VERSION 5.8 ;
BUSBITCHARS "[]" ;
DIVIDERCHAR "/" ;
UNITS
    DATABASE MICRONS 1000 ;
END UNITS

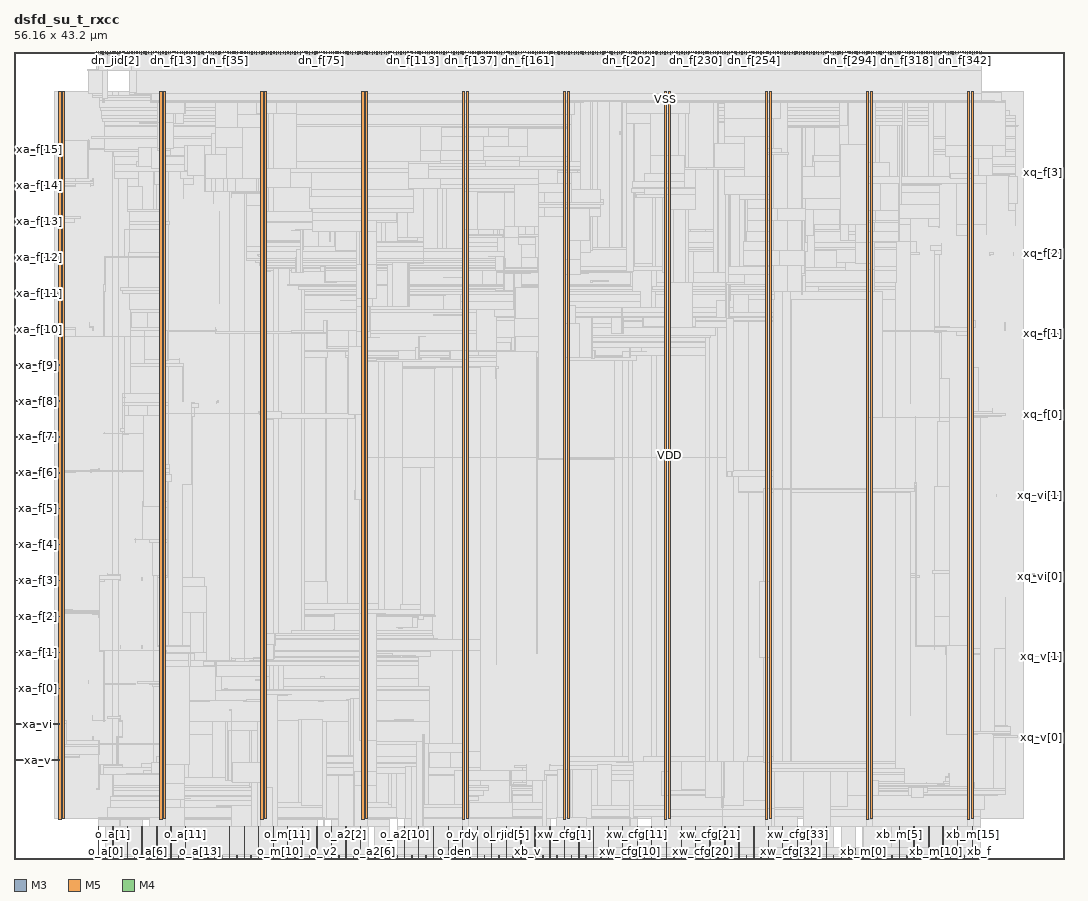
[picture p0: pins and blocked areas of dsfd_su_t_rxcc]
MACRO dsfd_su_t_rxcc
  FOREIGN dsfd_su_t_rxcc 0 0 ;
  CLASS BLOCK ;
  SIZE 56.16 BY 43.2 ;
  PIN ck
    DIRECTION INPUT ;
    USE SIGNAL ;
    PORT
      LAYER M3 ;
        RECT  28.008 43.056 28.026 43.2 ;
    END
  END ck
  PIN dn_f[0]
    DIRECTION INPUT ;
    USE SIGNAL ;
    PORT
      LAYER M5 ;
        RECT  6.816 43.008 6.84 43.2 ;
    END
  END dn_f[0]
  PIN dn_f[100]
    DIRECTION INPUT ;
    USE SIGNAL ;
    PORT
      LAYER M5 ;
        RECT  19.632 43.008 19.656 43.2 ;
    END
  END dn_f[100]
  PIN dn_f[101]
    DIRECTION INPUT ;
    USE SIGNAL ;
    PORT
      LAYER M3 ;
        RECT  19.8 43.056 19.818 43.2 ;
    END
  END dn_f[101]
  PIN dn_f[102]
    DIRECTION INPUT ;
    USE SIGNAL ;
    PORT
      LAYER M5 ;
        RECT  19.92 43.008 19.944 43.2 ;
    END
  END dn_f[102]
  PIN dn_f[103]
    DIRECTION INPUT ;
    USE SIGNAL ;
    PORT
      LAYER M3 ;
        RECT  20.052 43.056 20.07 43.2 ;
    END
  END dn_f[103]
  PIN dn_f[104]
    DIRECTION INPUT ;
    USE SIGNAL ;
    PORT
      LAYER M5 ;
        RECT  20.16 43.008 20.184 43.2 ;
    END
  END dn_f[104]
  PIN dn_f[105]
    DIRECTION INPUT ;
    USE SIGNAL ;
    PORT
      LAYER M3 ;
        RECT  20.304 43.056 20.322 43.2 ;
    END
  END dn_f[105]
  PIN dn_f[106]
    DIRECTION INPUT ;
    USE SIGNAL ;
    PORT
      LAYER M5 ;
        RECT  20.448 43.008 20.472 43.2 ;
    END
  END dn_f[106]
  PIN dn_f[107]
    DIRECTION INPUT ;
    USE SIGNAL ;
    PORT
      LAYER M3 ;
        RECT  20.556 43.056 20.574 43.2 ;
    END
  END dn_f[107]
  PIN dn_f[108]
    DIRECTION INPUT ;
    USE SIGNAL ;
    PORT
      LAYER M5 ;
        RECT  20.688 43.008 20.712 43.2 ;
    END
  END dn_f[108]
  PIN dn_f[109]
    DIRECTION INPUT ;
    USE SIGNAL ;
    PORT
      LAYER M3 ;
        RECT  20.808 43.056 20.826 43.2 ;
    END
  END dn_f[109]
  PIN dn_f[10]
    DIRECTION INPUT ;
    USE SIGNAL ;
    PORT
      LAYER M5 ;
        RECT  8.112 43.008 8.136 43.2 ;
    END
  END dn_f[10]
  PIN dn_f[110]
    DIRECTION INPUT ;
    USE SIGNAL ;
    PORT
      LAYER M5 ;
        RECT  20.928 43.008 20.952 43.2 ;
    END
  END dn_f[110]
  PIN dn_f[111]
    DIRECTION INPUT ;
    USE SIGNAL ;
    PORT
      LAYER M3 ;
        RECT  21.06 43.056 21.078 43.2 ;
    END
  END dn_f[111]
  PIN dn_f[112]
    DIRECTION INPUT ;
    USE SIGNAL ;
    PORT
      LAYER M5 ;
        RECT  21.216 43.008 21.24 43.2 ;
    END
  END dn_f[112]
  PIN dn_f[113]
    DIRECTION INPUT ;
    USE SIGNAL ;
    PORT
      LAYER M3 ;
        RECT  21.312 43.056 21.33 43.2 ;
    END
  END dn_f[113]
  PIN dn_f[114]
    DIRECTION INPUT ;
    USE SIGNAL ;
    PORT
      LAYER M5 ;
        RECT  21.456 43.008 21.48 43.2 ;
    END
  END dn_f[114]
  PIN dn_f[115]
    DIRECTION INPUT ;
    USE SIGNAL ;
    PORT
      LAYER M3 ;
        RECT  21.6 43.056 21.618 43.2 ;
    END
  END dn_f[115]
  PIN dn_f[116]
    DIRECTION INPUT ;
    USE SIGNAL ;
    PORT
      LAYER M5 ;
        RECT  21.696 43.008 21.72 43.2 ;
    END
  END dn_f[116]
  PIN dn_f[117]
    DIRECTION INPUT ;
    USE SIGNAL ;
    PORT
      LAYER M3 ;
        RECT  21.852 43.056 21.87 43.2 ;
    END
  END dn_f[117]
  PIN dn_f[118]
    DIRECTION INPUT ;
    USE SIGNAL ;
    PORT
      LAYER M5 ;
        RECT  21.984 43.008 22.008 43.2 ;
    END
  END dn_f[118]
  PIN dn_f[119]
    DIRECTION INPUT ;
    USE SIGNAL ;
    PORT
      LAYER M3 ;
        RECT  22.104 43.056 22.122 43.2 ;
    END
  END dn_f[119]
  PIN dn_f[11]
    DIRECTION INPUT ;
    USE SIGNAL ;
    PORT
      LAYER M3 ;
        RECT  8.244 43.056 8.262 43.2 ;
    END
  END dn_f[11]
  PIN dn_f[120]
    DIRECTION INPUT ;
    USE SIGNAL ;
    PORT
      LAYER M5 ;
        RECT  22.224 43.008 22.248 43.2 ;
    END
  END dn_f[120]
  PIN dn_f[121]
    DIRECTION INPUT ;
    USE SIGNAL ;
    PORT
      LAYER M3 ;
        RECT  22.356 43.056 22.374 43.2 ;
    END
  END dn_f[121]
  PIN dn_f[122]
    DIRECTION INPUT ;
    USE SIGNAL ;
    PORT
      LAYER M5 ;
        RECT  22.464 43.008 22.488 43.2 ;
    END
  END dn_f[122]
  PIN dn_f[123]
    DIRECTION INPUT ;
    USE SIGNAL ;
    PORT
      LAYER M3 ;
        RECT  22.608 43.056 22.626 43.2 ;
    END
  END dn_f[123]
  PIN dn_f[124]
    DIRECTION INPUT ;
    USE SIGNAL ;
    PORT
      LAYER M5 ;
        RECT  22.752 43.008 22.776 43.2 ;
    END
  END dn_f[124]
  PIN dn_f[125]
    DIRECTION INPUT ;
    USE SIGNAL ;
    PORT
      LAYER M3 ;
        RECT  22.86 43.056 22.878 43.2 ;
    END
  END dn_f[125]
  PIN dn_f[126]
    DIRECTION INPUT ;
    USE SIGNAL ;
    PORT
      LAYER M5 ;
        RECT  22.992 43.008 23.016 43.2 ;
    END
  END dn_f[126]
  PIN dn_f[127]
    DIRECTION INPUT ;
    USE SIGNAL ;
    PORT
      LAYER M3 ;
        RECT  23.112 43.056 23.13 43.2 ;
    END
  END dn_f[127]
  PIN dn_f[128]
    DIRECTION INPUT ;
    USE SIGNAL ;
    PORT
      LAYER M5 ;
        RECT  23.232 43.008 23.256 43.2 ;
    END
  END dn_f[128]
  PIN dn_f[129]
    DIRECTION INPUT ;
    USE SIGNAL ;
    PORT
      LAYER M3 ;
        RECT  23.4 43.056 23.418 43.2 ;
    END
  END dn_f[129]
  PIN dn_f[12]
    DIRECTION INPUT ;
    USE SIGNAL ;
    PORT
      LAYER M5 ;
        RECT  8.352 43.008 8.376 43.2 ;
    END
  END dn_f[12]
  PIN dn_f[130]
    DIRECTION INPUT ;
    USE SIGNAL ;
    PORT
      LAYER M5 ;
        RECT  23.52 43.008 23.544 43.2 ;
    END
  END dn_f[130]
  PIN dn_f[131]
    DIRECTION INPUT ;
    USE SIGNAL ;
    PORT
      LAYER M3 ;
        RECT  23.652 43.056 23.67 43.2 ;
    END
  END dn_f[131]
  PIN dn_f[132]
    DIRECTION INPUT ;
    USE SIGNAL ;
    PORT
      LAYER M5 ;
        RECT  23.76 43.008 23.784 43.2 ;
    END
  END dn_f[132]
  PIN dn_f[133]
    DIRECTION INPUT ;
    USE SIGNAL ;
    PORT
      LAYER M3 ;
        RECT  23.904 43.056 23.922 43.2 ;
    END
  END dn_f[133]
  PIN dn_f[134]
    DIRECTION INPUT ;
    USE SIGNAL ;
    PORT
      LAYER M5 ;
        RECT  24 43.008 24.024 43.2 ;
    END
  END dn_f[134]
  PIN dn_f[135]
    DIRECTION INPUT ;
    USE SIGNAL ;
    PORT
      LAYER M3 ;
        RECT  24.156 43.056 24.174 43.2 ;
    END
  END dn_f[135]
  PIN dn_f[136]
    DIRECTION INPUT ;
    USE SIGNAL ;
    PORT
      LAYER M5 ;
        RECT  24.288 43.008 24.312 43.2 ;
    END
  END dn_f[136]
  PIN dn_f[137]
    DIRECTION INPUT ;
    USE SIGNAL ;
    PORT
      LAYER M3 ;
        RECT  24.408 43.056 24.426 43.2 ;
    END
  END dn_f[137]
  PIN dn_f[138]
    DIRECTION INPUT ;
    USE SIGNAL ;
    PORT
      LAYER M5 ;
        RECT  24.528 43.008 24.552 43.2 ;
    END
  END dn_f[138]
  PIN dn_f[139]
    DIRECTION INPUT ;
    USE SIGNAL ;
    PORT
      LAYER M3 ;
        RECT  24.66 43.056 24.678 43.2 ;
    END
  END dn_f[139]
  PIN dn_f[13]
    DIRECTION INPUT ;
    USE SIGNAL ;
    PORT
      LAYER M3 ;
        RECT  8.496 43.056 8.514 43.2 ;
    END
  END dn_f[13]
  PIN dn_f[140]
    DIRECTION INPUT ;
    USE SIGNAL ;
    PORT
      LAYER M5 ;
        RECT  24.816 43.008 24.84 43.2 ;
    END
  END dn_f[140]
  PIN dn_f[141]
    DIRECTION INPUT ;
    USE SIGNAL ;
    PORT
      LAYER M3 ;
        RECT  24.912 43.056 24.93 43.2 ;
    END
  END dn_f[141]
  PIN dn_f[142]
    DIRECTION INPUT ;
    USE SIGNAL ;
    PORT
      LAYER M5 ;
        RECT  25.056 43.008 25.08 43.2 ;
    END
  END dn_f[142]
  PIN dn_f[143]
    DIRECTION INPUT ;
    USE SIGNAL ;
    PORT
      LAYER M3 ;
        RECT  25.164 43.056 25.182 43.2 ;
    END
  END dn_f[143]
  PIN dn_f[144]
    DIRECTION INPUT ;
    USE SIGNAL ;
    PORT
      LAYER M5 ;
        RECT  25.296 43.008 25.32 43.2 ;
    END
  END dn_f[144]
  PIN dn_f[145]
    DIRECTION INPUT ;
    USE SIGNAL ;
    PORT
      LAYER M3 ;
        RECT  25.452 43.056 25.47 43.2 ;
    END
  END dn_f[145]
  PIN dn_f[146]
    DIRECTION INPUT ;
    USE SIGNAL ;
    PORT
      LAYER M5 ;
        RECT  25.584 43.008 25.608 43.2 ;
    END
  END dn_f[146]
  PIN dn_f[147]
    DIRECTION INPUT ;
    USE SIGNAL ;
    PORT
      LAYER M3 ;
        RECT  25.704 43.056 25.722 43.2 ;
    END
  END dn_f[147]
  PIN dn_f[148]
    DIRECTION INPUT ;
    USE SIGNAL ;
    PORT
      LAYER M5 ;
        RECT  25.824 43.008 25.848 43.2 ;
    END
  END dn_f[148]
  PIN dn_f[149]
    DIRECTION INPUT ;
    USE SIGNAL ;
    PORT
      LAYER M3 ;
        RECT  25.956 43.056 25.974 43.2 ;
    END
  END dn_f[149]
  PIN dn_f[14]
    DIRECTION INPUT ;
    USE SIGNAL ;
    PORT
      LAYER M5 ;
        RECT  8.592 43.008 8.616 43.2 ;
    END
  END dn_f[14]
  PIN dn_f[150]
    DIRECTION INPUT ;
    USE SIGNAL ;
    PORT
      LAYER M5 ;
        RECT  26.064 43.008 26.088 43.2 ;
    END
  END dn_f[150]
  PIN dn_f[151]
    DIRECTION INPUT ;
    USE SIGNAL ;
    PORT
      LAYER M3 ;
        RECT  26.208 43.056 26.226 43.2 ;
    END
  END dn_f[151]
  PIN dn_f[152]
    DIRECTION INPUT ;
    USE SIGNAL ;
    PORT
      LAYER M5 ;
        RECT  26.352 43.008 26.376 43.2 ;
    END
  END dn_f[152]
  PIN dn_f[153]
    DIRECTION INPUT ;
    USE SIGNAL ;
    PORT
      LAYER M3 ;
        RECT  26.46 43.056 26.478 43.2 ;
    END
  END dn_f[153]
  PIN dn_f[154]
    DIRECTION INPUT ;
    USE SIGNAL ;
    PORT
      LAYER M5 ;
        RECT  26.592 43.008 26.616 43.2 ;
    END
  END dn_f[154]
  PIN dn_f[155]
    DIRECTION INPUT ;
    USE SIGNAL ;
    PORT
      LAYER M3 ;
        RECT  26.712 43.056 26.73 43.2 ;
    END
  END dn_f[155]
  PIN dn_f[156]
    DIRECTION INPUT ;
    USE SIGNAL ;
    PORT
      LAYER M5 ;
        RECT  26.832 43.008 26.856 43.2 ;
    END
  END dn_f[156]
  PIN dn_f[157]
    DIRECTION INPUT ;
    USE SIGNAL ;
    PORT
      LAYER M3 ;
        RECT  26.964 43.056 26.982 43.2 ;
    END
  END dn_f[157]
  PIN dn_f[158]
    DIRECTION INPUT ;
    USE SIGNAL ;
    PORT
      LAYER M5 ;
        RECT  27.12 43.008 27.144 43.2 ;
    END
  END dn_f[158]
  PIN dn_f[159]
    DIRECTION INPUT ;
    USE SIGNAL ;
    PORT
      LAYER M3 ;
        RECT  27.252 43.056 27.27 43.2 ;
    END
  END dn_f[159]
  PIN dn_f[15]
    DIRECTION INPUT ;
    USE SIGNAL ;
    PORT
      LAYER M3 ;
        RECT  8.748 43.056 8.766 43.2 ;
    END
  END dn_f[15]
  PIN dn_f[160]
    DIRECTION INPUT ;
    USE SIGNAL ;
    PORT
      LAYER M5 ;
        RECT  27.36 43.008 27.384 43.2 ;
    END
  END dn_f[160]
  PIN dn_f[161]
    DIRECTION INPUT ;
    USE SIGNAL ;
    PORT
      LAYER M3 ;
        RECT  27.504 43.056 27.522 43.2 ;
    END
  END dn_f[161]
  PIN dn_f[162]
    DIRECTION INPUT ;
    USE SIGNAL ;
    PORT
      LAYER M5 ;
        RECT  27.6 43.008 27.624 43.2 ;
    END
  END dn_f[162]
  PIN dn_f[163]
    DIRECTION INPUT ;
    USE SIGNAL ;
    PORT
      LAYER M3 ;
        RECT  27.756 43.056 27.774 43.2 ;
    END
  END dn_f[163]
  PIN dn_f[164]
    DIRECTION INPUT ;
    USE SIGNAL ;
    PORT
      LAYER M5 ;
        RECT  27.888 43.008 27.912 43.2 ;
    END
  END dn_f[164]
  PIN dn_f[165]
    DIRECTION INPUT ;
    USE SIGNAL ;
    PORT
      LAYER M5 ;
        RECT  28.128 43.008 28.152 43.2 ;
    END
  END dn_f[165]
  PIN dn_f[166]
    DIRECTION INPUT ;
    USE SIGNAL ;
    PORT
      LAYER M3 ;
        RECT  28.26 43.056 28.278 43.2 ;
    END
  END dn_f[166]
  PIN dn_f[167]
    DIRECTION INPUT ;
    USE SIGNAL ;
    PORT
      LAYER M5 ;
        RECT  28.368 43.008 28.392 43.2 ;
    END
  END dn_f[167]
  PIN dn_f[168]
    DIRECTION INPUT ;
    USE SIGNAL ;
    PORT
      LAYER M3 ;
        RECT  28.512 43.056 28.53 43.2 ;
    END
  END dn_f[168]
  PIN dn_f[169]
    DIRECTION INPUT ;
    USE SIGNAL ;
    PORT
      LAYER M5 ;
        RECT  28.656 43.008 28.68 43.2 ;
    END
  END dn_f[169]
  PIN dn_f[16]
    DIRECTION INPUT ;
    USE SIGNAL ;
    PORT
      LAYER M5 ;
        RECT  8.88 43.008 8.904 43.2 ;
    END
  END dn_f[16]
  PIN dn_f[170]
    DIRECTION INPUT ;
    USE SIGNAL ;
    PORT
      LAYER M3 ;
        RECT  28.764 43.056 28.782 43.2 ;
    END
  END dn_f[170]
  PIN dn_f[171]
    DIRECTION INPUT ;
    USE SIGNAL ;
    PORT
      LAYER M5 ;
        RECT  28.896 43.008 28.92 43.2 ;
    END
  END dn_f[171]
  PIN dn_f[172]
    DIRECTION INPUT ;
    USE SIGNAL ;
    PORT
      LAYER M3 ;
        RECT  29.052 43.056 29.07 43.2 ;
    END
  END dn_f[172]
  PIN dn_f[173]
    DIRECTION INPUT ;
    USE SIGNAL ;
    PORT
      LAYER M5 ;
        RECT  29.136 43.008 29.16 43.2 ;
    END
  END dn_f[173]
  PIN dn_f[174]
    DIRECTION INPUT ;
    USE SIGNAL ;
    PORT
      LAYER M3 ;
        RECT  29.304 43.056 29.322 43.2 ;
    END
  END dn_f[174]
  PIN dn_f[175]
    DIRECTION INPUT ;
    USE SIGNAL ;
    PORT
      LAYER M5 ;
        RECT  29.424 43.008 29.448 43.2 ;
    END
  END dn_f[175]
  PIN dn_f[176]
    DIRECTION INPUT ;
    USE SIGNAL ;
    PORT
      LAYER M3 ;
        RECT  29.556 43.056 29.574 43.2 ;
    END
  END dn_f[176]
  PIN dn_f[177]
    DIRECTION INPUT ;
    USE SIGNAL ;
    PORT
      LAYER M5 ;
        RECT  29.664 43.008 29.688 43.2 ;
    END
  END dn_f[177]
  PIN dn_f[178]
    DIRECTION INPUT ;
    USE SIGNAL ;
    PORT
      LAYER M3 ;
        RECT  29.808 43.056 29.826 43.2 ;
    END
  END dn_f[178]
  PIN dn_f[179]
    DIRECTION INPUT ;
    USE SIGNAL ;
    PORT
      LAYER M5 ;
        RECT  29.952 43.008 29.976 43.2 ;
    END
  END dn_f[179]
  PIN dn_f[17]
    DIRECTION INPUT ;
    USE SIGNAL ;
    PORT
      LAYER M3 ;
        RECT  9 43.056 9.018 43.2 ;
    END
  END dn_f[17]
  PIN dn_f[180]
    DIRECTION INPUT ;
    USE SIGNAL ;
    PORT
      LAYER M3 ;
        RECT  30.06 43.056 30.078 43.2 ;
    END
  END dn_f[180]
  PIN dn_f[181]
    DIRECTION INPUT ;
    USE SIGNAL ;
    PORT
      LAYER M5 ;
        RECT  30.192 43.008 30.216 43.2 ;
    END
  END dn_f[181]
  PIN dn_f[182]
    DIRECTION INPUT ;
    USE SIGNAL ;
    PORT
      LAYER M3 ;
        RECT  30.312 43.056 30.33 43.2 ;
    END
  END dn_f[182]
  PIN dn_f[183]
    DIRECTION INPUT ;
    USE SIGNAL ;
    PORT
      LAYER M5 ;
        RECT  30.432 43.008 30.456 43.2 ;
    END
  END dn_f[183]
  PIN dn_f[184]
    DIRECTION INPUT ;
    USE SIGNAL ;
    PORT
      LAYER M3 ;
        RECT  30.564 43.056 30.582 43.2 ;
    END
  END dn_f[184]
  PIN dn_f[185]
    DIRECTION INPUT ;
    USE SIGNAL ;
    PORT
      LAYER M5 ;
        RECT  30.72 43.008 30.744 43.2 ;
    END
  END dn_f[185]
  PIN dn_f[186]
    DIRECTION INPUT ;
    USE SIGNAL ;
    PORT
      LAYER M3 ;
        RECT  30.816 43.056 30.834 43.2 ;
    END
  END dn_f[186]
  PIN dn_f[187]
    DIRECTION INPUT ;
    USE SIGNAL ;
    PORT
      LAYER M5 ;
        RECT  30.96 43.008 30.984 43.2 ;
    END
  END dn_f[187]
  PIN dn_f[188]
    DIRECTION INPUT ;
    USE SIGNAL ;
    PORT
      LAYER M3 ;
        RECT  31.104 43.056 31.122 43.2 ;
    END
  END dn_f[188]
  PIN dn_f[189]
    DIRECTION INPUT ;
    USE SIGNAL ;
    PORT
      LAYER M5 ;
        RECT  31.2 43.008 31.224 43.2 ;
    END
  END dn_f[189]
  PIN dn_f[18]
    DIRECTION INPUT ;
    USE SIGNAL ;
    PORT
      LAYER M5 ;
        RECT  9.12 43.008 9.144 43.2 ;
    END
  END dn_f[18]
  PIN dn_f[190]
    DIRECTION INPUT ;
    USE SIGNAL ;
    PORT
      LAYER M3 ;
        RECT  31.356 43.056 31.374 43.2 ;
    END
  END dn_f[190]
  PIN dn_f[191]
    DIRECTION INPUT ;
    USE SIGNAL ;
    PORT
      LAYER M5 ;
        RECT  31.488 43.008 31.512 43.2 ;
    END
  END dn_f[191]
  PIN dn_f[192]
    DIRECTION INPUT ;
    USE SIGNAL ;
    PORT
      LAYER M3 ;
        RECT  31.608 43.056 31.626 43.2 ;
    END
  END dn_f[192]
  PIN dn_f[193]
    DIRECTION INPUT ;
    USE SIGNAL ;
    PORT
      LAYER M5 ;
        RECT  31.728 43.008 31.752 43.2 ;
    END
  END dn_f[193]
  PIN dn_f[194]
    DIRECTION INPUT ;
    USE SIGNAL ;
    PORT
      LAYER M3 ;
        RECT  31.86 43.056 31.878 43.2 ;
    END
  END dn_f[194]
  PIN dn_f[195]
    DIRECTION INPUT ;
    USE SIGNAL ;
    PORT
      LAYER M5 ;
        RECT  31.968 43.008 31.992 43.2 ;
    END
  END dn_f[195]
  PIN dn_f[196]
    DIRECTION INPUT ;
    USE SIGNAL ;
    PORT
      LAYER M3 ;
        RECT  32.112 43.056 32.13 43.2 ;
    END
  END dn_f[196]
  PIN dn_f[197]
    DIRECTION INPUT ;
    USE SIGNAL ;
    PORT
      LAYER M5 ;
        RECT  32.256 43.008 32.28 43.2 ;
    END
  END dn_f[197]
  PIN dn_f[198]
    DIRECTION INPUT ;
    USE SIGNAL ;
    PORT
      LAYER M3 ;
        RECT  32.364 43.056 32.382 43.2 ;
    END
  END dn_f[198]
  PIN dn_f[199]
    DIRECTION INPUT ;
    USE SIGNAL ;
    PORT
      LAYER M5 ;
        RECT  32.496 43.008 32.52 43.2 ;
    END
  END dn_f[199]
  PIN dn_f[19]
    DIRECTION INPUT ;
    USE SIGNAL ;
    PORT
      LAYER M3 ;
        RECT  9.252 43.056 9.27 43.2 ;
    END
  END dn_f[19]
  PIN dn_f[1]
    DIRECTION INPUT ;
    USE SIGNAL ;
    PORT
      LAYER M3 ;
        RECT  6.948 43.056 6.966 43.2 ;
    END
  END dn_f[1]
  PIN dn_f[200]
    DIRECTION INPUT ;
    USE SIGNAL ;
    PORT
      LAYER M3 ;
        RECT  32.616 43.056 32.634 43.2 ;
    END
  END dn_f[200]
  PIN dn_f[201]
    DIRECTION INPUT ;
    USE SIGNAL ;
    PORT
      LAYER M5 ;
        RECT  32.736 43.008 32.76 43.2 ;
    END
  END dn_f[201]
  PIN dn_f[202]
    DIRECTION INPUT ;
    USE SIGNAL ;
    PORT
      LAYER M3 ;
        RECT  32.904 43.056 32.922 43.2 ;
    END
  END dn_f[202]
  PIN dn_f[203]
    DIRECTION INPUT ;
    USE SIGNAL ;
    PORT
      LAYER M5 ;
        RECT  33.024 43.008 33.048 43.2 ;
    END
  END dn_f[203]
  PIN dn_f[204]
    DIRECTION INPUT ;
    USE SIGNAL ;
    PORT
      LAYER M3 ;
        RECT  33.156 43.056 33.174 43.2 ;
    END
  END dn_f[204]
  PIN dn_f[205]
    DIRECTION INPUT ;
    USE SIGNAL ;
    PORT
      LAYER M5 ;
        RECT  33.264 43.008 33.288 43.2 ;
    END
  END dn_f[205]
  PIN dn_f[206]
    DIRECTION INPUT ;
    USE SIGNAL ;
    PORT
      LAYER M3 ;
        RECT  33.408 43.056 33.426 43.2 ;
    END
  END dn_f[206]
  PIN dn_f[207]
    DIRECTION INPUT ;
    USE SIGNAL ;
    PORT
      LAYER M5 ;
        RECT  33.504 43.008 33.528 43.2 ;
    END
  END dn_f[207]
  PIN dn_f[208]
    DIRECTION INPUT ;
    USE SIGNAL ;
    PORT
      LAYER M3 ;
        RECT  33.66 43.056 33.678 43.2 ;
    END
  END dn_f[208]
  PIN dn_f[209]
    DIRECTION INPUT ;
    USE SIGNAL ;
    PORT
      LAYER M5 ;
        RECT  33.792 43.008 33.816 43.2 ;
    END
  END dn_f[209]
  PIN dn_f[20]
    DIRECTION INPUT ;
    USE SIGNAL ;
    PORT
      LAYER M5 ;
        RECT  9.36 43.008 9.384 43.2 ;
    END
  END dn_f[20]
  PIN dn_f[210]
    DIRECTION INPUT ;
    USE SIGNAL ;
    PORT
      LAYER M3 ;
        RECT  33.912 43.056 33.93 43.2 ;
    END
  END dn_f[210]
  PIN dn_f[211]
    DIRECTION INPUT ;
    USE SIGNAL ;
    PORT
      LAYER M5 ;
        RECT  34.032 43.008 34.056 43.2 ;
    END
  END dn_f[211]
  PIN dn_f[212]
    DIRECTION INPUT ;
    USE SIGNAL ;
    PORT
      LAYER M3 ;
        RECT  34.164 43.056 34.182 43.2 ;
    END
  END dn_f[212]
  PIN dn_f[213]
    DIRECTION INPUT ;
    USE SIGNAL ;
    PORT
      LAYER M5 ;
        RECT  34.32 43.008 34.344 43.2 ;
    END
  END dn_f[213]
  PIN dn_f[214]
    DIRECTION INPUT ;
    USE SIGNAL ;
    PORT
      LAYER M3 ;
        RECT  34.416 43.056 34.434 43.2 ;
    END
  END dn_f[214]
  PIN dn_f[215]
    DIRECTION INPUT ;
    USE SIGNAL ;
    PORT
      LAYER M5 ;
        RECT  34.56 43.008 34.584 43.2 ;
    END
  END dn_f[215]
  PIN dn_f[216]
    DIRECTION INPUT ;
    USE SIGNAL ;
    PORT
      LAYER M3 ;
        RECT  34.668 43.056 34.686 43.2 ;
    END
  END dn_f[216]
  PIN dn_f[217]
    DIRECTION INPUT ;
    USE SIGNAL ;
    PORT
      LAYER M5 ;
        RECT  34.8 43.008 34.824 43.2 ;
    END
  END dn_f[217]
  PIN dn_f[218]
    DIRECTION INPUT ;
    USE SIGNAL ;
    PORT
      LAYER M3 ;
        RECT  34.956 43.056 34.974 43.2 ;
    END
  END dn_f[218]
  PIN dn_f[219]
    DIRECTION INPUT ;
    USE SIGNAL ;
    PORT
      LAYER M5 ;
        RECT  35.088 43.008 35.112 43.2 ;
    END
  END dn_f[219]
  PIN dn_f[21]
    DIRECTION INPUT ;
    USE SIGNAL ;
    PORT
      LAYER M3 ;
        RECT  9.504 43.056 9.522 43.2 ;
    END
  END dn_f[21]
  PIN dn_f[220]
    DIRECTION INPUT ;
    USE SIGNAL ;
    PORT
      LAYER M3 ;
        RECT  35.208 43.056 35.226 43.2 ;
    END
  END dn_f[220]
  PIN dn_f[221]
    DIRECTION INPUT ;
    USE SIGNAL ;
    PORT
      LAYER M5 ;
        RECT  35.328 43.008 35.352 43.2 ;
    END
  END dn_f[221]
  PIN dn_f[222]
    DIRECTION INPUT ;
    USE SIGNAL ;
    PORT
      LAYER M3 ;
        RECT  35.46 43.056 35.478 43.2 ;
    END
  END dn_f[222]
  PIN dn_f[223]
    DIRECTION INPUT ;
    USE SIGNAL ;
    PORT
      LAYER M5 ;
        RECT  35.568 43.008 35.592 43.2 ;
    END
  END dn_f[223]
  PIN dn_f[224]
    DIRECTION INPUT ;
    USE SIGNAL ;
    PORT
      LAYER M3 ;
        RECT  35.712 43.056 35.73 43.2 ;
    END
  END dn_f[224]
  PIN dn_f[225]
    DIRECTION INPUT ;
    USE SIGNAL ;
    PORT
      LAYER M5 ;
        RECT  35.856 43.008 35.88 43.2 ;
    END
  END dn_f[225]
  PIN dn_f[226]
    DIRECTION INPUT ;
    USE SIGNAL ;
    PORT
      LAYER M3 ;
        RECT  35.964 43.056 35.982 43.2 ;
    END
  END dn_f[226]
  PIN dn_f[227]
    DIRECTION INPUT ;
    USE SIGNAL ;
    PORT
      LAYER M5 ;
        RECT  36.096 43.008 36.12 43.2 ;
    END
  END dn_f[227]
  PIN dn_f[228]
    DIRECTION INPUT ;
    USE SIGNAL ;
    PORT
      LAYER M3 ;
        RECT  36.216 43.056 36.234 43.2 ;
    END
  END dn_f[228]
  PIN dn_f[229]
    DIRECTION INPUT ;
    USE SIGNAL ;
    PORT
      LAYER M5 ;
        RECT  36.336 43.008 36.36 43.2 ;
    END
  END dn_f[229]
  PIN dn_f[22]
    DIRECTION INPUT ;
    USE SIGNAL ;
    PORT
      LAYER M5 ;
        RECT  9.648 43.008 9.672 43.2 ;
    END
  END dn_f[22]
  PIN dn_f[230]
    DIRECTION INPUT ;
    USE SIGNAL ;
    PORT
      LAYER M3 ;
        RECT  36.468 43.056 36.486 43.2 ;
    END
  END dn_f[230]
  PIN dn_f[231]
    DIRECTION INPUT ;
    USE SIGNAL ;
    PORT
      LAYER M5 ;
        RECT  36.624 43.008 36.648 43.2 ;
    END
  END dn_f[231]
  PIN dn_f[232]
    DIRECTION INPUT ;
    USE SIGNAL ;
    PORT
      LAYER M3 ;
        RECT  36.756 43.056 36.774 43.2 ;
    END
  END dn_f[232]
  PIN dn_f[233]
    DIRECTION INPUT ;
    USE SIGNAL ;
    PORT
      LAYER M5 ;
        RECT  36.864 43.008 36.888 43.2 ;
    END
  END dn_f[233]
  PIN dn_f[234]
    DIRECTION INPUT ;
    USE SIGNAL ;
    PORT
      LAYER M3 ;
        RECT  37.008 43.056 37.026 43.2 ;
    END
  END dn_f[234]
  PIN dn_f[235]
    DIRECTION INPUT ;
    USE SIGNAL ;
    PORT
      LAYER M5 ;
        RECT  37.104 43.008 37.128 43.2 ;
    END
  END dn_f[235]
  PIN dn_f[236]
    DIRECTION INPUT ;
    USE SIGNAL ;
    PORT
      LAYER M3 ;
        RECT  37.26 43.056 37.278 43.2 ;
    END
  END dn_f[236]
  PIN dn_f[237]
    DIRECTION INPUT ;
    USE SIGNAL ;
    PORT
      LAYER M5 ;
        RECT  37.392 43.008 37.416 43.2 ;
    END
  END dn_f[237]
  PIN dn_f[238]
    DIRECTION INPUT ;
    USE SIGNAL ;
    PORT
      LAYER M3 ;
        RECT  37.512 43.056 37.53 43.2 ;
    END
  END dn_f[238]
  PIN dn_f[239]
    DIRECTION INPUT ;
    USE SIGNAL ;
    PORT
      LAYER M5 ;
        RECT  37.632 43.008 37.656 43.2 ;
    END
  END dn_f[239]
  PIN dn_f[23]
    DIRECTION INPUT ;
    USE SIGNAL ;
    PORT
      LAYER M3 ;
        RECT  9.756 43.056 9.774 43.2 ;
    END
  END dn_f[23]
  PIN dn_f[240]
    DIRECTION INPUT ;
    USE SIGNAL ;
    PORT
      LAYER M3 ;
        RECT  37.764 43.056 37.782 43.2 ;
    END
  END dn_f[240]
  PIN dn_f[241]
    DIRECTION INPUT ;
    USE SIGNAL ;
    PORT
      LAYER M5 ;
        RECT  37.872 43.008 37.896 43.2 ;
    END
  END dn_f[241]
  PIN dn_f[242]
    DIRECTION INPUT ;
    USE SIGNAL ;
    PORT
      LAYER M3 ;
        RECT  38.016 43.056 38.034 43.2 ;
    END
  END dn_f[242]
  PIN dn_f[243]
    DIRECTION INPUT ;
    USE SIGNAL ;
    PORT
      LAYER M5 ;
        RECT  38.16 43.008 38.184 43.2 ;
    END
  END dn_f[243]
  PIN dn_f[244]
    DIRECTION INPUT ;
    USE SIGNAL ;
    PORT
      LAYER M3 ;
        RECT  38.268 43.056 38.286 43.2 ;
    END
  END dn_f[244]
  PIN dn_f[245]
    DIRECTION INPUT ;
    USE SIGNAL ;
    PORT
      LAYER M5 ;
        RECT  38.4 43.008 38.424 43.2 ;
    END
  END dn_f[245]
  PIN dn_f[246]
    DIRECTION INPUT ;
    USE SIGNAL ;
    PORT
      LAYER M3 ;
        RECT  38.556 43.056 38.574 43.2 ;
    END
  END dn_f[246]
  PIN dn_f[247]
    DIRECTION INPUT ;
    USE SIGNAL ;
    PORT
      LAYER M5 ;
        RECT  38.64 43.008 38.664 43.2 ;
    END
  END dn_f[247]
  PIN dn_f[248]
    DIRECTION INPUT ;
    USE SIGNAL ;
    PORT
      LAYER M3 ;
        RECT  38.808 43.056 38.826 43.2 ;
    END
  END dn_f[248]
  PIN dn_f[249]
    DIRECTION INPUT ;
    USE SIGNAL ;
    PORT
      LAYER M5 ;
        RECT  38.928 43.008 38.952 43.2 ;
    END
  END dn_f[249]
  PIN dn_f[24]
    DIRECTION INPUT ;
    USE SIGNAL ;
    PORT
      LAYER M5 ;
        RECT  9.888 43.008 9.912 43.2 ;
    END
  END dn_f[24]
  PIN dn_f[250]
    DIRECTION INPUT ;
    USE SIGNAL ;
    PORT
      LAYER M3 ;
        RECT  39.06 43.056 39.078 43.2 ;
    END
  END dn_f[250]
  PIN dn_f[251]
    DIRECTION INPUT ;
    USE SIGNAL ;
    PORT
      LAYER M5 ;
        RECT  39.168 43.008 39.192 43.2 ;
    END
  END dn_f[251]
  PIN dn_f[252]
    DIRECTION INPUT ;
    USE SIGNAL ;
    PORT
      LAYER M3 ;
        RECT  39.312 43.056 39.33 43.2 ;
    END
  END dn_f[252]
  PIN dn_f[253]
    DIRECTION INPUT ;
    USE SIGNAL ;
    PORT
      LAYER M5 ;
        RECT  39.456 43.008 39.48 43.2 ;
    END
  END dn_f[253]
  PIN dn_f[254]
    DIRECTION INPUT ;
    USE SIGNAL ;
    PORT
      LAYER M3 ;
        RECT  39.564 43.056 39.582 43.2 ;
    END
  END dn_f[254]
  PIN dn_f[255]
    DIRECTION INPUT ;
    USE SIGNAL ;
    PORT
      LAYER M5 ;
        RECT  39.696 43.008 39.72 43.2 ;
    END
  END dn_f[255]
  PIN dn_f[256]
    DIRECTION INPUT ;
    USE SIGNAL ;
    PORT
      LAYER M3 ;
        RECT  39.816 43.056 39.834 43.2 ;
    END
  END dn_f[256]
  PIN dn_f[257]
    DIRECTION INPUT ;
    USE SIGNAL ;
    PORT
      LAYER M5 ;
        RECT  39.936 43.008 39.96 43.2 ;
    END
  END dn_f[257]
  PIN dn_f[258]
    DIRECTION INPUT ;
    USE SIGNAL ;
    PORT
      LAYER M3 ;
        RECT  40.068 43.056 40.086 43.2 ;
    END
  END dn_f[258]
  PIN dn_f[259]
    DIRECTION INPUT ;
    USE SIGNAL ;
    PORT
      LAYER M5 ;
        RECT  40.224 43.008 40.248 43.2 ;
    END
  END dn_f[259]
  PIN dn_f[25]
    DIRECTION INPUT ;
    USE SIGNAL ;
    PORT
      LAYER M3 ;
        RECT  10.044 43.056 10.062 43.2 ;
    END
  END dn_f[25]
  PIN dn_f[260]
    DIRECTION INPUT ;
    USE SIGNAL ;
    PORT
      LAYER M3 ;
        RECT  40.32 43.056 40.338 43.2 ;
    END
  END dn_f[260]
  PIN dn_f[261]
    DIRECTION INPUT ;
    USE SIGNAL ;
    PORT
      LAYER M5 ;
        RECT  40.464 43.008 40.488 43.2 ;
    END
  END dn_f[261]
  PIN dn_f[262]
    DIRECTION INPUT ;
    USE SIGNAL ;
    PORT
      LAYER M3 ;
        RECT  40.608 43.056 40.626 43.2 ;
    END
  END dn_f[262]
  PIN dn_f[263]
    DIRECTION INPUT ;
    USE SIGNAL ;
    PORT
      LAYER M5 ;
        RECT  40.704 43.008 40.728 43.2 ;
    END
  END dn_f[263]
  PIN dn_f[264]
    DIRECTION INPUT ;
    USE SIGNAL ;
    PORT
      LAYER M3 ;
        RECT  40.86 43.056 40.878 43.2 ;
    END
  END dn_f[264]
  PIN dn_f[265]
    DIRECTION INPUT ;
    USE SIGNAL ;
    PORT
      LAYER M5 ;
        RECT  40.992 43.008 41.016 43.2 ;
    END
  END dn_f[265]
  PIN dn_f[266]
    DIRECTION INPUT ;
    USE SIGNAL ;
    PORT
      LAYER M3 ;
        RECT  41.112 43.056 41.13 43.2 ;
    END
  END dn_f[266]
  PIN dn_f[267]
    DIRECTION INPUT ;
    USE SIGNAL ;
    PORT
      LAYER M5 ;
        RECT  41.232 43.008 41.256 43.2 ;
    END
  END dn_f[267]
  PIN dn_f[268]
    DIRECTION INPUT ;
    USE SIGNAL ;
    PORT
      LAYER M3 ;
        RECT  41.364 43.056 41.382 43.2 ;
    END
  END dn_f[268]
  PIN dn_f[269]
    DIRECTION INPUT ;
    USE SIGNAL ;
    PORT
      LAYER M5 ;
        RECT  41.472 43.008 41.496 43.2 ;
    END
  END dn_f[269]
  PIN dn_f[26]
    DIRECTION INPUT ;
    USE SIGNAL ;
    PORT
      LAYER M5 ;
        RECT  10.128 43.008 10.152 43.2 ;
    END
  END dn_f[26]
  PIN dn_f[270]
    DIRECTION INPUT ;
    USE SIGNAL ;
    PORT
      LAYER M3 ;
        RECT  41.616 43.056 41.634 43.2 ;
    END
  END dn_f[270]
  PIN dn_f[271]
    DIRECTION INPUT ;
    USE SIGNAL ;
    PORT
      LAYER M5 ;
        RECT  41.76 43.008 41.784 43.2 ;
    END
  END dn_f[271]
  PIN dn_f[272]
    DIRECTION INPUT ;
    USE SIGNAL ;
    PORT
      LAYER M3 ;
        RECT  41.868 43.056 41.886 43.2 ;
    END
  END dn_f[272]
  PIN dn_f[273]
    DIRECTION INPUT ;
    USE SIGNAL ;
    PORT
      LAYER M5 ;
        RECT  42 43.008 42.024 43.2 ;
    END
  END dn_f[273]
  PIN dn_f[274]
    DIRECTION INPUT ;
    USE SIGNAL ;
    PORT
      LAYER M3 ;
        RECT  42.12 43.056 42.138 43.2 ;
    END
  END dn_f[274]
  PIN dn_f[275]
    DIRECTION INPUT ;
    USE SIGNAL ;
    PORT
      LAYER M5 ;
        RECT  42.24 43.008 42.264 43.2 ;
    END
  END dn_f[275]
  PIN dn_f[276]
    DIRECTION INPUT ;
    USE SIGNAL ;
    PORT
      LAYER M3 ;
        RECT  42.408 43.056 42.426 43.2 ;
    END
  END dn_f[276]
  PIN dn_f[277]
    DIRECTION INPUT ;
    USE SIGNAL ;
    PORT
      LAYER M5 ;
        RECT  42.528 43.008 42.552 43.2 ;
    END
  END dn_f[277]
  PIN dn_f[278]
    DIRECTION INPUT ;
    USE SIGNAL ;
    PORT
      LAYER M3 ;
        RECT  42.66 43.056 42.678 43.2 ;
    END
  END dn_f[278]
  PIN dn_f[279]
    DIRECTION INPUT ;
    USE SIGNAL ;
    PORT
      LAYER M5 ;
        RECT  42.768 43.008 42.792 43.2 ;
    END
  END dn_f[279]
  PIN dn_f[27]
    DIRECTION INPUT ;
    USE SIGNAL ;
    PORT
      LAYER M3 ;
        RECT  10.296 43.056 10.314 43.2 ;
    END
  END dn_f[27]
  PIN dn_f[280]
    DIRECTION INPUT ;
    USE SIGNAL ;
    PORT
      LAYER M3 ;
        RECT  42.912 43.056 42.93 43.2 ;
    END
  END dn_f[280]
  PIN dn_f[281]
    DIRECTION INPUT ;
    USE SIGNAL ;
    PORT
      LAYER M5 ;
        RECT  43.008 43.008 43.032 43.2 ;
    END
  END dn_f[281]
  PIN dn_f[282]
    DIRECTION INPUT ;
    USE SIGNAL ;
    PORT
      LAYER M3 ;
        RECT  43.164 43.056 43.182 43.2 ;
    END
  END dn_f[282]
  PIN dn_f[283]
    DIRECTION INPUT ;
    USE SIGNAL ;
    PORT
      LAYER M5 ;
        RECT  43.296 43.008 43.32 43.2 ;
    END
  END dn_f[283]
  PIN dn_f[284]
    DIRECTION INPUT ;
    USE SIGNAL ;
    PORT
      LAYER M3 ;
        RECT  43.416 43.056 43.434 43.2 ;
    END
  END dn_f[284]
  PIN dn_f[285]
    DIRECTION INPUT ;
    USE SIGNAL ;
    PORT
      LAYER M5 ;
        RECT  43.536 43.008 43.56 43.2 ;
    END
  END dn_f[285]
  PIN dn_f[286]
    DIRECTION INPUT ;
    USE SIGNAL ;
    PORT
      LAYER M3 ;
        RECT  43.668 43.056 43.686 43.2 ;
    END
  END dn_f[286]
  PIN dn_f[287]
    DIRECTION INPUT ;
    USE SIGNAL ;
    PORT
      LAYER M5 ;
        RECT  43.824 43.008 43.848 43.2 ;
    END
  END dn_f[287]
  PIN dn_f[288]
    DIRECTION INPUT ;
    USE SIGNAL ;
    PORT
      LAYER M3 ;
        RECT  43.92 43.056 43.938 43.2 ;
    END
  END dn_f[288]
  PIN dn_f[289]
    DIRECTION INPUT ;
    USE SIGNAL ;
    PORT
      LAYER M5 ;
        RECT  44.064 43.008 44.088 43.2 ;
    END
  END dn_f[289]
  PIN dn_f[28]
    DIRECTION INPUT ;
    USE SIGNAL ;
    PORT
      LAYER M5 ;
        RECT  10.416 43.008 10.44 43.2 ;
    END
  END dn_f[28]
  PIN dn_f[290]
    DIRECTION INPUT ;
    USE SIGNAL ;
    PORT
      LAYER M3 ;
        RECT  44.172 43.056 44.19 43.2 ;
    END
  END dn_f[290]
  PIN dn_f[291]
    DIRECTION INPUT ;
    USE SIGNAL ;
    PORT
      LAYER M5 ;
        RECT  44.304 43.008 44.328 43.2 ;
    END
  END dn_f[291]
  PIN dn_f[292]
    DIRECTION INPUT ;
    USE SIGNAL ;
    PORT
      LAYER M3 ;
        RECT  44.46 43.056 44.478 43.2 ;
    END
  END dn_f[292]
  PIN dn_f[293]
    DIRECTION INPUT ;
    USE SIGNAL ;
    PORT
      LAYER M5 ;
        RECT  44.592 43.008 44.616 43.2 ;
    END
  END dn_f[293]
  PIN dn_f[294]
    DIRECTION INPUT ;
    USE SIGNAL ;
    PORT
      LAYER M3 ;
        RECT  44.712 43.056 44.73 43.2 ;
    END
  END dn_f[294]
  PIN dn_f[295]
    DIRECTION INPUT ;
    USE SIGNAL ;
    PORT
      LAYER M5 ;
        RECT  44.832 43.008 44.856 43.2 ;
    END
  END dn_f[295]
  PIN dn_f[296]
    DIRECTION INPUT ;
    USE SIGNAL ;
    PORT
      LAYER M3 ;
        RECT  44.964 43.056 44.982 43.2 ;
    END
  END dn_f[296]
  PIN dn_f[297]
    DIRECTION INPUT ;
    USE SIGNAL ;
    PORT
      LAYER M5 ;
        RECT  45.072 43.008 45.096 43.2 ;
    END
  END dn_f[297]
  PIN dn_f[298]
    DIRECTION INPUT ;
    USE SIGNAL ;
    PORT
      LAYER M3 ;
        RECT  45.216 43.056 45.234 43.2 ;
    END
  END dn_f[298]
  PIN dn_f[299]
    DIRECTION INPUT ;
    USE SIGNAL ;
    PORT
      LAYER M5 ;
        RECT  45.36 43.008 45.384 43.2 ;
    END
  END dn_f[299]
  PIN dn_f[29]
    DIRECTION INPUT ;
    USE SIGNAL ;
    PORT
      LAYER M3 ;
        RECT  10.548 43.056 10.566 43.2 ;
    END
  END dn_f[29]
  PIN dn_f[2]
    DIRECTION INPUT ;
    USE SIGNAL ;
    PORT
      LAYER M5 ;
        RECT  7.056 43.008 7.08 43.2 ;
    END
  END dn_f[2]
  PIN dn_f[300]
    DIRECTION INPUT ;
    USE SIGNAL ;
    PORT
      LAYER M3 ;
        RECT  45.468 43.056 45.486 43.2 ;
    END
  END dn_f[300]
  PIN dn_f[301]
    DIRECTION INPUT ;
    USE SIGNAL ;
    PORT
      LAYER M5 ;
        RECT  45.6 43.008 45.624 43.2 ;
    END
  END dn_f[301]
  PIN dn_f[302]
    DIRECTION INPUT ;
    USE SIGNAL ;
    PORT
      LAYER M3 ;
        RECT  45.72 43.056 45.738 43.2 ;
    END
  END dn_f[302]
  PIN dn_f[303]
    DIRECTION INPUT ;
    USE SIGNAL ;
    PORT
      LAYER M5 ;
        RECT  45.84 43.008 45.864 43.2 ;
    END
  END dn_f[303]
  PIN dn_f[304]
    DIRECTION INPUT ;
    USE SIGNAL ;
    PORT
      LAYER M3 ;
        RECT  45.972 43.056 45.99 43.2 ;
    END
  END dn_f[304]
  PIN dn_f[305]
    DIRECTION INPUT ;
    USE SIGNAL ;
    PORT
      LAYER M5 ;
        RECT  46.128 43.008 46.152 43.2 ;
    END
  END dn_f[305]
  PIN dn_f[306]
    DIRECTION INPUT ;
    USE SIGNAL ;
    PORT
      LAYER M3 ;
        RECT  46.26 43.056 46.278 43.2 ;
    END
  END dn_f[306]
  PIN dn_f[307]
    DIRECTION INPUT ;
    USE SIGNAL ;
    PORT
      LAYER M5 ;
        RECT  46.368 43.008 46.392 43.2 ;
    END
  END dn_f[307]
  PIN dn_f[308]
    DIRECTION INPUT ;
    USE SIGNAL ;
    PORT
      LAYER M3 ;
        RECT  46.512 43.056 46.53 43.2 ;
    END
  END dn_f[308]
  PIN dn_f[309]
    DIRECTION INPUT ;
    USE SIGNAL ;
    PORT
      LAYER M5 ;
        RECT  46.608 43.008 46.632 43.2 ;
    END
  END dn_f[309]
  PIN dn_f[30]
    DIRECTION INPUT ;
    USE SIGNAL ;
    PORT
      LAYER M5 ;
        RECT  10.656 43.008 10.68 43.2 ;
    END
  END dn_f[30]
  PIN dn_f[310]
    DIRECTION INPUT ;
    USE SIGNAL ;
    PORT
      LAYER M3 ;
        RECT  46.764 43.056 46.782 43.2 ;
    END
  END dn_f[310]
  PIN dn_f[311]
    DIRECTION INPUT ;
    USE SIGNAL ;
    PORT
      LAYER M5 ;
        RECT  46.896 43.008 46.92 43.2 ;
    END
  END dn_f[311]
  PIN dn_f[312]
    DIRECTION INPUT ;
    USE SIGNAL ;
    PORT
      LAYER M3 ;
        RECT  47.016 43.056 47.034 43.2 ;
    END
  END dn_f[312]
  PIN dn_f[313]
    DIRECTION INPUT ;
    USE SIGNAL ;
    PORT
      LAYER M5 ;
        RECT  47.136 43.008 47.16 43.2 ;
    END
  END dn_f[313]
  PIN dn_f[314]
    DIRECTION INPUT ;
    USE SIGNAL ;
    PORT
      LAYER M3 ;
        RECT  47.268 43.056 47.286 43.2 ;
    END
  END dn_f[314]
  PIN dn_f[315]
    DIRECTION INPUT ;
    USE SIGNAL ;
    PORT
      LAYER M5 ;
        RECT  47.376 43.008 47.4 43.2 ;
    END
  END dn_f[315]
  PIN dn_f[316]
    DIRECTION INPUT ;
    USE SIGNAL ;
    PORT
      LAYER M3 ;
        RECT  47.52 43.056 47.538 43.2 ;
    END
  END dn_f[316]
  PIN dn_f[317]
    DIRECTION INPUT ;
    USE SIGNAL ;
    PORT
      LAYER M5 ;
        RECT  47.664 43.008 47.688 43.2 ;
    END
  END dn_f[317]
  PIN dn_f[318]
    DIRECTION INPUT ;
    USE SIGNAL ;
    PORT
      LAYER M3 ;
        RECT  47.772 43.056 47.79 43.2 ;
    END
  END dn_f[318]
  PIN dn_f[319]
    DIRECTION INPUT ;
    USE SIGNAL ;
    PORT
      LAYER M5 ;
        RECT  47.904 43.008 47.928 43.2 ;
    END
  END dn_f[319]
  PIN dn_f[31]
    DIRECTION INPUT ;
    USE SIGNAL ;
    PORT
      LAYER M3 ;
        RECT  10.8 43.056 10.818 43.2 ;
    END
  END dn_f[31]
  PIN dn_f[320]
    DIRECTION INPUT ;
    USE SIGNAL ;
    PORT
      LAYER M3 ;
        RECT  48.06 43.056 48.078 43.2 ;
    END
  END dn_f[320]
  PIN dn_f[321]
    DIRECTION INPUT ;
    USE SIGNAL ;
    PORT
      LAYER M5 ;
        RECT  48.144 43.008 48.168 43.2 ;
    END
  END dn_f[321]
  PIN dn_f[322]
    DIRECTION INPUT ;
    USE SIGNAL ;
    PORT
      LAYER M3 ;
        RECT  48.312 43.056 48.33 43.2 ;
    END
  END dn_f[322]
  PIN dn_f[323]
    DIRECTION INPUT ;
    USE SIGNAL ;
    PORT
      LAYER M5 ;
        RECT  48.432 43.008 48.456 43.2 ;
    END
  END dn_f[323]
  PIN dn_f[324]
    DIRECTION INPUT ;
    USE SIGNAL ;
    PORT
      LAYER M3 ;
        RECT  48.564 43.056 48.582 43.2 ;
    END
  END dn_f[324]
  PIN dn_f[325]
    DIRECTION INPUT ;
    USE SIGNAL ;
    PORT
      LAYER M5 ;
        RECT  48.672 43.008 48.696 43.2 ;
    END
  END dn_f[325]
  PIN dn_f[326]
    DIRECTION INPUT ;
    USE SIGNAL ;
    PORT
      LAYER M3 ;
        RECT  48.816 43.056 48.834 43.2 ;
    END
  END dn_f[326]
  PIN dn_f[327]
    DIRECTION INPUT ;
    USE SIGNAL ;
    PORT
      LAYER M5 ;
        RECT  48.96 43.008 48.984 43.2 ;
    END
  END dn_f[327]
  PIN dn_f[328]
    DIRECTION INPUT ;
    USE SIGNAL ;
    PORT
      LAYER M3 ;
        RECT  49.068 43.056 49.086 43.2 ;
    END
  END dn_f[328]
  PIN dn_f[329]
    DIRECTION INPUT ;
    USE SIGNAL ;
    PORT
      LAYER M5 ;
        RECT  49.2 43.008 49.224 43.2 ;
    END
  END dn_f[329]
  PIN dn_f[32]
    DIRECTION INPUT ;
    USE SIGNAL ;
    PORT
      LAYER M5 ;
        RECT  10.944 43.008 10.968 43.2 ;
    END
  END dn_f[32]
  PIN dn_f[330]
    DIRECTION INPUT ;
    USE SIGNAL ;
    PORT
      LAYER M3 ;
        RECT  49.32 43.056 49.338 43.2 ;
    END
  END dn_f[330]
  PIN dn_f[331]
    DIRECTION INPUT ;
    USE SIGNAL ;
    PORT
      LAYER M5 ;
        RECT  49.44 43.008 49.464 43.2 ;
    END
  END dn_f[331]
  PIN dn_f[332]
    DIRECTION INPUT ;
    USE SIGNAL ;
    PORT
      LAYER M3 ;
        RECT  49.572 43.056 49.59 43.2 ;
    END
  END dn_f[332]
  PIN dn_f[333]
    DIRECTION INPUT ;
    USE SIGNAL ;
    PORT
      LAYER M5 ;
        RECT  49.728 43.008 49.752 43.2 ;
    END
  END dn_f[333]
  PIN dn_f[334]
    DIRECTION INPUT ;
    USE SIGNAL ;
    PORT
      LAYER M3 ;
        RECT  49.824 43.056 49.842 43.2 ;
    END
  END dn_f[334]
  PIN dn_f[335]
    DIRECTION INPUT ;
    USE SIGNAL ;
    PORT
      LAYER M5 ;
        RECT  49.968 43.008 49.992 43.2 ;
    END
  END dn_f[335]
  PIN dn_f[336]
    DIRECTION INPUT ;
    USE SIGNAL ;
    PORT
      LAYER M3 ;
        RECT  50.112 43.056 50.13 43.2 ;
    END
  END dn_f[336]
  PIN dn_f[337]
    DIRECTION INPUT ;
    USE SIGNAL ;
    PORT
      LAYER M5 ;
        RECT  50.208 43.008 50.232 43.2 ;
    END
  END dn_f[337]
  PIN dn_f[338]
    DIRECTION INPUT ;
    USE SIGNAL ;
    PORT
      LAYER M3 ;
        RECT  50.364 43.056 50.382 43.2 ;
    END
  END dn_f[338]
  PIN dn_f[339]
    DIRECTION INPUT ;
    USE SIGNAL ;
    PORT
      LAYER M5 ;
        RECT  50.496 43.008 50.52 43.2 ;
    END
  END dn_f[339]
  PIN dn_f[33]
    DIRECTION INPUT ;
    USE SIGNAL ;
    PORT
      LAYER M3 ;
        RECT  11.052 43.056 11.07 43.2 ;
    END
  END dn_f[33]
  PIN dn_f[340]
    DIRECTION INPUT ;
    USE SIGNAL ;
    PORT
      LAYER M3 ;
        RECT  50.616 43.056 50.634 43.2 ;
    END
  END dn_f[340]
  PIN dn_f[341]
    DIRECTION INPUT ;
    USE SIGNAL ;
    PORT
      LAYER M5 ;
        RECT  50.736 43.008 50.76 43.2 ;
    END
  END dn_f[341]
  PIN dn_f[342]
    DIRECTION INPUT ;
    USE SIGNAL ;
    PORT
      LAYER M3 ;
        RECT  50.868 43.056 50.886 43.2 ;
    END
  END dn_f[342]
  PIN dn_f[343]
    DIRECTION INPUT ;
    USE SIGNAL ;
    PORT
      LAYER M5 ;
        RECT  50.976 43.008 51 43.2 ;
    END
  END dn_f[343]
  PIN dn_f[344]
    DIRECTION INPUT ;
    USE SIGNAL ;
    PORT
      LAYER M3 ;
        RECT  51.12 43.056 51.138 43.2 ;
    END
  END dn_f[344]
  PIN dn_f[345]
    DIRECTION INPUT ;
    USE SIGNAL ;
    PORT
      LAYER M5 ;
        RECT  51.264 43.008 51.288 43.2 ;
    END
  END dn_f[345]
  PIN dn_f[346]
    DIRECTION INPUT ;
    USE SIGNAL ;
    PORT
      LAYER M3 ;
        RECT  51.372 43.056 51.39 43.2 ;
    END
  END dn_f[346]
  PIN dn_f[347]
    DIRECTION INPUT ;
    USE SIGNAL ;
    PORT
      LAYER M5 ;
        RECT  51.504 43.008 51.528 43.2 ;
    END
  END dn_f[347]
  PIN dn_f[348]
    DIRECTION INPUT ;
    USE SIGNAL ;
    PORT
      LAYER M3 ;
        RECT  51.624 43.056 51.642 43.2 ;
    END
  END dn_f[348]
  PIN dn_f[349]
    DIRECTION INPUT ;
    USE SIGNAL ;
    PORT
      LAYER M5 ;
        RECT  51.744 43.008 51.768 43.2 ;
    END
  END dn_f[349]
  PIN dn_f[34]
    DIRECTION INPUT ;
    USE SIGNAL ;
    PORT
      LAYER M5 ;
        RECT  11.184 43.008 11.208 43.2 ;
    END
  END dn_f[34]
  PIN dn_f[35]
    DIRECTION INPUT ;
    USE SIGNAL ;
    PORT
      LAYER M3 ;
        RECT  11.304 43.056 11.322 43.2 ;
    END
  END dn_f[35]
  PIN dn_f[36]
    DIRECTION INPUT ;
    USE SIGNAL ;
    PORT
      LAYER M5 ;
        RECT  11.424 43.008 11.448 43.2 ;
    END
  END dn_f[36]
  PIN dn_f[37]
    DIRECTION INPUT ;
    USE SIGNAL ;
    PORT
      LAYER M3 ;
        RECT  11.556 43.056 11.574 43.2 ;
    END
  END dn_f[37]
  PIN dn_f[38]
    DIRECTION INPUT ;
    USE SIGNAL ;
    PORT
      LAYER M5 ;
        RECT  11.712 43.008 11.736 43.2 ;
    END
  END dn_f[38]
  PIN dn_f[39]
    DIRECTION INPUT ;
    USE SIGNAL ;
    PORT
      LAYER M3 ;
        RECT  11.808 43.056 11.826 43.2 ;
    END
  END dn_f[39]
  PIN dn_f[3]
    DIRECTION INPUT ;
    USE SIGNAL ;
    PORT
      LAYER M3 ;
        RECT  7.2 43.056 7.218 43.2 ;
    END
  END dn_f[3]
  PIN dn_f[40]
    DIRECTION INPUT ;
    USE SIGNAL ;
    PORT
      LAYER M5 ;
        RECT  11.952 43.008 11.976 43.2 ;
    END
  END dn_f[40]
  PIN dn_f[41]
    DIRECTION INPUT ;
    USE SIGNAL ;
    PORT
      LAYER M3 ;
        RECT  12.096 43.056 12.114 43.2 ;
    END
  END dn_f[41]
  PIN dn_f[42]
    DIRECTION INPUT ;
    USE SIGNAL ;
    PORT
      LAYER M5 ;
        RECT  12.192 43.008 12.216 43.2 ;
    END
  END dn_f[42]
  PIN dn_f[43]
    DIRECTION INPUT ;
    USE SIGNAL ;
    PORT
      LAYER M3 ;
        RECT  12.348 43.056 12.366 43.2 ;
    END
  END dn_f[43]
  PIN dn_f[44]
    DIRECTION INPUT ;
    USE SIGNAL ;
    PORT
      LAYER M5 ;
        RECT  12.48 43.008 12.504 43.2 ;
    END
  END dn_f[44]
  PIN dn_f[45]
    DIRECTION INPUT ;
    USE SIGNAL ;
    PORT
      LAYER M3 ;
        RECT  12.6 43.056 12.618 43.2 ;
    END
  END dn_f[45]
  PIN dn_f[46]
    DIRECTION INPUT ;
    USE SIGNAL ;
    PORT
      LAYER M5 ;
        RECT  12.72 43.008 12.744 43.2 ;
    END
  END dn_f[46]
  PIN dn_f[47]
    DIRECTION INPUT ;
    USE SIGNAL ;
    PORT
      LAYER M3 ;
        RECT  12.852 43.056 12.87 43.2 ;
    END
  END dn_f[47]
  PIN dn_f[48]
    DIRECTION INPUT ;
    USE SIGNAL ;
    PORT
      LAYER M5 ;
        RECT  12.96 43.008 12.984 43.2 ;
    END
  END dn_f[48]
  PIN dn_f[49]
    DIRECTION INPUT ;
    USE SIGNAL ;
    PORT
      LAYER M3 ;
        RECT  13.104 43.056 13.122 43.2 ;
    END
  END dn_f[49]
  PIN dn_f[4]
    DIRECTION INPUT ;
    USE SIGNAL ;
    PORT
      LAYER M5 ;
        RECT  7.344 43.008 7.368 43.2 ;
    END
  END dn_f[4]
  PIN dn_f[50]
    DIRECTION INPUT ;
    USE SIGNAL ;
    PORT
      LAYER M5 ;
        RECT  13.248 43.008 13.272 43.2 ;
    END
  END dn_f[50]
  PIN dn_f[51]
    DIRECTION INPUT ;
    USE SIGNAL ;
    PORT
      LAYER M3 ;
        RECT  13.356 43.056 13.374 43.2 ;
    END
  END dn_f[51]
  PIN dn_f[52]
    DIRECTION INPUT ;
    USE SIGNAL ;
    PORT
      LAYER M5 ;
        RECT  13.488 43.008 13.512 43.2 ;
    END
  END dn_f[52]
  PIN dn_f[53]
    DIRECTION INPUT ;
    USE SIGNAL ;
    PORT
      LAYER M3 ;
        RECT  13.608 43.056 13.626 43.2 ;
    END
  END dn_f[53]
  PIN dn_f[54]
    DIRECTION INPUT ;
    USE SIGNAL ;
    PORT
      LAYER M5 ;
        RECT  13.728 43.008 13.752 43.2 ;
    END
  END dn_f[54]
  PIN dn_f[55]
    DIRECTION INPUT ;
    USE SIGNAL ;
    PORT
      LAYER M3 ;
        RECT  13.896 43.056 13.914 43.2 ;
    END
  END dn_f[55]
  PIN dn_f[56]
    DIRECTION INPUT ;
    USE SIGNAL ;
    PORT
      LAYER M5 ;
        RECT  14.016 43.008 14.04 43.2 ;
    END
  END dn_f[56]
  PIN dn_f[57]
    DIRECTION INPUT ;
    USE SIGNAL ;
    PORT
      LAYER M3 ;
        RECT  14.148 43.056 14.166 43.2 ;
    END
  END dn_f[57]
  PIN dn_f[58]
    DIRECTION INPUT ;
    USE SIGNAL ;
    PORT
      LAYER M5 ;
        RECT  14.256 43.008 14.28 43.2 ;
    END
  END dn_f[58]
  PIN dn_f[59]
    DIRECTION INPUT ;
    USE SIGNAL ;
    PORT
      LAYER M3 ;
        RECT  14.4 43.056 14.418 43.2 ;
    END
  END dn_f[59]
  PIN dn_f[5]
    DIRECTION INPUT ;
    USE SIGNAL ;
    PORT
      LAYER M3 ;
        RECT  7.452 43.056 7.47 43.2 ;
    END
  END dn_f[5]
  PIN dn_f[60]
    DIRECTION INPUT ;
    USE SIGNAL ;
    PORT
      LAYER M5 ;
        RECT  14.496 43.008 14.52 43.2 ;
    END
  END dn_f[60]
  PIN dn_f[61]
    DIRECTION INPUT ;
    USE SIGNAL ;
    PORT
      LAYER M3 ;
        RECT  14.652 43.056 14.67 43.2 ;
    END
  END dn_f[61]
  PIN dn_f[62]
    DIRECTION INPUT ;
    USE SIGNAL ;
    PORT
      LAYER M5 ;
        RECT  14.784 43.008 14.808 43.2 ;
    END
  END dn_f[62]
  PIN dn_f[63]
    DIRECTION INPUT ;
    USE SIGNAL ;
    PORT
      LAYER M3 ;
        RECT  14.904 43.056 14.922 43.2 ;
    END
  END dn_f[63]
  PIN dn_f[64]
    DIRECTION INPUT ;
    USE SIGNAL ;
    PORT
      LAYER M5 ;
        RECT  15.024 43.008 15.048 43.2 ;
    END
  END dn_f[64]
  PIN dn_f[65]
    DIRECTION INPUT ;
    USE SIGNAL ;
    PORT
      LAYER M3 ;
        RECT  15.156 43.056 15.174 43.2 ;
    END
  END dn_f[65]
  PIN dn_f[66]
    DIRECTION INPUT ;
    USE SIGNAL ;
    PORT
      LAYER M5 ;
        RECT  15.312 43.008 15.336 43.2 ;
    END
  END dn_f[66]
  PIN dn_f[67]
    DIRECTION INPUT ;
    USE SIGNAL ;
    PORT
      LAYER M3 ;
        RECT  15.408 43.056 15.426 43.2 ;
    END
  END dn_f[67]
  PIN dn_f[68]
    DIRECTION INPUT ;
    USE SIGNAL ;
    PORT
      LAYER M5 ;
        RECT  15.552 43.008 15.576 43.2 ;
    END
  END dn_f[68]
  PIN dn_f[69]
    DIRECTION INPUT ;
    USE SIGNAL ;
    PORT
      LAYER M3 ;
        RECT  15.66 43.056 15.678 43.2 ;
    END
  END dn_f[69]
  PIN dn_f[6]
    DIRECTION INPUT ;
    USE SIGNAL ;
    PORT
      LAYER M5 ;
        RECT  7.584 43.008 7.608 43.2 ;
    END
  END dn_f[6]
  PIN dn_f[70]
    DIRECTION INPUT ;
    USE SIGNAL ;
    PORT
      LAYER M5 ;
        RECT  15.792 43.008 15.816 43.2 ;
    END
  END dn_f[70]
  PIN dn_f[71]
    DIRECTION INPUT ;
    USE SIGNAL ;
    PORT
      LAYER M3 ;
        RECT  15.948 43.056 15.966 43.2 ;
    END
  END dn_f[71]
  PIN dn_f[72]
    DIRECTION INPUT ;
    USE SIGNAL ;
    PORT
      LAYER M5 ;
        RECT  16.08 43.008 16.104 43.2 ;
    END
  END dn_f[72]
  PIN dn_f[73]
    DIRECTION INPUT ;
    USE SIGNAL ;
    PORT
      LAYER M3 ;
        RECT  16.2 43.056 16.218 43.2 ;
    END
  END dn_f[73]
  PIN dn_f[74]
    DIRECTION INPUT ;
    USE SIGNAL ;
    PORT
      LAYER M5 ;
        RECT  16.32 43.008 16.344 43.2 ;
    END
  END dn_f[74]
  PIN dn_f[75]
    DIRECTION INPUT ;
    USE SIGNAL ;
    PORT
      LAYER M3 ;
        RECT  16.452 43.056 16.47 43.2 ;
    END
  END dn_f[75]
  PIN dn_f[76]
    DIRECTION INPUT ;
    USE SIGNAL ;
    PORT
      LAYER M5 ;
        RECT  16.56 43.008 16.584 43.2 ;
    END
  END dn_f[76]
  PIN dn_f[77]
    DIRECTION INPUT ;
    USE SIGNAL ;
    PORT
      LAYER M3 ;
        RECT  16.704 43.056 16.722 43.2 ;
    END
  END dn_f[77]
  PIN dn_f[78]
    DIRECTION INPUT ;
    USE SIGNAL ;
    PORT
      LAYER M5 ;
        RECT  16.848 43.008 16.872 43.2 ;
    END
  END dn_f[78]
  PIN dn_f[79]
    DIRECTION INPUT ;
    USE SIGNAL ;
    PORT
      LAYER M3 ;
        RECT  16.956 43.056 16.974 43.2 ;
    END
  END dn_f[79]
  PIN dn_f[7]
    DIRECTION INPUT ;
    USE SIGNAL ;
    PORT
      LAYER M3 ;
        RECT  7.704 43.056 7.722 43.2 ;
    END
  END dn_f[7]
  PIN dn_f[80]
    DIRECTION INPUT ;
    USE SIGNAL ;
    PORT
      LAYER M5 ;
        RECT  17.088 43.008 17.112 43.2 ;
    END
  END dn_f[80]
  PIN dn_f[81]
    DIRECTION INPUT ;
    USE SIGNAL ;
    PORT
      LAYER M3 ;
        RECT  17.208 43.056 17.226 43.2 ;
    END
  END dn_f[81]
  PIN dn_f[82]
    DIRECTION INPUT ;
    USE SIGNAL ;
    PORT
      LAYER M5 ;
        RECT  17.328 43.008 17.352 43.2 ;
    END
  END dn_f[82]
  PIN dn_f[83]
    DIRECTION INPUT ;
    USE SIGNAL ;
    PORT
      LAYER M3 ;
        RECT  17.46 43.056 17.478 43.2 ;
    END
  END dn_f[83]
  PIN dn_f[84]
    DIRECTION INPUT ;
    USE SIGNAL ;
    PORT
      LAYER M5 ;
        RECT  17.616 43.008 17.64 43.2 ;
    END
  END dn_f[84]
  PIN dn_f[85]
    DIRECTION INPUT ;
    USE SIGNAL ;
    PORT
      LAYER M3 ;
        RECT  17.748 43.056 17.766 43.2 ;
    END
  END dn_f[85]
  PIN dn_f[86]
    DIRECTION INPUT ;
    USE SIGNAL ;
    PORT
      LAYER M5 ;
        RECT  17.856 43.008 17.88 43.2 ;
    END
  END dn_f[86]
  PIN dn_f[87]
    DIRECTION INPUT ;
    USE SIGNAL ;
    PORT
      LAYER M3 ;
        RECT  18 43.056 18.018 43.2 ;
    END
  END dn_f[87]
  PIN dn_f[88]
    DIRECTION INPUT ;
    USE SIGNAL ;
    PORT
      LAYER M5 ;
        RECT  18.096 43.008 18.12 43.2 ;
    END
  END dn_f[88]
  PIN dn_f[89]
    DIRECTION INPUT ;
    USE SIGNAL ;
    PORT
      LAYER M3 ;
        RECT  18.252 43.056 18.27 43.2 ;
    END
  END dn_f[89]
  PIN dn_f[8]
    DIRECTION INPUT ;
    USE SIGNAL ;
    PORT
      LAYER M5 ;
        RECT  7.824 43.008 7.848 43.2 ;
    END
  END dn_f[8]
  PIN dn_f[90]
    DIRECTION INPUT ;
    USE SIGNAL ;
    PORT
      LAYER M5 ;
        RECT  18.384 43.008 18.408 43.2 ;
    END
  END dn_f[90]
  PIN dn_f[91]
    DIRECTION INPUT ;
    USE SIGNAL ;
    PORT
      LAYER M3 ;
        RECT  18.504 43.056 18.522 43.2 ;
    END
  END dn_f[91]
  PIN dn_f[92]
    DIRECTION INPUT ;
    USE SIGNAL ;
    PORT
      LAYER M5 ;
        RECT  18.624 43.008 18.648 43.2 ;
    END
  END dn_f[92]
  PIN dn_f[93]
    DIRECTION INPUT ;
    USE SIGNAL ;
    PORT
      LAYER M3 ;
        RECT  18.756 43.056 18.774 43.2 ;
    END
  END dn_f[93]
  PIN dn_f[94]
    DIRECTION INPUT ;
    USE SIGNAL ;
    PORT
      LAYER M5 ;
        RECT  18.864 43.008 18.888 43.2 ;
    END
  END dn_f[94]
  PIN dn_f[95]
    DIRECTION INPUT ;
    USE SIGNAL ;
    PORT
      LAYER M3 ;
        RECT  19.008 43.056 19.026 43.2 ;
    END
  END dn_f[95]
  PIN dn_f[96]
    DIRECTION INPUT ;
    USE SIGNAL ;
    PORT
      LAYER M5 ;
        RECT  19.152 43.008 19.176 43.2 ;
    END
  END dn_f[96]
  PIN dn_f[97]
    DIRECTION INPUT ;
    USE SIGNAL ;
    PORT
      LAYER M3 ;
        RECT  19.26 43.056 19.278 43.2 ;
    END
  END dn_f[97]
  PIN dn_f[98]
    DIRECTION INPUT ;
    USE SIGNAL ;
    PORT
      LAYER M5 ;
        RECT  19.392 43.008 19.416 43.2 ;
    END
  END dn_f[98]
  PIN dn_f[99]
    DIRECTION INPUT ;
    USE SIGNAL ;
    PORT
      LAYER M3 ;
        RECT  19.548 43.056 19.566 43.2 ;
    END
  END dn_f[99]
  PIN dn_f[9]
    DIRECTION INPUT ;
    USE SIGNAL ;
    PORT
      LAYER M3 ;
        RECT  7.956 43.056 7.974 43.2 ;
    END
  END dn_f[9]
  PIN dn_jid[0]
    DIRECTION INPUT ;
    USE SIGNAL ;
    PORT
      LAYER M3 ;
        RECT  5.148 43.056 5.166 43.2 ;
    END
  END dn_jid[0]
  PIN dn_jid[1]
    DIRECTION INPUT ;
    USE SIGNAL ;
    PORT
      LAYER M5 ;
        RECT  5.28 43.008 5.304 43.2 ;
    END
  END dn_jid[1]
  PIN dn_jid[2]
    DIRECTION INPUT ;
    USE SIGNAL ;
    PORT
      LAYER M3 ;
        RECT  5.4 43.056 5.418 43.2 ;
    END
  END dn_jid[2]
  PIN dn_jid[3]
    DIRECTION INPUT ;
    USE SIGNAL ;
    PORT
      LAYER M5 ;
        RECT  5.52 43.008 5.544 43.2 ;
    END
  END dn_jid[3]
  PIN dn_jid[4]
    DIRECTION INPUT ;
    USE SIGNAL ;
    PORT
      LAYER M3 ;
        RECT  5.652 43.056 5.67 43.2 ;
    END
  END dn_jid[4]
  PIN dn_jid[5]
    DIRECTION INPUT ;
    USE SIGNAL ;
    PORT
      LAYER M5 ;
        RECT  5.808 43.008 5.832 43.2 ;
    END
  END dn_jid[5]
  PIN dn_jid[6]
    DIRECTION INPUT ;
    USE SIGNAL ;
    PORT
      LAYER M3 ;
        RECT  5.904 43.056 5.922 43.2 ;
    END
  END dn_jid[6]
  PIN dn_jid[7]
    DIRECTION INPUT ;
    USE SIGNAL ;
    PORT
      LAYER M5 ;
        RECT  6.048 43.008 6.072 43.2 ;
    END
  END dn_jid[7]
  PIN dn_kind[0]
    DIRECTION INPUT ;
    USE SIGNAL ;
    PORT
      LAYER M3 ;
        RECT  4.644 43.056 4.662 43.2 ;
    END
  END dn_kind[0]
  PIN dn_kind[1]
    DIRECTION INPUT ;
    USE SIGNAL ;
    PORT
      LAYER M5 ;
        RECT  4.752 43.008 4.776 43.2 ;
    END
  END dn_kind[1]
  PIN dn_kind[2]
    DIRECTION INPUT ;
    USE SIGNAL ;
    PORT
      LAYER M3 ;
        RECT  4.896 43.056 4.914 43.2 ;
    END
  END dn_kind[2]
  PIN dn_kind[3]
    DIRECTION INPUT ;
    USE SIGNAL ;
    PORT
      LAYER M5 ;
        RECT  4.992 43.008 5.016 43.2 ;
    END
  END dn_kind[3]
  PIN dn_st
    DIRECTION INPUT ;
    USE SIGNAL ;
    PORT
      LAYER M5 ;
        RECT  4.512 43.008 4.536 43.2 ;
    END
  END dn_st
  PIN dn_v[0]
    DIRECTION INPUT ;
    USE SIGNAL ;
    PORT
      LAYER M3 ;
        RECT  6.156 43.056 6.174 43.2 ;
    END
  END dn_v[0]
  PIN dn_v[1]
    DIRECTION INPUT ;
    USE SIGNAL ;
    PORT
      LAYER M5 ;
        RECT  6.288 43.008 6.312 43.2 ;
    END
  END dn_v[1]
  PIN dn_v[2]
    DIRECTION INPUT ;
    USE SIGNAL ;
    PORT
      LAYER M3 ;
        RECT  6.444 43.056 6.462 43.2 ;
    END
  END dn_v[2]
  PIN dn_v[3]
    DIRECTION INPUT ;
    USE SIGNAL ;
    PORT
      LAYER M5 ;
        RECT  6.576 43.008 6.6 43.2 ;
    END
  END dn_v[3]
  PIN dn_v[4]
    DIRECTION INPUT ;
    USE SIGNAL ;
    PORT
      LAYER M3 ;
        RECT  6.696 43.056 6.714 43.2 ;
    END
  END dn_v[4]
  PIN o_a2[0]
    DIRECTION OUTPUT ;
    USE SIGNAL ;
    PORT
      LAYER M3 ;
        RECT  16.956 0 16.974 0.144 ;
    END
    PORT
      LAYER M3 ;
        RECT  16.956 0.108 16.974 1.723 ;
    END
  END o_a2[0]
  PIN o_a2[10]
    DIRECTION OUTPUT ;
    USE SIGNAL ;
    PORT
      LAYER M3 ;
        RECT  20.88 0 20.898 0.144 ;
    END
    PORT
      LAYER M3 ;
        RECT  20.88 0.108 20.898 1.723 ;
    END
  END o_a2[10]
  PIN o_a2[11]
    DIRECTION OUTPUT ;
    USE SIGNAL ;
    PORT
      LAYER M5 ;
        RECT  21.264 0 21.288 0.192 ;
    END
  END o_a2[11]
  PIN o_a2[12]
    DIRECTION OUTPUT ;
    USE SIGNAL ;
    PORT
      LAYER M3 ;
        RECT  21.636 0 21.654 0.144 ;
    END
    PORT
      LAYER M3 ;
        RECT  21.636 0.108 21.654 1.723 ;
    END
  END o_a2[12]
  PIN o_a2[13]
    DIRECTION OUTPUT ;
    USE SIGNAL ;
    PORT
      LAYER M5 ;
        RECT  22.032 0 22.056 0.192 ;
    END
  END o_a2[13]
  PIN o_a2[1]
    DIRECTION OUTPUT ;
    USE SIGNAL ;
    PORT
      LAYER M5 ;
        RECT  17.376 0 17.4 0.192 ;
    END
  END o_a2[1]
  PIN o_a2[2]
    DIRECTION OUTPUT ;
    USE SIGNAL ;
    PORT
      LAYER M3 ;
        RECT  17.748 0 17.766 0.144 ;
    END
    PORT
      LAYER M3 ;
        RECT  17.748 0.108 17.766 1.723 ;
    END
  END o_a2[2]
  PIN o_a2[3]
    DIRECTION OUTPUT ;
    USE SIGNAL ;
    PORT
      LAYER M5 ;
        RECT  18.144 0 18.168 0.192 ;
    END
  END o_a2[3]
  PIN o_a2[4]
    DIRECTION OUTPUT ;
    USE SIGNAL ;
    PORT
      LAYER M3 ;
        RECT  18.54 0 18.558 0.144 ;
    END
    PORT
      LAYER M3 ;
        RECT  18.54 0.108 18.558 1.723 ;
    END
  END o_a2[4]
  PIN o_a2[5]
    DIRECTION OUTPUT ;
    USE SIGNAL ;
    PORT
      LAYER M5 ;
        RECT  18.912 0 18.936 0.192 ;
    END
  END o_a2[5]
  PIN o_a2[6]
    DIRECTION OUTPUT ;
    USE SIGNAL ;
    PORT
      LAYER M3 ;
        RECT  19.296 0 19.314 0.144 ;
    END
    PORT
      LAYER M3 ;
        RECT  19.296 0.108 19.314 0.187 ;
    END
  END o_a2[6]
  PIN o_a2[7]
    DIRECTION OUTPUT ;
    USE SIGNAL ;
    PORT
      LAYER M5 ;
        RECT  19.68 0 19.704 0.192 ;
    END
  END o_a2[7]
  PIN o_a2[8]
    DIRECTION OUTPUT ;
    USE SIGNAL ;
    PORT
      LAYER M3 ;
        RECT  20.088 0 20.106 0.144 ;
    END
    PORT
      LAYER M3 ;
        RECT  20.088 0.108 20.106 0.187 ;
    END
  END o_a2[8]
  PIN o_a2[9]
    DIRECTION OUTPUT ;
    USE SIGNAL ;
    PORT
      LAYER M5 ;
        RECT  20.496 0 20.52 0.192 ;
    END
  END o_a2[9]
  PIN o_a[0]
    DIRECTION OUTPUT ;
    USE SIGNAL ;
    PORT
      LAYER M5 ;
        RECT  4.896 0 4.92 0.192 ;
    END
  END o_a[0]
  PIN o_a[10]
    DIRECTION OUTPUT ;
    USE SIGNAL ;
    PORT
      LAYER M5 ;
        RECT  8.784 0 8.808 0.192 ;
    END
  END o_a[10]
  PIN o_a[11]
    DIRECTION OUTPUT ;
    USE SIGNAL ;
    PORT
      LAYER M3 ;
        RECT  9.18 0 9.198 0.144 ;
    END
    PORT
      LAYER M3 ;
        RECT  9.18 0.108 9.198 1.723 ;
    END
  END o_a[11]
  PIN o_a[12]
    DIRECTION OUTPUT ;
    USE SIGNAL ;
    PORT
      LAYER M5 ;
        RECT  9.552 0 9.576 0.192 ;
    END
  END o_a[12]
  PIN o_a[13]
    DIRECTION OUTPUT ;
    USE SIGNAL ;
    PORT
      LAYER M3 ;
        RECT  9.972 0 9.99 0.144 ;
    END
    PORT
      LAYER M3 ;
        RECT  9.972 0.108 9.99 0.139 ;
    END
  END o_a[13]
  PIN o_a[1]
    DIRECTION OUTPUT ;
    USE SIGNAL ;
    PORT
      LAYER M3 ;
        RECT  5.292 0 5.31 0.144 ;
    END
    PORT
      LAYER M3 ;
        RECT  5.292 0.108 5.31 1.723 ;
    END
  END o_a[1]
  PIN o_a[2]
    DIRECTION OUTPUT ;
    USE SIGNAL ;
    PORT
      LAYER M5 ;
        RECT  5.664 0 5.688 0.192 ;
    END
  END o_a[2]
  PIN o_a[3]
    DIRECTION OUTPUT ;
    USE SIGNAL ;
    PORT
      LAYER M3 ;
        RECT  6.048 0 6.066 0.144 ;
    END
    PORT
      LAYER M3 ;
        RECT  6.048 0.108 6.066 1.723 ;
    END
  END o_a[3]
  PIN o_a[4]
    DIRECTION OUTPUT ;
    USE SIGNAL ;
    PORT
      LAYER M5 ;
        RECT  6.432 0 6.456 0.192 ;
    END
  END o_a[4]
  PIN o_a[5]
    DIRECTION OUTPUT ;
    USE SIGNAL ;
    PORT
      LAYER M3 ;
        RECT  6.84 0 6.858 0.144 ;
    END
    PORT
      LAYER M3 ;
        RECT  6.84 0.108 6.858 1.723 ;
    END
  END o_a[5]
  PIN o_a[6]
    DIRECTION OUTPUT ;
    USE SIGNAL ;
    PORT
      LAYER M5 ;
        RECT  7.248 0 7.272 0.192 ;
    END
  END o_a[6]
  PIN o_a[7]
    DIRECTION OUTPUT ;
    USE SIGNAL ;
    PORT
      LAYER M3 ;
        RECT  7.632 0 7.65 0.144 ;
    END
    PORT
      LAYER M3 ;
        RECT  7.632 0.108 7.65 1.723 ;
    END
  END o_a[7]
  PIN o_a[8]
    DIRECTION OUTPUT ;
    USE SIGNAL ;
    PORT
      LAYER M5 ;
        RECT  8.016 0 8.04 0.192 ;
    END
  END o_a[8]
  PIN o_a[9]
    DIRECTION OUTPUT ;
    USE SIGNAL ;
    PORT
      LAYER M3 ;
        RECT  8.388 0 8.406 0.144 ;
    END
    PORT
      LAYER M3 ;
        RECT  8.388 0.108 8.406 1.723 ;
    END
  END o_a[9]
  PIN o_alive
    DIRECTION OUTPUT ;
    USE SIGNAL ;
    PORT
      LAYER M3 ;
        RECT  23.22 0 23.238 0.144 ;
    END
    PORT
      LAYER M3 ;
        RECT  23.22 0.108 23.238 1.723 ;
    END
  END o_alive
  PIN o_den
    DIRECTION OUTPUT ;
    USE SIGNAL ;
    PORT
      LAYER M5 ;
        RECT  23.568 0 23.592 0.192 ;
    END
  END o_den
  PIN o_fo
    DIRECTION OUTPUT ;
    USE SIGNAL ;
    PORT
      LAYER M5 ;
        RECT  22.8 0 22.824 0.192 ;
    END
  END o_fo
  PIN o_fu
    DIRECTION OUTPUT ;
    USE SIGNAL ;
    PORT
      LAYER M3 ;
        RECT  22.428 0 22.446 0.144 ;
    END
    PORT
      LAYER M3 ;
        RECT  22.428 0.108 22.446 1.723 ;
    END
  END o_fu
  PIN o_m[0]
    DIRECTION OUTPUT ;
    USE SIGNAL ;
    PORT
      LAYER M5 ;
        RECT  10.368 0 10.392 0.192 ;
    END
  END o_m[0]
  PIN o_m[10]
    DIRECTION OUTPUT ;
    USE SIGNAL ;
    PORT
      LAYER M5 ;
        RECT  14.256 0 14.28 0.192 ;
    END
  END o_m[10]
  PIN o_m[11]
    DIRECTION OUTPUT ;
    USE SIGNAL ;
    PORT
      LAYER M3 ;
        RECT  14.616 0 14.634 0.144 ;
    END
    PORT
      LAYER M3 ;
        RECT  14.616 0.108 14.634 1.723 ;
    END
  END o_m[11]
  PIN o_m[12]
    DIRECTION OUTPUT ;
    USE SIGNAL ;
    PORT
      LAYER M5 ;
        RECT  15.024 0 15.048 0.192 ;
    END
  END o_m[12]
  PIN o_m[13]
    DIRECTION OUTPUT ;
    USE SIGNAL ;
    PORT
      LAYER M3 ;
        RECT  15.408 0 15.426 0.144 ;
    END
    PORT
      LAYER M3 ;
        RECT  15.408 0.108 15.426 1.723 ;
    END
  END o_m[13]
  PIN o_m[14]
    DIRECTION OUTPUT ;
    USE SIGNAL ;
    PORT
      LAYER M5 ;
        RECT  15.792 0 15.816 0.192 ;
    END
  END o_m[14]
  PIN o_m[15]
    DIRECTION OUTPUT ;
    USE SIGNAL ;
    PORT
      LAYER M3 ;
        RECT  16.2 0 16.218 0.144 ;
    END
    PORT
      LAYER M3 ;
        RECT  16.2 0.108 16.218 1.723 ;
    END
  END o_m[15]
  PIN o_m[1]
    DIRECTION OUTPUT ;
    USE SIGNAL ;
    PORT
      LAYER M3 ;
        RECT  10.728 0 10.746 0.144 ;
    END
    PORT
      LAYER M3 ;
        RECT  10.728 0.108 10.746 0.139 ;
    END
  END o_m[1]
  PIN o_m[2]
    DIRECTION OUTPUT ;
    USE SIGNAL ;
    PORT
      LAYER M5 ;
        RECT  11.136 0 11.16 0.192 ;
    END
  END o_m[2]
  PIN o_m[3]
    DIRECTION OUTPUT ;
    USE SIGNAL ;
    PORT
      LAYER M3 ;
        RECT  11.52 0 11.538 0.144 ;
    END
    PORT
      LAYER M3 ;
        RECT  11.52 0.108 11.538 1.723 ;
    END
  END o_m[3]
  PIN o_m[4]
    DIRECTION OUTPUT ;
    USE SIGNAL ;
    PORT
      LAYER M5 ;
        RECT  11.904 0 11.928 0.192 ;
    END
  END o_m[4]
  PIN o_m[5]
    DIRECTION OUTPUT ;
    USE SIGNAL ;
    PORT
      LAYER M3 ;
        RECT  12.312 0 12.33 0.144 ;
    END
    PORT
      LAYER M3 ;
        RECT  12.312 0.108 12.33 1.723 ;
    END
  END o_m[5]
  PIN o_m[6]
    DIRECTION OUTPUT ;
    USE SIGNAL ;
    PORT
      LAYER M5 ;
        RECT  12.672 0 12.696 0.192 ;
    END
  END o_m[6]
  PIN o_m[7]
    DIRECTION OUTPUT ;
    USE SIGNAL ;
    PORT
      LAYER M3 ;
        RECT  13.068 0 13.086 0.144 ;
    END
    PORT
      LAYER M3 ;
        RECT  13.068 0.108 13.086 1.723 ;
    END
  END o_m[7]
  PIN o_m[8]
    DIRECTION OUTPUT ;
    USE SIGNAL ;
    PORT
      LAYER M5 ;
        RECT  13.44 0 13.464 0.192 ;
    END
  END o_m[8]
  PIN o_m[9]
    DIRECTION OUTPUT ;
    USE SIGNAL ;
    PORT
      LAYER M3 ;
        RECT  13.86 0 13.878 0.144 ;
    END
    PORT
      LAYER M3 ;
        RECT  13.86 0.108 13.878 1.723 ;
    END
  END o_m[9]
  PIN o_rdy
    DIRECTION OUTPUT ;
    USE SIGNAL ;
    PORT
      LAYER M3 ;
        RECT  23.976 0 23.994 0.144 ;
    END
    PORT
      LAYER M3 ;
        RECT  23.976 0.108 23.994 1.723 ;
    END
  END o_rdy
  PIN o_rjid[0]
    DIRECTION OUTPUT ;
    USE SIGNAL ;
    PORT
      LAYER M5 ;
        RECT  24.384 0 24.408 0.192 ;
    END
  END o_rjid[0]
  PIN o_rjid[1]
    DIRECTION OUTPUT ;
    USE SIGNAL ;
    PORT
      LAYER M3 ;
        RECT  24.768 0 24.786 0.144 ;
    END
    PORT
      LAYER M3 ;
        RECT  24.768 0.108 24.786 1.723 ;
    END
  END o_rjid[1]
  PIN o_rjid[2]
    DIRECTION OUTPUT ;
    USE SIGNAL ;
    PORT
      LAYER M5 ;
        RECT  25.152 0 25.176 0.192 ;
    END
  END o_rjid[2]
  PIN o_rjid[3]
    DIRECTION OUTPUT ;
    USE SIGNAL ;
    PORT
      LAYER M3 ;
        RECT  25.524 0 25.542 0.144 ;
    END
    PORT
      LAYER M3 ;
        RECT  25.524 0.108 25.542 1.723 ;
    END
  END o_rjid[3]
  PIN o_rjid[4]
    DIRECTION OUTPUT ;
    USE SIGNAL ;
    PORT
      LAYER M5 ;
        RECT  25.92 0 25.944 0.192 ;
    END
  END o_rjid[4]
  PIN o_rjid[5]
    DIRECTION OUTPUT ;
    USE SIGNAL ;
    PORT
      LAYER M3 ;
        RECT  26.316 0 26.334 0.144 ;
    END
    PORT
      LAYER M3 ;
        RECT  26.316 0.108 26.334 1.723 ;
    END
  END o_rjid[5]
  PIN o_rjid[6]
    DIRECTION OUTPUT ;
    USE SIGNAL ;
    PORT
      LAYER M5 ;
        RECT  26.688 0 26.712 0.192 ;
    END
  END o_rjid[6]
  PIN o_rjid[7]
    DIRECTION OUTPUT ;
    USE SIGNAL ;
    PORT
      LAYER M3 ;
        RECT  27.108 0 27.126 0.144 ;
    END
    PORT
      LAYER M3 ;
        RECT  27.108 0.108 27.126 1.723 ;
    END
  END o_rjid[7]
  PIN o_v
    DIRECTION OUTPUT ;
    USE SIGNAL ;
    PORT
      LAYER M3 ;
        RECT  4.5 0 4.518 0.144 ;
    END
    PORT
      LAYER M3 ;
        RECT  4.5 0.108 4.518 1.723 ;
    END
  END o_v
  PIN o_v2
    DIRECTION OUTPUT ;
    USE SIGNAL ;
    PORT
      LAYER M5 ;
        RECT  16.56 0 16.584 0.192 ;
    END
  END o_v2
  PIN rst
    DIRECTION INPUT ;
    USE SIGNAL ;
    PORT
      LAYER M3 ;
        RECT  4.392 43.056 4.41 43.2 ;
    END
  END rst
  PIN xa_f[0]
    DIRECTION INPUT ;
    USE SIGNAL ;
    PORT
      LAYER M4 ;
        RECT  0 9.12 0.192 9.144 ;
    END
    PORT
      LAYER M4 ;
        RECT  0.156 9.12 2.408 9.144 ;
    END
  END xa_f[0]
  PIN xa_f[10]
    DIRECTION INPUT ;
    USE SIGNAL ;
    PORT
      LAYER M4 ;
        RECT  0 28.32 0.192 28.344 ;
    END
    PORT
      LAYER M4 ;
        RECT  0.156 28.32 2.408 28.344 ;
    END
  END xa_f[10]
  PIN xa_f[11]
    DIRECTION INPUT ;
    USE SIGNAL ;
    PORT
      LAYER M4 ;
        RECT  0 30.24 0.192 30.264 ;
    END
    PORT
      LAYER M4 ;
        RECT  0.156 30.24 2.408 30.264 ;
    END
  END xa_f[11]
  PIN xa_f[12]
    DIRECTION INPUT ;
    USE SIGNAL ;
    PORT
      LAYER M4 ;
        RECT  0 32.16 0.192 32.184 ;
    END
    PORT
      LAYER M4 ;
        RECT  0.156 32.16 2.408 32.184 ;
    END
  END xa_f[12]
  PIN xa_f[13]
    DIRECTION INPUT ;
    USE SIGNAL ;
    PORT
      LAYER M4 ;
        RECT  0 34.08 0.192 34.104 ;
    END
    PORT
      LAYER M4 ;
        RECT  0.156 34.08 2.408 34.104 ;
    END
  END xa_f[13]
  PIN xa_f[14]
    DIRECTION INPUT ;
    USE SIGNAL ;
    PORT
      LAYER M4 ;
        RECT  0 36 0.192 36.024 ;
    END
    PORT
      LAYER M4 ;
        RECT  0.156 36 2.408 36.024 ;
    END
  END xa_f[14]
  PIN xa_f[15]
    DIRECTION INPUT ;
    USE SIGNAL ;
    PORT
      LAYER M4 ;
        RECT  0 37.92 0.192 37.944 ;
    END
    PORT
      LAYER M4 ;
        RECT  0.156 37.92 2.408 37.944 ;
    END
  END xa_f[15]
  PIN xa_f[1]
    DIRECTION INPUT ;
    USE SIGNAL ;
    PORT
      LAYER M4 ;
        RECT  0 11.04 0.192 11.064 ;
    END
    PORT
      LAYER M4 ;
        RECT  0.156 11.04 2.408 11.064 ;
    END
  END xa_f[1]
  PIN xa_f[2]
    DIRECTION INPUT ;
    USE SIGNAL ;
    PORT
      LAYER M4 ;
        RECT  0 12.96 0.192 12.984 ;
    END
    PORT
      LAYER M4 ;
        RECT  0.156 12.96 2.408 12.984 ;
    END
  END xa_f[2]
  PIN xa_f[3]
    DIRECTION INPUT ;
    USE SIGNAL ;
    PORT
      LAYER M4 ;
        RECT  0 14.88 0.192 14.904 ;
    END
    PORT
      LAYER M4 ;
        RECT  0.156 14.88 2.408 14.904 ;
    END
  END xa_f[3]
  PIN xa_f[4]
    DIRECTION INPUT ;
    USE SIGNAL ;
    PORT
      LAYER M4 ;
        RECT  0 16.8 0.192 16.824 ;
    END
    PORT
      LAYER M4 ;
        RECT  0.156 16.8 2.408 16.824 ;
    END
  END xa_f[4]
  PIN xa_f[5]
    DIRECTION INPUT ;
    USE SIGNAL ;
    PORT
      LAYER M4 ;
        RECT  0 18.72 0.192 18.744 ;
    END
    PORT
      LAYER M4 ;
        RECT  0.156 18.72 2.408 18.744 ;
    END
  END xa_f[5]
  PIN xa_f[6]
    DIRECTION INPUT ;
    USE SIGNAL ;
    PORT
      LAYER M4 ;
        RECT  0 20.64 0.192 20.664 ;
    END
    PORT
      LAYER M4 ;
        RECT  0.156 20.64 2.408 20.664 ;
    END
  END xa_f[6]
  PIN xa_f[7]
    DIRECTION INPUT ;
    USE SIGNAL ;
    PORT
      LAYER M4 ;
        RECT  0 22.56 0.192 22.584 ;
    END
    PORT
      LAYER M4 ;
        RECT  0.156 22.56 2.408 22.584 ;
    END
  END xa_f[7]
  PIN xa_f[8]
    DIRECTION INPUT ;
    USE SIGNAL ;
    PORT
      LAYER M4 ;
        RECT  0 24.48 0.192 24.504 ;
    END
    PORT
      LAYER M4 ;
        RECT  0.156 24.48 2.408 24.504 ;
    END
  END xa_f[8]
  PIN xa_f[9]
    DIRECTION INPUT ;
    USE SIGNAL ;
    PORT
      LAYER M4 ;
        RECT  0 26.4 0.192 26.424 ;
    END
    PORT
      LAYER M4 ;
        RECT  0.156 26.4 2.408 26.424 ;
    END
  END xa_f[9]
  PIN xa_v
    DIRECTION OUTPUT ;
    USE SIGNAL ;
    PORT
      LAYER M4 ;
        RECT  0 5.28 0.192 5.304 ;
    END
    PORT
      LAYER M4 ;
        RECT  0.156 5.28 2.408 5.304 ;
    END
  END xa_v
  PIN xa_vi
    DIRECTION INPUT ;
    USE SIGNAL ;
    PORT
      LAYER M4 ;
        RECT  0 7.2 0.192 7.224 ;
    END
    PORT
      LAYER M4 ;
        RECT  0.156 7.2 2.408 7.224 ;
    END
  END xa_vi
  PIN xb_f
    DIRECTION INPUT ;
    USE SIGNAL ;
    PORT
      LAYER M5 ;
        RECT  51.648 0 51.672 0.192 ;
    END
  END xb_f
  PIN xb_m[0]
    DIRECTION INPUT ;
    USE SIGNAL ;
    PORT
      LAYER M5 ;
        RECT  45.408 0 45.432 0.192 ;
    END
  END xb_m[0]
  PIN xb_m[10]
    DIRECTION INPUT ;
    USE SIGNAL ;
    PORT
      LAYER M5 ;
        RECT  49.296 0 49.32 0.192 ;
    END
  END xb_m[10]
  PIN xb_m[11]
    DIRECTION INPUT ;
    USE SIGNAL ;
    PORT
      LAYER M3 ;
        RECT  49.68 0 49.698 0.144 ;
    END
    PORT
      LAYER M3 ;
        RECT  49.68 0.108 49.698 1.723 ;
    END
  END xb_m[11]
  PIN xb_m[12]
    DIRECTION INPUT ;
    USE SIGNAL ;
    PORT
      LAYER M5 ;
        RECT  50.064 0 50.088 0.192 ;
    END
  END xb_m[12]
  PIN xb_m[13]
    DIRECTION INPUT ;
    USE SIGNAL ;
    PORT
      LAYER M3 ;
        RECT  50.472 0 50.49 0.144 ;
    END
    PORT
      LAYER M3 ;
        RECT  50.472 0.108 50.49 1.723 ;
    END
  END xb_m[13]
  PIN xb_m[14]
    DIRECTION INPUT ;
    USE SIGNAL ;
    PORT
      LAYER M5 ;
        RECT  50.832 0 50.856 0.192 ;
    END
  END xb_m[14]
  PIN xb_m[15]
    DIRECTION INPUT ;
    USE SIGNAL ;
    PORT
      LAYER M3 ;
        RECT  51.264 0 51.282 0.144 ;
    END
    PORT
      LAYER M3 ;
        RECT  51.264 0.108 51.282 1.723 ;
    END
  END xb_m[15]
  PIN xb_m[1]
    DIRECTION INPUT ;
    USE SIGNAL ;
    PORT
      LAYER M3 ;
        RECT  45.792 0 45.81 0.144 ;
    END
    PORT
      LAYER M3 ;
        RECT  45.792 0.108 45.81 0.571 ;
    END
  END xb_m[1]
  PIN xb_m[2]
    DIRECTION INPUT ;
    USE SIGNAL ;
    PORT
      LAYER M5 ;
        RECT  46.176 0 46.2 0.192 ;
    END
  END xb_m[2]
  PIN xb_m[3]
    DIRECTION INPUT ;
    USE SIGNAL ;
    PORT
      LAYER M3 ;
        RECT  46.584 0 46.602 0.144 ;
    END
    PORT
      LAYER M3 ;
        RECT  46.584 0.108 46.602 0.571 ;
    END
  END xb_m[3]
  PIN xb_m[4]
    DIRECTION INPUT ;
    USE SIGNAL ;
    PORT
      LAYER M5 ;
        RECT  46.944 0 46.968 0.192 ;
    END
  END xb_m[4]
  PIN xb_m[5]
    DIRECTION INPUT ;
    USE SIGNAL ;
    PORT
      LAYER M3 ;
        RECT  47.34 0 47.358 0.144 ;
    END
    PORT
      LAYER M3 ;
        RECT  47.34 0.108 47.358 1.723 ;
    END
  END xb_m[5]
  PIN xb_m[6]
    DIRECTION INPUT ;
    USE SIGNAL ;
    PORT
      LAYER M5 ;
        RECT  47.76 0 47.784 0.192 ;
    END
  END xb_m[6]
  PIN xb_m[7]
    DIRECTION INPUT ;
    USE SIGNAL ;
    PORT
      LAYER M3 ;
        RECT  48.132 0 48.15 0.144 ;
    END
    PORT
      LAYER M3 ;
        RECT  48.132 0.108 48.15 1.723 ;
    END
  END xb_m[7]
  PIN xb_m[8]
    DIRECTION INPUT ;
    USE SIGNAL ;
    PORT
      LAYER M5 ;
        RECT  48.528 0 48.552 0.192 ;
    END
  END xb_m[8]
  PIN xb_m[9]
    DIRECTION INPUT ;
    USE SIGNAL ;
    PORT
      LAYER M3 ;
        RECT  48.924 0 48.942 0.144 ;
    END
    PORT
      LAYER M3 ;
        RECT  48.924 0.108 48.942 1.723 ;
    END
  END xb_m[9]
  PIN xb_v
    DIRECTION OUTPUT ;
    USE SIGNAL ;
    PORT
      LAYER M5 ;
        RECT  27.504 0 27.528 0.192 ;
    END
  END xb_v
  PIN xb_vi
    DIRECTION INPUT ;
    USE SIGNAL ;
    PORT
      LAYER M5 ;
        RECT  44.64 0 44.664 0.192 ;
    END
  END xb_vi
  PIN xb_wi
    DIRECTION INPUT ;
    USE SIGNAL ;
    PORT
      LAYER M3 ;
        RECT  45 0 45.018 0.144 ;
    END
    PORT
      LAYER M3 ;
        RECT  45 0.108 45.018 0.571 ;
    END
  END xb_wi
  PIN xq_f[0]
    DIRECTION INPUT ;
    USE SIGNAL ;
    PORT
      LAYER M4 ;
        RECT  55.968 23.76 56.16 23.784 ;
    END
    PORT
      LAYER M4 ;
        RECT  54.709 23.76 55.98 23.784 ;
    END
  END xq_f[0]
  PIN xq_f[1]
    DIRECTION INPUT ;
    USE SIGNAL ;
    PORT
      LAYER M4 ;
        RECT  55.968 28.08 56.16 28.104 ;
    END
    PORT
      LAYER M4 ;
        RECT  54.529 28.08 55.98 28.104 ;
    END
  END xq_f[1]
  PIN xq_f[2]
    DIRECTION INPUT ;
    USE SIGNAL ;
    PORT
      LAYER M4 ;
        RECT  55.968 32.4 56.16 32.424 ;
    END
    PORT
      LAYER M4 ;
        RECT  54.673 32.4 55.98 32.424 ;
    END
  END xq_f[2]
  PIN xq_f[3]
    DIRECTION INPUT ;
    USE SIGNAL ;
    PORT
      LAYER M4 ;
        RECT  55.968 36.72 56.16 36.744 ;
    END
    PORT
      LAYER M4 ;
        RECT  54.673 36.72 55.98 36.744 ;
    END
  END xq_f[3]
  PIN xq_v[0]
    DIRECTION OUTPUT ;
    USE SIGNAL ;
    PORT
      LAYER M4 ;
        RECT  55.968 6.48 56.16 6.504 ;
    END
    PORT
      LAYER M4 ;
        RECT  54.709 6.48 55.98 6.504 ;
    END
  END xq_v[0]
  PIN xq_v[1]
    DIRECTION OUTPUT ;
    USE SIGNAL ;
    PORT
      LAYER M4 ;
        RECT  55.968 10.8 56.16 10.824 ;
    END
    PORT
      LAYER M4 ;
        RECT  55.249 10.8 55.98 10.824 ;
    END
  END xq_v[1]
  PIN xq_vi[0]
    DIRECTION INPUT ;
    USE SIGNAL ;
    PORT
      LAYER M4 ;
        RECT  55.968 15.12 56.16 15.144 ;
    END
    PORT
      LAYER M4 ;
        RECT  54.529 15.12 55.98 15.144 ;
    END
  END xq_vi[0]
  PIN xq_vi[1]
    DIRECTION INPUT ;
    USE SIGNAL ;
    PORT
      LAYER M4 ;
        RECT  55.968 19.44 56.16 19.464 ;
    END
    PORT
      LAYER M4 ;
        RECT  54.097 19.44 55.98 19.464 ;
    END
  END xq_vi[1]
  PIN xw_cfg[0]
    DIRECTION OUTPUT ;
    USE SIGNAL ;
    PORT
      LAYER M5 ;
        RECT  29.04 0 29.064 0.192 ;
    END
  END xw_cfg[0]
  PIN xw_cfg[10]
    DIRECTION OUTPUT ;
    USE SIGNAL ;
    PORT
      LAYER M5 ;
        RECT  32.928 0 32.952 0.192 ;
    END
  END xw_cfg[10]
  PIN xw_cfg[11]
    DIRECTION OUTPUT ;
    USE SIGNAL ;
    PORT
      LAYER M3 ;
        RECT  33.336 0 33.354 0.144 ;
    END
    PORT
      LAYER M3 ;
        RECT  33.336 0.108 33.354 1.723 ;
    END
  END xw_cfg[11]
  PIN xw_cfg[12]
    DIRECTION OUTPUT ;
    USE SIGNAL ;
    PORT
      LAYER M5 ;
        RECT  33.696 0 33.72 0.192 ;
    END
  END xw_cfg[12]
  PIN xw_cfg[13]
    DIRECTION OUTPUT ;
    USE SIGNAL ;
    PORT
      LAYER M3 ;
        RECT  34.092 0 34.11 0.144 ;
    END
    PORT
      LAYER M3 ;
        RECT  34.092 0.108 34.11 1.723 ;
    END
  END xw_cfg[13]
  PIN xw_cfg[14]
    DIRECTION OUTPUT ;
    USE SIGNAL ;
    PORT
      LAYER M5 ;
        RECT  34.512 0 34.536 0.192 ;
    END
  END xw_cfg[14]
  PIN xw_cfg[15]
    DIRECTION OUTPUT ;
    USE SIGNAL ;
    PORT
      LAYER M3 ;
        RECT  34.884 0 34.902 0.144 ;
    END
    PORT
      LAYER M3 ;
        RECT  34.884 0.108 34.902 1.723 ;
    END
  END xw_cfg[15]
  PIN xw_cfg[16]
    DIRECTION OUTPUT ;
    USE SIGNAL ;
    PORT
      LAYER M5 ;
        RECT  35.28 0 35.304 0.192 ;
    END
  END xw_cfg[16]
  PIN xw_cfg[17]
    DIRECTION OUTPUT ;
    USE SIGNAL ;
    PORT
      LAYER M3 ;
        RECT  35.676 0 35.694 0.144 ;
    END
    PORT
      LAYER M3 ;
        RECT  35.676 0.108 35.694 1.723 ;
    END
  END xw_cfg[17]
  PIN xw_cfg[18]
    DIRECTION OUTPUT ;
    USE SIGNAL ;
    PORT
      LAYER M5 ;
        RECT  36.048 0 36.072 0.192 ;
    END
  END xw_cfg[18]
  PIN xw_cfg[19]
    DIRECTION OUTPUT ;
    USE SIGNAL ;
    PORT
      LAYER M3 ;
        RECT  36.432 0 36.45 0.144 ;
    END
    PORT
      LAYER M3 ;
        RECT  36.432 0.108 36.45 1.723 ;
    END
  END xw_cfg[19]
  PIN xw_cfg[1]
    DIRECTION OUTPUT ;
    USE SIGNAL ;
    PORT
      LAYER M3 ;
        RECT  29.448 0 29.466 0.144 ;
    END
    PORT
      LAYER M3 ;
        RECT  29.448 0.108 29.466 1.723 ;
    END
  END xw_cfg[1]
  PIN xw_cfg[20]
    DIRECTION OUTPUT ;
    USE SIGNAL ;
    PORT
      LAYER M5 ;
        RECT  36.816 0 36.84 0.192 ;
    END
  END xw_cfg[20]
  PIN xw_cfg[21]
    DIRECTION OUTPUT ;
    USE SIGNAL ;
    PORT
      LAYER M3 ;
        RECT  37.224 0 37.242 0.144 ;
    END
    PORT
      LAYER M3 ;
        RECT  37.224 0.108 37.242 1.723 ;
    END
  END xw_cfg[21]
  PIN xw_cfg[22]
    DIRECTION OUTPUT ;
    USE SIGNAL ;
    PORT
      LAYER M5 ;
        RECT  37.632 0 37.656 0.192 ;
    END
  END xw_cfg[22]
  PIN xw_cfg[23]
    DIRECTION OUTPUT ;
    USE SIGNAL ;
    PORT
      LAYER M3 ;
        RECT  38.016 0 38.034 0.144 ;
    END
    PORT
      LAYER M3 ;
        RECT  38.016 0.108 38.034 1.723 ;
    END
  END xw_cfg[23]
  PIN xw_cfg[24]
    DIRECTION OUTPUT ;
    USE SIGNAL ;
    PORT
      LAYER M5 ;
        RECT  38.4 0 38.424 0.192 ;
    END
  END xw_cfg[24]
  PIN xw_cfg[25]
    DIRECTION OUTPUT ;
    USE SIGNAL ;
    PORT
      LAYER M3 ;
        RECT  38.772 0 38.79 0.144 ;
    END
    PORT
      LAYER M3 ;
        RECT  38.772 0.108 38.79 1.723 ;
    END
  END xw_cfg[25]
  PIN xw_cfg[26]
    DIRECTION OUTPUT ;
    USE SIGNAL ;
    PORT
      LAYER M5 ;
        RECT  39.168 0 39.192 0.192 ;
    END
  END xw_cfg[26]
  PIN xw_cfg[27]
    DIRECTION OUTPUT ;
    USE SIGNAL ;
    PORT
      LAYER M3 ;
        RECT  39.564 0 39.582 0.144 ;
    END
    PORT
      LAYER M3 ;
        RECT  39.564 0.108 39.582 1.723 ;
    END
  END xw_cfg[27]
  PIN xw_cfg[28]
    DIRECTION OUTPUT ;
    USE SIGNAL ;
    PORT
      LAYER M5 ;
        RECT  39.936 0 39.96 0.192 ;
    END
  END xw_cfg[28]
  PIN xw_cfg[29]
    DIRECTION OUTPUT ;
    USE SIGNAL ;
    PORT
      LAYER M3 ;
        RECT  40.356 0 40.374 0.144 ;
    END
    PORT
      LAYER M3 ;
        RECT  40.356 0.108 40.374 1.723 ;
    END
  END xw_cfg[29]
  PIN xw_cfg[2]
    DIRECTION OUTPUT ;
    USE SIGNAL ;
    PORT
      LAYER M5 ;
        RECT  29.808 0 29.832 0.192 ;
    END
  END xw_cfg[2]
  PIN xw_cfg[30]
    DIRECTION OUTPUT ;
    USE SIGNAL ;
    PORT
      LAYER M5 ;
        RECT  40.704 0 40.728 0.192 ;
    END
  END xw_cfg[30]
  PIN xw_cfg[31]
    DIRECTION OUTPUT ;
    USE SIGNAL ;
    PORT
      LAYER M3 ;
        RECT  41.112 0 41.13 0.144 ;
    END
    PORT
      LAYER M3 ;
        RECT  41.112 0.108 41.13 1.723 ;
    END
  END xw_cfg[31]
  PIN xw_cfg[32]
    DIRECTION OUTPUT ;
    USE SIGNAL ;
    PORT
      LAYER M5 ;
        RECT  41.52 0 41.544 0.192 ;
    END
  END xw_cfg[32]
  PIN xw_cfg[33]
    DIRECTION OUTPUT ;
    USE SIGNAL ;
    PORT
      LAYER M3 ;
        RECT  41.904 0 41.922 0.144 ;
    END
    PORT
      LAYER M3 ;
        RECT  41.904 0.108 41.922 1.723 ;
    END
  END xw_cfg[33]
  PIN xw_cfg[34]
    DIRECTION OUTPUT ;
    USE SIGNAL ;
    PORT
      LAYER M5 ;
        RECT  42.288 0 42.312 0.192 ;
    END
  END xw_cfg[34]
  PIN xw_cfg[35]
    DIRECTION OUTPUT ;
    USE SIGNAL ;
    PORT
      LAYER M3 ;
        RECT  42.66 0 42.678 0.144 ;
    END
    PORT
      LAYER M3 ;
        RECT  42.66 0.108 42.678 1.723 ;
    END
  END xw_cfg[35]
  PIN xw_cfg[36]
    DIRECTION OUTPUT ;
    USE SIGNAL ;
    PORT
      LAYER M5 ;
        RECT  43.056 0 43.08 0.192 ;
    END
  END xw_cfg[36]
  PIN xw_cfg[37]
    DIRECTION OUTPUT ;
    USE SIGNAL ;
    PORT
      LAYER M3 ;
        RECT  43.452 0 43.47 0.144 ;
    END
    PORT
      LAYER M3 ;
        RECT  43.452 0.108 43.47 1.723 ;
    END
  END xw_cfg[37]
  PIN xw_cfg[38]
    DIRECTION OUTPUT ;
    USE SIGNAL ;
    PORT
      LAYER M5 ;
        RECT  43.824 0 43.848 0.192 ;
    END
  END xw_cfg[38]
  PIN xw_cfg[39]
    DIRECTION OUTPUT ;
    USE SIGNAL ;
    PORT
      LAYER M3 ;
        RECT  44.244 0 44.262 0.144 ;
    END
    PORT
      LAYER M3 ;
        RECT  44.244 0.108 44.262 0.571 ;
    END
  END xw_cfg[39]
  PIN xw_cfg[3]
    DIRECTION OUTPUT ;
    USE SIGNAL ;
    PORT
      LAYER M3 ;
        RECT  30.204 0 30.222 0.144 ;
    END
    PORT
      LAYER M3 ;
        RECT  30.204 0.108 30.222 1.723 ;
    END
  END xw_cfg[3]
  PIN xw_cfg[4]
    DIRECTION OUTPUT ;
    USE SIGNAL ;
    PORT
      LAYER M5 ;
        RECT  30.576 0 30.6 0.192 ;
    END
  END xw_cfg[4]
  PIN xw_cfg[5]
    DIRECTION OUTPUT ;
    USE SIGNAL ;
    PORT
      LAYER M3 ;
        RECT  30.996 0 31.014 0.144 ;
    END
    PORT
      LAYER M3 ;
        RECT  30.996 0.108 31.014 1.723 ;
    END
  END xw_cfg[5]
  PIN xw_cfg[6]
    DIRECTION OUTPUT ;
    USE SIGNAL ;
    PORT
      LAYER M5 ;
        RECT  31.392 0 31.416 0.192 ;
    END
  END xw_cfg[6]
  PIN xw_cfg[7]
    DIRECTION OUTPUT ;
    USE SIGNAL ;
    PORT
      LAYER M3 ;
        RECT  31.788 0 31.806 0.144 ;
    END
    PORT
      LAYER M3 ;
        RECT  31.788 0.108 31.806 1.723 ;
    END
  END xw_cfg[7]
  PIN xw_cfg[8]
    DIRECTION OUTPUT ;
    USE SIGNAL ;
    PORT
      LAYER M5 ;
        RECT  32.16 0 32.184 0.192 ;
    END
  END xw_cfg[8]
  PIN xw_cfg[9]
    DIRECTION OUTPUT ;
    USE SIGNAL ;
    PORT
      LAYER M3 ;
        RECT  32.544 0 32.562 0.144 ;
    END
    PORT
      LAYER M3 ;
        RECT  32.544 0.108 32.562 1.723 ;
    END
  END xw_cfg[9]
  PIN xw_last
    DIRECTION OUTPUT ;
    USE SIGNAL ;
    PORT
      LAYER M3 ;
        RECT  28.656 0 28.674 0.144 ;
    END
    PORT
      LAYER M3 ;
        RECT  28.656 0.108 28.674 1.723 ;
    END
  END xw_last
  PIN xw_st
    DIRECTION OUTPUT ;
    USE SIGNAL ;
    PORT
      LAYER M3 ;
        RECT  27.864 0 27.882 0.144 ;
    END
    PORT
      LAYER M3 ;
        RECT  27.864 0.108 27.882 1.723 ;
    END
  END xw_st
  PIN xw_v
    DIRECTION OUTPUT ;
    USE SIGNAL ;
    PORT
      LAYER M5 ;
        RECT  28.272 0 28.296 0.192 ;
    END
  END xw_v
  PIN VDD
    DIRECTION INOUT ;
    USE POWER ;
    PORT
      LAYER M5 ;
        RECT  51.192 2.151 51.312 41.049 ;
        RECT  45.792 2.151 45.912 41.049 ;
        RECT  40.392 2.151 40.512 41.049 ;
        RECT  34.992 2.151 35.112 41.049 ;
        RECT  29.592 2.151 29.712 41.049 ;
        RECT  24.192 2.151 24.312 41.049 ;
        RECT  18.792 2.151 18.912 41.049 ;
        RECT  13.392 2.151 13.512 41.049 ;
        RECT  7.992 2.151 8.112 41.049 ;
        RECT  2.592 2.151 2.712 41.049 ;
    END
  END VDD
  PIN VSS
    DIRECTION INOUT ;
    USE GROUND ;
    PORT
      LAYER M5 ;
        RECT  51 2.137 51.12 41.063 ;
        RECT  45.6 2.137 45.72 41.063 ;
        RECT  40.2 2.137 40.32 41.063 ;
        RECT  34.8 2.137 34.92 41.063 ;
        RECT  29.4 2.137 29.52 41.063 ;
        RECT  24 2.137 24.12 41.063 ;
        RECT  18.6 2.137 18.72 41.063 ;
        RECT  13.2 2.137 13.32 41.063 ;
        RECT  7.8 2.137 7.92 41.063 ;
        RECT  2.4 2.137 2.52 41.063 ;
    END
  END VSS
  # OT_OBS_CLOSED layer=M5 d_um=1.536 added=92
  OBS
    LAYER RVTN ;
     RECT  2.16 2.16 54 2.295 ;
     RECT  2.16 2.565 54 2.835 ;
     RECT  2.16 3.105 54 3.375 ;
     RECT  2.16 3.645 54 3.915 ;
     RECT  2.16 4.185 54 4.455 ;
     RECT  2.16 4.725 54 4.995 ;
     RECT  2.16 5.265 54 5.535 ;
     RECT  2.16 5.805 54 6.075 ;
     RECT  2.16 6.345 54 6.615 ;
     RECT  2.16 6.885 54 7.155 ;
     RECT  2.16 7.425 54 7.695 ;
     RECT  2.16 7.965 54 8.235 ;
     RECT  2.16 8.505 54 8.775 ;
     RECT  2.16 9.045 54 9.315 ;
     RECT  2.16 9.585 54 9.855 ;
     RECT  2.16 10.125 54 10.395 ;
     RECT  2.16 10.665 54 10.935 ;
     RECT  2.16 11.205 54 11.475 ;
     RECT  2.16 11.745 54 12.015 ;
     RECT  2.16 12.285 54 12.555 ;
     RECT  2.16 12.825 54 13.095 ;
     RECT  2.16 13.365 54 13.635 ;
     RECT  2.16 13.905 54 14.175 ;
     RECT  2.16 14.445 54 14.715 ;
     RECT  2.16 14.985 54 15.255 ;
     RECT  2.16 15.525 54 15.795 ;
     RECT  2.16 16.065 54 16.335 ;
     RECT  2.16 16.605 54 16.875 ;
     RECT  2.16 17.145 54 17.415 ;
     RECT  2.16 17.685 54 17.955 ;
     RECT  2.16 18.225 54 18.495 ;
     RECT  2.16 18.765 54 19.035 ;
     RECT  2.16 19.305 54 19.575 ;
     RECT  2.16 19.845 54 20.115 ;
     RECT  2.16 20.385 54 20.655 ;
     RECT  2.16 20.925 54 21.195 ;
     RECT  2.16 21.465 54 21.735 ;
     RECT  2.16 22.005 54 22.275 ;
     RECT  2.16 22.545 54 22.815 ;
     RECT  2.16 23.085 54 23.355 ;
     RECT  2.16 23.625 54 23.895 ;
     RECT  2.16 24.165 54 24.435 ;
     RECT  2.16 24.705 54 24.975 ;
     RECT  2.16 25.245 54 25.515 ;
     RECT  2.16 25.785 54 26.055 ;
     RECT  2.16 26.325 54 26.595 ;
     RECT  2.16 26.865 54 27.135 ;
     RECT  2.16 27.405 54 27.675 ;
     RECT  2.16 27.945 54 28.215 ;
     RECT  2.16 28.485 54 28.755 ;
     RECT  2.16 29.025 54 29.295 ;
     RECT  2.16 29.565 54 29.835 ;
     RECT  2.16 30.105 54 30.375 ;
     RECT  2.16 30.645 54 30.915 ;
     RECT  2.16 31.185 54 31.455 ;
     RECT  2.16 31.725 54 31.995 ;
     RECT  2.16 32.265 54 32.535 ;
     RECT  2.16 32.805 54 33.075 ;
     RECT  2.16 33.345 54 33.615 ;
     RECT  2.16 33.885 54 34.155 ;
     RECT  2.16 34.425 54 34.695 ;
     RECT  2.16 34.965 54 35.235 ;
     RECT  2.16 35.505 54 35.775 ;
     RECT  2.16 36.045 54 36.315 ;
     RECT  2.16 36.585 54 36.855 ;
     RECT  2.16 37.125 54 37.395 ;
     RECT  2.16 37.665 54 37.935 ;
     RECT  2.16 38.205 54 38.475 ;
     RECT  2.16 38.745 54 39.015 ;
     RECT  2.16 39.285 54 39.555 ;
     RECT  2.16 39.825 54 40.095 ;
     RECT  2.16 40.365 54 40.635 ;
     RECT  2.16 40.905 54 41.04 ;
    LAYER RVTP ;
     RECT  2.16 2.295 54 2.565 ;
     RECT  2.16 2.835 54 3.105 ;
     RECT  2.16 3.375 54 3.645 ;
     RECT  2.16 3.915 54 4.185 ;
     RECT  2.16 4.455 54 4.725 ;
     RECT  2.16 4.995 54 5.265 ;
     RECT  2.16 5.535 54 5.805 ;
     RECT  2.16 6.075 54 6.345 ;
     RECT  2.16 6.615 54 6.885 ;
     RECT  2.16 7.155 54 7.425 ;
     RECT  2.16 7.695 54 7.965 ;
     RECT  2.16 8.235 54 8.505 ;
     RECT  2.16 8.775 54 9.045 ;
     RECT  2.16 9.315 54 9.585 ;
     RECT  2.16 9.855 54 10.125 ;
     RECT  2.16 10.395 54 10.665 ;
     RECT  2.16 10.935 54 11.205 ;
     RECT  2.16 11.475 54 11.745 ;
     RECT  2.16 12.015 54 12.285 ;
     RECT  2.16 12.555 54 12.825 ;
     RECT  2.16 13.095 54 13.365 ;
     RECT  2.16 13.635 54 13.905 ;
     RECT  2.16 14.175 54 14.445 ;
     RECT  2.16 14.715 54 14.985 ;
     RECT  2.16 15.255 54 15.525 ;
     RECT  2.16 15.795 54 16.065 ;
     RECT  2.16 16.335 54 16.605 ;
     RECT  2.16 16.875 54 17.145 ;
     RECT  2.16 17.415 54 17.685 ;
     RECT  2.16 17.955 54 18.225 ;
     RECT  2.16 18.495 54 18.765 ;
     RECT  2.16 19.035 54 19.305 ;
     RECT  2.16 19.575 54 19.845 ;
     RECT  2.16 20.115 54 20.385 ;
     RECT  2.16 20.655 54 20.925 ;
     RECT  2.16 21.195 54 21.465 ;
     RECT  2.16 21.735 54 22.005 ;
     RECT  2.16 22.275 54 22.545 ;
     RECT  2.16 22.815 54 23.085 ;
     RECT  2.16 23.355 54 23.625 ;
     RECT  2.16 23.895 54 24.165 ;
     RECT  2.16 24.435 54 24.705 ;
     RECT  2.16 24.975 54 25.245 ;
     RECT  2.16 25.515 54 25.785 ;
     RECT  2.16 26.055 54 26.325 ;
     RECT  2.16 26.595 54 26.865 ;
     RECT  2.16 27.135 54 27.405 ;
     RECT  2.16 27.675 54 27.945 ;
     RECT  2.16 28.215 54 28.485 ;
     RECT  2.16 28.755 54 29.025 ;
     RECT  2.16 29.295 54 29.565 ;
     RECT  2.16 29.835 54 30.105 ;
     RECT  2.16 30.375 54 30.645 ;
     RECT  2.16 30.915 54 31.185 ;
     RECT  2.16 31.455 54 31.725 ;
     RECT  2.16 31.995 54 32.265 ;
     RECT  2.16 32.535 54 32.805 ;
     RECT  2.16 33.075 54 33.345 ;
     RECT  2.16 33.615 54 33.885 ;
     RECT  2.16 34.155 54 34.425 ;
     RECT  2.16 34.695 54 34.965 ;
     RECT  2.16 35.235 54 35.505 ;
     RECT  2.16 35.775 54 36.045 ;
     RECT  2.16 36.315 54 36.585 ;
     RECT  2.16 36.855 54 37.125 ;
     RECT  2.16 37.395 54 37.665 ;
     RECT  2.16 37.935 54 38.205 ;
     RECT  2.16 38.475 54 38.745 ;
     RECT  2.16 39.015 54 39.285 ;
     RECT  2.16 39.555 54 39.825 ;
     RECT  2.16 40.095 54 40.365 ;
     RECT  2.16 40.635 54 40.905 ;
    LAYER M1 ;
     RECT  2.16 2.151 54 41.049 ;
    LAYER M2 ;
     RECT  2.16 2.151 5.287 41.049 ;
     RECT  5.287 1.728 5.567 41.049 ;
     RECT  5.567 2.151 7.483 41.049 ;
     RECT  7.483 2.106 8.267 41.049 ;
     RECT  9.967 0.144 10.067 0.162 ;
     RECT  8.267 2.151 11.515 41.049 ;
     RECT  11.515 2.106 12.307 41.049 ;
     RECT  12.307 2.034 13.855 41.049 ;
     RECT  13.855 1.728 14.171 41.049 ;
     RECT  14.171 2.151 15.403 41.049 ;
     RECT  15.403 1.728 15.827 41.049 ;
     RECT  15.827 2.106 16.691 41.049 ;
     RECT  16.691 2.151 18.535 41.049 ;
     RECT  18.535 1.728 18.779 41.049 ;
     RECT  18.779 2.106 19.003 41.049 ;
     RECT  19.003 2.106 19.103 41.238 ;
     RECT  19.103 2.106 19.823 41.049 ;
     RECT  19.823 2.151 20.875 41.049 ;
     RECT  20.875 1.728 21.083 41.049 ;
     RECT  21.083 2.151 29.443 41.049 ;
     RECT  29.443 1.728 31.091 41.049 ;
     RECT  31.091 2.106 32.539 41.049 ;
     RECT  32.539 1.728 33.071 41.049 ;
     RECT  33.071 2.151 34.087 41.049 ;
     RECT  34.087 2.106 34.879 41.049 ;
     RECT  34.879 2.07 35.447 41.049 ;
     RECT  35.447 2.106 37.219 41.049 ;
     RECT  37.219 1.728 37.607 41.049 ;
     RECT  37.607 2.106 38.471 41.049 ;
     RECT  38.471 2.151 40.171 41.049 ;
     RECT  40.171 2.151 40.343 41.13 ;
     RECT  40.343 2.151 41.107 41.049 ;
     RECT  41.107 1.728 41.531 41.049 ;
     RECT  41.531 2.151 42.655 41.049 ;
     RECT  42.655 2.106 43.007 41.049 ;
     RECT  43.007 2.151 45.715 41.049 ;
     RECT  45.715 2.151 45.959 41.13 ;
     RECT  45.959 2.151 51.115 41.049 ;
     RECT  51.115 2.151 51.215 41.13 ;
     RECT  51.215 2.151 54 41.049 ;
     RECT  54 19.512 54.131 19.53 ;
     RECT  54 15.228 54.563 15.246 ;
     RECT  54 28.188 54.563 28.206 ;
     RECT  54 32.472 54.707 32.49 ;
     RECT  54 36.792 54.707 36.81 ;
     RECT  54 6.516 54.743 6.534 ;
     RECT  54 23.832 54.743 23.85 ;
     RECT  54 10.836 55.283 10.854 ;
    LAYER M3 ;
     RECT  9.972 0.139 10.746 0.167 ;
     RECT  10.044 0.167 10.746 1.723 ;
     RECT  19.296 0.187 20.106 1.723 ;
     RECT  44.244 0.571 45.018 1.723 ;
     RECT  45.792 0.571 46.602 1.723 ;
     RECT  4.5 1.723 6.858 2.101 ;
     RECT  7.632 1.723 16.218 2.101 ;
     RECT  16.956 1.723 20.106 2.101 ;
     RECT  29.448 1.723 33.354 2.143 ;
     RECT  4.5 2.101 20.106 2.155 ;
     RECT  20.88 1.723 28.674 2.155 ;
     RECT  29.415 2.143 33.354 2.155 ;
     RECT  4.5 2.155 33.354 2.219 ;
     RECT  26.64 2.219 33.354 2.263 ;
     RECT  34.092 1.723 41.922 2.263 ;
     RECT  42.66 1.723 51.678 2.263 ;
     RECT  2.415 2.143 2.505 2.413 ;
     RECT  26.64 2.263 51.678 2.641 ;
     RECT  5.004 2.219 24.354 2.759 ;
     RECT  5.148 2.759 24.354 3.145 ;
     RECT  5.148 3.145 24.858 3.335 ;
     RECT  5.328 3.335 24.858 3.379 ;
     RECT  26.64 2.641 51.93 3.379 ;
     RECT  26.64 3.379 52.398 3.415 ;
     RECT  26.64 3.415 52.578 3.451 ;
     RECT  26.64 3.451 53.046 3.649 ;
     RECT  5.328 3.379 25.11 3.685 ;
     RECT  26.532 3.649 53.046 3.749 ;
     RECT  4.428 3.721 4.59 3.773 ;
     RECT  5.328 3.685 25.362 3.838 ;
     RECT  26.532 3.749 51.354 3.875 ;
     RECT  5.328 3.838 25.398 3.947 ;
     RECT  26.532 3.875 50.058 3.947 ;
     RECT  26.532 3.947 27.414 3.965 ;
     RECT  4.572 3.773 4.59 3.983 ;
     RECT  28.224 3.947 50.058 4.013 ;
     RECT  28.224 4.013 48.798 4.019 ;
     RECT  26.712 3.965 27.414 4.109 ;
     RECT  48.78 4.019 48.798 4.109 ;
     RECT  51.015 3.875 51.354 4.109 ;
     RECT  28.224 4.019 47.646 4.145 ;
     RECT  49.716 4.013 50.058 4.145 ;
     RECT  49.824 4.145 50.058 4.379 ;
     RECT  49.824 4.379 50.022 4.415 ;
     RECT  5.328 3.947 24.966 4.495 ;
     RECT  4.608 4.495 24.966 4.541 ;
     RECT  28.368 4.145 47.646 4.541 ;
     RECT  50.004 4.415 50.022 4.559 ;
     RECT  37.836 4.541 47.646 4.649 ;
     RECT  28.368 4.541 36.99 4.721 ;
     RECT  37.98 4.649 47.646 4.829 ;
     RECT  27.18 4.109 27.414 4.891 ;
     RECT  4.788 4.541 24.966 4.919 ;
     RECT  4.788 4.919 5.778 4.991 ;
     RECT  26.784 4.891 27.414 5.027 ;
     RECT  28.656 4.721 36.99 5.027 ;
     RECT  27.396 5.027 27.414 5.063 ;
     RECT  28.656 5.027 28.674 5.063 ;
     RECT  5.508 4.991 5.778 5.069 ;
     RECT  6.84 4.919 22.23 5.099 ;
     RECT  37.98 4.829 47.142 5.099 ;
     RECT  7.38 5.099 22.23 5.165 ;
     RECT  29.415 5.027 36.99 5.189 ;
     RECT  38.952 5.099 47.142 5.189 ;
     RECT  37.98 5.099 37.998 5.225 ;
     RECT  2.415 2.413 2.697 5.275 ;
     RECT  2.304 5.275 2.697 5.431 ;
     RECT  2.304 5.431 3.51 5.459 ;
     RECT  29.415 5.189 32.886 5.459 ;
     RECT  33.66 5.189 36.99 5.459 ;
     RECT  39.24 5.189 40.626 5.459 ;
     RECT  7.596 5.165 22.23 5.495 ;
     RECT  2.415 5.459 3.51 5.575 ;
     RECT  2.415 5.575 3.618 5.611 ;
     RECT  4.572 5.575 4.59 5.611 ;
     RECT  23.328 4.919 24.966 5.741 ;
     RECT  2.415 5.611 4.59 5.999 ;
     RECT  2.415 5.999 4.554 6.269 ;
     RECT  4.068 6.269 4.23 6.305 ;
     RECT  2.415 6.269 3.294 6.317 ;
     RECT  5.508 5.069 5.526 6.511 ;
     RECT  52.38 3.749 53.046 6.511 ;
     RECT  4.212 6.305 4.23 6.539 ;
     RECT  5.508 6.511 5.814 6.539 ;
     RECT  54.72 6.475 54.738 6.539 ;
     RECT  52.38 6.511 53.658 6.611 ;
     RECT  51.015 4.109 51.297 6.655 ;
     RECT  52.38 6.611 53.298 6.655 ;
     RECT  51.015 6.655 51.498 6.691 ;
     RECT  52.344 6.655 53.298 6.691 ;
     RECT  51.015 6.691 53.298 6.845 ;
     RECT  52.416 6.845 53.298 7.079 ;
     RECT  52.416 7.079 53.118 7.115 ;
     RECT  2.415 6.317 2.697 7.195 ;
     RECT  7.815 5.495 22.23 7.349 ;
     RECT  5.796 6.539 5.814 7.357 ;
     RECT  2.415 7.195 2.79 7.385 ;
     RECT  4.824 7.387 4.842 7.393 ;
     RECT  5.652 7.357 5.814 7.421 ;
     RECT  4.176 7.393 4.842 7.427 ;
     RECT  5.652 7.421 5.67 7.501 ;
     RECT  5.004 7.501 5.67 7.619 ;
     RECT  4.176 7.427 4.194 7.655 ;
     RECT  5.652 7.619 5.67 7.655 ;
     RECT  9 7.349 22.23 8.501 ;
     RECT  10.152 8.501 22.23 9.005 ;
     RECT  11.088 9.005 22.23 9.041 ;
     RECT  2.415 7.385 2.697 9.115 ;
     RECT  7.815 7.349 8.097 9.211 ;
     RECT  9 8.501 9.054 9.211 ;
     RECT  14.4 9.041 22.23 9.239 ;
     RECT  2.304 9.115 2.697 9.275 ;
     RECT  7.416 9.211 9.054 9.355 ;
     RECT  6.444 9.349 6.462 9.389 ;
     RECT  7.236 9.355 9.054 9.391 ;
     RECT  6.624 9.391 9.342 9.509 ;
     RECT  3.96 9.391 3.978 9.545 ;
     RECT  14.4 9.239 21.654 9.653 ;
     RECT  10.152 9.005 10.314 9.787 ;
     RECT  11.088 9.041 13.662 9.787 ;
     RECT  7.815 9.509 9.342 10.267 ;
     RECT  10.152 9.787 13.662 10.327 ;
     RECT  14.4 9.653 21.618 10.327 ;
     RECT  10.152 10.327 21.618 10.589 ;
     RECT  7.815 10.267 9.378 10.603 ;
     RECT  10.152 10.589 11.862 10.603 ;
     RECT  7.815 10.603 11.862 10.625 ;
     RECT  12.6 10.589 21.618 10.625 ;
     RECT  7.815 10.625 10.782 10.637 ;
     RECT  11.628 10.625 11.862 10.733 ;
     RECT  11.628 10.733 11.646 10.769 ;
     RECT  12.816 10.625 21.618 10.769 ;
     RECT  13.215 10.769 21.618 10.831 ;
     RECT  55.26 10.795 55.278 10.859 ;
     RECT  49.86 10.933 49.878 10.939 ;
     RECT  51.015 6.845 51.678 10.939 ;
     RECT  49.86 10.939 51.678 10.973 ;
     RECT  7.815 10.637 10.314 11.021 ;
     RECT  2.415 9.275 2.697 11.035 ;
     RECT  13.215 10.831 22.266 11.101 ;
     RECT  2.304 11.035 2.697 11.165 ;
     RECT  13.215 11.101 22.302 11.173 ;
     RECT  23.472 5.741 24.966 11.173 ;
     RECT  50.04 10.973 51.678 11.237 ;
     RECT  52.416 7.115 53.046 11.237 ;
     RECT  7.815 11.021 9.414 11.371 ;
     RECT  6.84 11.281 6.858 11.399 ;
     RECT  7.668 11.371 9.414 11.399 ;
     RECT  5.688 11.281 5.706 11.435 ;
     RECT  8.82 11.399 9.414 11.435 ;
     RECT  13.215 11.173 24.966 11.741 ;
     RECT  13.215 11.741 22.662 11.777 ;
     RECT  13.215 11.777 22.446 11.939 ;
     RECT  13.215 11.939 22.374 12.077 ;
     RECT  13.215 12.077 13.698 12.083 ;
     RECT  14.508 12.077 22.374 12.083 ;
     RECT  14.868 12.083 22.374 12.209 ;
     RECT  2.415 11.165 2.697 12.955 ;
     RECT  15.552 12.209 22.374 12.991 ;
     RECT  49.212 11.209 49.23 12.991 ;
     RECT  50.04 11.237 50.058 12.991 ;
     RECT  15.552 12.991 22.554 13.037 ;
     RECT  2.304 12.955 2.697 13.055 ;
     RECT  15.552 13.037 22.482 13.091 ;
     RECT  4.536 12.901 4.554 13.099 ;
     RECT  2.415 13.055 2.697 13.135 ;
     RECT  4.212 13.099 4.554 13.135 ;
     RECT  2.415 13.135 3.294 13.171 ;
     RECT  4.104 13.135 4.554 13.171 ;
     RECT  9.036 11.435 9.414 13.171 ;
     RECT  10.152 11.021 10.314 13.171 ;
     RECT  2.415 13.171 4.554 13.261 ;
     RECT  2.415 13.261 4.59 13.289 ;
     RECT  2.415 13.289 3.15 13.325 ;
     RECT  15.552 13.091 21.726 13.325 ;
     RECT  20.412 13.325 21.726 13.361 ;
     RECT  20.664 13.361 21.726 13.595 ;
     RECT  15.552 13.325 19.494 13.667 ;
     RECT  53.028 11.237 53.046 13.973 ;
     RECT  9.036 13.171 10.314 14.549 ;
     RECT  15.552 13.667 16.758 14.819 ;
     RECT  4.572 13.289 4.59 14.827 ;
     RECT  2.415 13.325 2.697 14.875 ;
     RECT  4.572 14.827 4.842 14.953 ;
     RECT  5.652 14.917 5.67 14.953 ;
     RECT  6.84 14.917 6.858 15.053 ;
     RECT  9.036 14.549 10.17 15.053 ;
     RECT  7.668 11.399 8.097 15.061 ;
     RECT  47.952 7.699 47.97 15.061 ;
     RECT  7.668 15.061 8.226 15.151 ;
     RECT  4.572 14.953 5.67 15.179 ;
     RECT  47.952 15.061 48.438 15.179 ;
     RECT  53.676 15.061 53.694 15.179 ;
     RECT  2.304 14.875 2.697 15.215 ;
     RECT  5.004 15.179 5.67 15.215 ;
     RECT  5.004 15.215 5.022 15.251 ;
     RECT  54.54 15.115 54.558 15.251 ;
     RECT  47.952 15.179 48.258 15.293 ;
     RECT  49.212 12.991 50.058 15.295 ;
     RECT  49.104 15.295 50.058 15.449 ;
     RECT  2.415 15.215 2.697 16.795 ;
     RECT  2.412 16.795 2.697 16.835 ;
     RECT  7.416 15.151 8.226 16.915 ;
     RECT  7.236 16.915 8.226 17.069 ;
     RECT  6.48 16.951 6.498 17.117 ;
     RECT  2.415 16.835 2.697 18.715 ;
     RECT  7.416 17.069 8.226 18.811 ;
     RECT  2.304 18.715 2.697 18.995 ;
     RECT  6.876 18.811 8.226 19.133 ;
     RECT  52.524 19.381 52.542 19.499 ;
     RECT  54.108 19.435 54.126 19.535 ;
     RECT  41.58 5.189 47.142 19.615 ;
     RECT  47.952 15.293 47.97 19.615 ;
     RECT  39.276 5.459 40.626 19.627 ;
     RECT  41.58 19.615 47.97 19.805 ;
     RECT  49.212 15.449 50.058 19.949 ;
     RECT  9.036 15.053 9.522 20.039 ;
     RECT  48.204 19.898 48.222 20.141 ;
     RECT  7.452 19.133 8.226 20.191 ;
     RECT  38.736 19.627 40.626 20.443 ;
     RECT  7.452 20.191 8.406 20.579 ;
     RECT  2.415 18.995 2.697 20.695 ;
     RECT  7.452 20.579 8.298 20.695 ;
     RECT  4.104 20.695 4.122 20.731 ;
     RECT  38.412 20.443 40.626 20.759 ;
     RECT  2.415 20.695 3.294 20.765 ;
     RECT  38.412 20.759 38.43 20.765 ;
     RECT  4.104 20.731 4.554 20.849 ;
     RECT  4.536 20.849 4.554 20.885 ;
     RECT  6.912 20.695 8.298 20.885 ;
     RECT  20.772 13.595 21.726 20.965 ;
     RECT  22.464 13.091 22.482 20.965 ;
     RECT  7.128 20.885 8.298 21.119 ;
     RECT  29.415 5.459 32.13 21.355 ;
     RECT  29.124 21.355 32.13 21.433 ;
     RECT  28.8 21.433 32.13 21.485 ;
     RECT  2.415 20.765 2.697 22.555 ;
     RECT  5.796 20.659 5.814 22.711 ;
     RECT  2.304 22.555 2.697 22.775 ;
     RECT  4.824 22.747 4.842 22.811 ;
     RECT  5.796 22.711 6.138 22.855 ;
     RECT  5.688 22.855 6.138 23.009 ;
     RECT  49.392 19.949 50.058 23.387 ;
     RECT  13.215 12.083 13.497 23.521 ;
     RECT  13.215 23.521 13.878 23.597 ;
     RECT  51.015 11.237 51.678 23.629 ;
     RECT  9.504 20.039 9.522 23.665 ;
     RECT  51.015 23.629 52.074 23.665 ;
     RECT  51.015 23.665 52.794 23.701 ;
     RECT  51.015 23.701 53.046 23.819 ;
     RECT  54.72 23.755 54.738 23.855 ;
     RECT  51.015 23.819 52.362 23.927 ;
     RECT  14.292 23.701 14.31 23.933 ;
     RECT  52.344 23.927 52.362 24.089 ;
     RECT  9.504 23.665 9.666 24.169 ;
     RECT  5.796 23.009 6.138 24.241 ;
     RECT  7.128 21.119 8.262 24.241 ;
     RECT  9.504 24.169 9.882 24.359 ;
     RECT  10.836 24.367 10.854 24.403 ;
     RECT  5.796 24.241 8.262 24.431 ;
     RECT  9.504 24.359 9.666 24.431 ;
     RECT  10.836 24.403 10.926 24.467 ;
     RECT  2.415 22.775 2.697 24.475 ;
     RECT  10.908 24.467 10.926 24.503 ;
     RECT  2.304 24.475 2.697 24.665 ;
     RECT  5.796 24.431 8.097 24.899 ;
     RECT  25.812 10.399 25.83 25.681 ;
     RECT  49.5 23.387 50.058 25.709 ;
     RECT  20.772 20.965 22.482 26.257 ;
     RECT  25.776 25.681 25.83 26.257 ;
     RECT  51.015 23.927 51.606 26.285 ;
     RECT  20.772 26.257 22.554 26.293 ;
     RECT  23.472 11.741 24.966 26.293 ;
     RECT  25.776 26.257 25.902 26.321 ;
     RECT  6.228 24.899 8.097 26.365 ;
     RECT  9.036 24.475 9.054 26.365 ;
     RECT  20.772 26.293 24.966 26.365 ;
     RECT  25.776 26.321 25.83 26.365 ;
     RECT  2.415 24.665 2.697 26.395 ;
     RECT  6.228 26.365 9.054 26.519 ;
     RECT  2.304 26.395 2.697 26.555 ;
     RECT  20.772 26.365 25.83 26.599 ;
     RECT  17.82 13.667 19.494 26.635 ;
     RECT  20.304 26.599 25.83 26.635 ;
     RECT  29.415 21.485 32.13 26.671 ;
     RECT  32.868 5.459 32.886 26.671 ;
     RECT  6.984 26.519 8.874 26.717 ;
     RECT  8.856 26.717 8.874 26.789 ;
     RECT  15.552 14.819 16.686 26.797 ;
     RECT  17.82 26.635 25.83 26.797 ;
     RECT  27.972 11.011 27.99 26.797 ;
     RECT  29.415 26.671 33.282 26.905 ;
     RECT  34.38 5.459 36.99 26.905 ;
     RECT  17.748 26.797 25.83 26.933 ;
     RECT  29.415 26.905 36.99 26.941 ;
     RECT  27.972 26.797 28.098 27.067 ;
     RECT  15.552 26.797 16.758 27.139 ;
     RECT  17.748 26.933 24.822 27.139 ;
     RECT  15.552 27.139 24.822 27.203 ;
     RECT  27.972 27.067 28.17 27.337 ;
     RECT  29.196 26.941 36.99 27.337 ;
     RECT  27.36 27.337 28.17 27.373 ;
     RECT  29.088 27.337 36.99 27.373 ;
     RECT  27.36 27.373 36.99 27.635 ;
     RECT  25.812 26.933 25.83 27.643 ;
     RECT  26.568 27.163 26.586 27.643 ;
     RECT  27.612 27.635 36.99 27.677 ;
     RECT  25.812 27.643 26.586 27.913 ;
     RECT  27.828 27.677 36.99 27.913 ;
     RECT  2.415 26.555 2.697 27.931 ;
     RECT  27.828 27.913 37.242 28.021 ;
     RECT  51.015 26.285 51.297 28.021 ;
     RECT  13.215 23.597 13.497 28.111 ;
     RECT  15.552 27.203 24.714 28.123 ;
     RECT  49.5 25.709 49.59 28.147 ;
     RECT  13.104 28.111 13.497 28.157 ;
     RECT  10.764 28.111 10.782 28.171 ;
     RECT  12.312 28.111 12.33 28.205 ;
     RECT  54.54 28.075 54.558 28.211 ;
     RECT  49.212 28.147 49.59 28.219 ;
     RECT  50.436 28.021 51.297 28.219 ;
     RECT  14.832 28.123 24.714 28.253 ;
     RECT  6.228 26.519 6.246 28.291 ;
     RECT  6.984 26.717 8.097 28.291 ;
     RECT  38.304 28.255 38.322 28.291 ;
     RECT  2.415 27.931 3.294 28.315 ;
     RECT  10.764 28.171 10.854 28.319 ;
     RECT  6.228 28.291 8.097 28.409 ;
     RECT  10.764 28.319 10.782 28.409 ;
     RECT  49.212 28.219 51.297 28.409 ;
     RECT  4.212 28.291 4.23 28.417 ;
     RECT  27.828 28.021 37.494 28.417 ;
     RECT  38.304 28.291 38.502 28.417 ;
     RECT  2.304 28.315 3.294 28.445 ;
     RECT  51.015 28.409 51.297 28.453 ;
     RECT  4.032 28.417 4.23 28.481 ;
     RECT  49.212 28.409 50.058 28.481 ;
     RECT  4.032 28.481 4.05 28.715 ;
     RECT  52.992 28.291 53.01 28.715 ;
     RECT  27.792 28.417 38.502 28.759 ;
     RECT  39.276 20.759 40.626 28.759 ;
     RECT  51.015 28.453 51.426 28.787 ;
     RECT  25.812 27.913 26.802 28.795 ;
     RECT  27.792 28.759 40.626 28.795 ;
     RECT  25.812 28.795 40.626 28.985 ;
     RECT  27.72 28.985 40.626 29.021 ;
     RECT  25.812 28.985 26.946 29.029 ;
     RECT  27.756 29.021 40.626 29.219 ;
     RECT  6.228 28.409 6.282 29.227 ;
     RECT  7.128 28.409 8.097 29.227 ;
     RECT  15.552 28.253 24.714 29.227 ;
     RECT  15.552 29.227 24.75 29.365 ;
     RECT  25.704 29.029 26.946 29.365 ;
     RECT  6.228 29.227 8.097 29.371 ;
     RECT  15.552 29.365 26.946 29.399 ;
     RECT  27.756 29.219 38.502 29.489 ;
     RECT  23.904 29.399 26.946 29.839 ;
     RECT  27.756 29.489 33.534 29.839 ;
     RECT  39.276 29.219 40.626 29.911 ;
     RECT  41.58 19.805 47.142 29.911 ;
     RECT  15.552 29.399 22.986 30.145 ;
     RECT  15.552 30.145 23.094 30.181 ;
     RECT  23.904 29.839 33.534 30.181 ;
     RECT  34.308 29.489 38.502 30.181 ;
     RECT  39.276 29.911 40.698 30.181 ;
     RECT  2.415 28.445 2.697 30.235 ;
     RECT  6.156 29.371 8.097 30.271 ;
     RECT  2.304 30.235 2.697 30.335 ;
     RECT  15.552 30.181 33.534 30.335 ;
     RECT  34.308 30.181 40.698 30.343 ;
     RECT  5.796 30.271 8.097 30.415 ;
     RECT  15.552 30.335 33.066 30.451 ;
     RECT  34.092 30.343 40.698 30.451 ;
     RECT  41.508 29.911 47.142 30.451 ;
     RECT  34.092 30.451 47.142 30.479 ;
     RECT  5.688 30.415 8.097 30.569 ;
     RECT  15.228 30.451 33.066 30.641 ;
     RECT  34.164 30.479 47.142 30.641 ;
     RECT  15.228 30.641 32.994 30.649 ;
     RECT  4.824 30.331 4.842 30.749 ;
     RECT  14.652 30.649 32.994 30.749 ;
     RECT  34.38 30.641 47.142 30.811 ;
     RECT  25.812 30.749 32.994 31.387 ;
     RECT  25.812 31.387 33.102 31.415 ;
     RECT  13.215 28.157 13.497 31.423 ;
     RECT  28.872 31.415 33.102 31.435 ;
     RECT  13.215 31.423 13.734 31.459 ;
     RECT  28.872 31.435 33.138 31.459 ;
     RECT  34.38 30.811 47.214 31.459 ;
     RECT  14.724 30.749 25.074 31.483 ;
     RECT  25.812 31.415 27.99 31.483 ;
     RECT  13.215 31.459 13.878 31.579 ;
     RECT  14.724 31.483 27.99 31.579 ;
     RECT  13.215 31.579 27.99 31.649 ;
     RECT  28.872 31.459 47.214 31.685 ;
     RECT  13.215 31.649 26.298 31.765 ;
     RECT  13.14 31.765 26.298 31.927 ;
     RECT  12.924 31.927 26.298 32.035 ;
     RECT  12.42 32.035 26.298 32.099 ;
     RECT  2.415 30.335 2.697 32.155 ;
     RECT  27.144 31.649 27.99 32.189 ;
     RECT  6.12 30.569 8.097 32.197 ;
     RECT  2.304 32.155 2.697 32.225 ;
     RECT  5.868 32.197 8.097 32.237 ;
     RECT  47.952 24.367 47.97 32.341 ;
     RECT  49.212 28.481 49.518 32.341 ;
     RECT  52.2 32.269 52.218 32.341 ;
     RECT  6.12 32.237 8.097 32.459 ;
     RECT  47.952 32.341 48.438 32.459 ;
     RECT  52.2 32.341 52.398 32.459 ;
     RECT  53.46 32.269 53.478 32.459 ;
     RECT  12.42 32.099 26.226 32.495 ;
     RECT  54.684 32.395 54.702 32.495 ;
     RECT  49.212 32.341 49.626 32.539 ;
     RECT  28.908 31.685 47.214 32.575 ;
     RECT  28.728 32.575 47.214 32.729 ;
     RECT  12.42 32.495 25.866 32.765 ;
     RECT  49.032 32.539 49.626 32.801 ;
     RECT  28.728 32.729 29.898 32.837 ;
     RECT  27.144 32.189 27.882 32.845 ;
     RECT  49.608 32.801 49.626 32.909 ;
     RECT  13.176 32.765 25.866 32.999 ;
     RECT  30.672 32.729 47.214 32.999 ;
     RECT  13.176 32.999 21.906 33.035 ;
     RECT  47.952 32.459 48.258 33.053 ;
     RECT  13.176 33.035 21.582 33.071 ;
     RECT  22.788 32.999 25.866 33.241 ;
     RECT  27 32.845 27.882 33.259 ;
     RECT  26.928 33.259 27.882 33.305 ;
     RECT  27 33.305 27.882 33.313 ;
     RECT  28.728 32.837 29.697 33.313 ;
     RECT  22.788 33.241 26.154 33.341 ;
     RECT  24.015 33.341 26.154 33.349 ;
     RECT  51.015 28.787 51.297 33.349 ;
     RECT  30.672 32.999 31.95 33.575 ;
     RECT  32.832 32.999 47.214 33.575 ;
     RECT  30.672 33.575 31.662 33.611 ;
     RECT  30.672 33.611 31.482 33.619 ;
     RECT  30.636 33.619 31.482 33.691 ;
     RECT  18.108 33.071 21.582 33.853 ;
     RECT  22.788 33.341 23.274 33.853 ;
     RECT  49.464 33.781 49.482 33.853 ;
     RECT  50.436 33.349 51.297 33.925 ;
     RECT  52.02 33.385 52.038 33.925 ;
     RECT  6.156 32.459 8.097 33.961 ;
     RECT  27 33.313 29.697 33.961 ;
     RECT  30.6 33.691 31.482 33.961 ;
     RECT  37.008 33.575 47.214 33.961 ;
     RECT  47.952 33.053 47.97 33.961 ;
     RECT  2.415 32.225 2.697 34.051 ;
     RECT  13.176 33.071 17.298 34.051 ;
     RECT  18.108 33.853 23.274 34.051 ;
     RECT  13.176 34.051 23.274 34.075 ;
     RECT  24.015 33.349 26.262 34.075 ;
     RECT  6.156 33.961 8.298 34.079 ;
     RECT  2.415 34.051 3.222 34.231 ;
     RECT  37.008 33.961 47.97 34.231 ;
     RECT  48.888 33.853 49.482 34.231 ;
     RECT  2.415 34.231 3.582 34.349 ;
     RECT  10.98 29.731 10.998 34.619 ;
     RECT  6.156 34.079 8.097 34.627 ;
     RECT  53.568 33.889 53.586 34.663 ;
     RECT  32.832 33.575 36.198 34.699 ;
     RECT  6.048 34.627 8.097 34.763 ;
     RECT  27 33.961 31.482 34.763 ;
     RECT  13.176 34.075 26.262 34.829 ;
     RECT  32.544 34.699 36.198 34.843 ;
     RECT  27.792 34.763 31.482 34.897 ;
     RECT  12.42 32.765 12.438 34.969 ;
     RECT  13.176 34.829 14.922 34.969 ;
     RECT  27.792 34.897 31.626 35.005 ;
     RECT  32.436 34.843 36.198 35.005 ;
     RECT  37.008 34.231 49.482 35.005 ;
     RECT  53.172 34.663 53.586 35.041 ;
     RECT  15.66 34.829 26.262 35.167 ;
     RECT  27 34.763 27.018 35.167 ;
     RECT  11.628 35.401 11.646 35.581 ;
     RECT  12.42 34.969 14.922 35.581 ;
     RECT  15.66 35.167 27.018 35.581 ;
     RECT  11.628 35.581 27.018 35.671 ;
     RECT  27.792 35.005 49.482 35.671 ;
     RECT  6.048 34.763 6.894 35.969 ;
     RECT  2.415 34.349 2.697 35.977 ;
     RECT  10.656 35.041 10.674 35.977 ;
     RECT  4.068 35.977 4.086 36.013 ;
     RECT  2.304 35.977 3.294 36.029 ;
     RECT  10.656 35.977 10.854 36.049 ;
     RECT  11.628 35.671 49.482 36.049 ;
     RECT  7.632 34.763 8.097 36.085 ;
     RECT  9.072 35.311 9.09 36.085 ;
     RECT  10.656 36.049 49.482 36.085 ;
     RECT  2.415 36.029 3.294 36.121 ;
     RECT  4.068 36.013 4.23 36.121 ;
     RECT  10.656 36.085 49.626 36.121 ;
     RECT  50.436 33.925 52.038 36.121 ;
     RECT  2.415 36.121 4.23 36.239 ;
     RECT  4.068 36.239 4.23 36.275 ;
     RECT  6.048 35.969 6.642 36.391 ;
     RECT  9.072 36.085 9.594 36.391 ;
     RECT  4.212 36.275 4.23 36.419 ;
     RECT  2.415 36.239 3.294 36.461 ;
     RECT  53.172 35.041 53.658 36.509 ;
     RECT  53.172 36.509 53.586 36.625 ;
     RECT  10.44 36.121 52.038 36.661 ;
     RECT  53.028 36.625 53.586 36.661 ;
     RECT  7.524 36.085 8.097 36.751 ;
     RECT  8.928 36.391 9.594 36.751 ;
     RECT  5.4 36.391 6.642 36.787 ;
     RECT  7.524 36.751 9.594 36.787 ;
     RECT  54.684 36.715 54.702 36.815 ;
     RECT  10.44 36.661 53.586 37.021 ;
     RECT  5.4 36.787 9.594 37.165 ;
     RECT  10.404 37.021 53.586 37.165 ;
     RECT  5.4 37.165 53.586 37.561 ;
     RECT  5.328 37.561 53.586 37.831 ;
     RECT  4.86 37.831 53.586 37.963 ;
     RECT  2.415 36.461 2.697 38.011 ;
     RECT  2.415 38.011 3.402 38.165 ;
     RECT  3.96 38.395 3.978 38.471 ;
     RECT  4.824 37.963 53.586 38.515 ;
     RECT  4.752 38.515 53.586 38.551 ;
     RECT  4.14 38.551 53.586 38.669 ;
     RECT  4.86 38.669 53.586 39.181 ;
     RECT  4.86 39.181 53.694 39.245 ;
     RECT  4.86 39.245 53.586 39.451 ;
     RECT  4.716 39.451 53.586 39.595 ;
     RECT  4.68 39.595 53.586 39.749 ;
     RECT  4.68 39.749 53.262 40.019 ;
     RECT  4.68 40.019 53.046 40.027 ;
     RECT  4.608 40.027 53.046 40.171 ;
     RECT  4.572 40.171 53.046 40.559 ;
     RECT  4.572 40.559 52.794 40.711 ;
     RECT  2.415 38.165 2.697 40.787 ;
     RECT  4.176 40.711 52.794 40.829 ;
     RECT  6.156 40.829 11.358 40.865 ;
     RECT  12.096 40.829 51.858 40.901 ;
     RECT  15.66 40.901 51.858 40.937 ;
     RECT  4.176 40.829 4.914 40.945 ;
     RECT  27.756 40.937 51.858 40.973 ;
     RECT  6.156 40.865 11.286 41.009 ;
     RECT  52.668 40.829 52.794 41.009 ;
     RECT  52.776 41.009 52.794 41.021 ;
     RECT  2.415 40.787 2.505 41.057 ;
     RECT  6.156 41.009 11.07 42.187 ;
     RECT  12.096 40.901 14.922 42.187 ;
     RECT  15.66 40.937 26.982 42.187 ;
     RECT  27.756 40.973 51.642 42.187 ;
     RECT  3.96 40.945 4.914 42.221 ;
     RECT  4.392 42.221 4.914 43.068 ;
     RECT  6.156 42.187 51.642 43.068 ;
    LAYER M4 ;
     RECT  2.408 2.148 2.512 41.052 ;
     RECT  2.512 2.418 2.704 40.782 ;
     RECT  2.704 6.144 2.801 7.224 ;
     RECT  2.704 36.432 3.971 36.456 ;
     RECT  3.925 37.968 4.012 38.424 ;
     RECT  4.417 3.744 4.501 3.768 ;
     RECT  4.501 3.744 4.547 5.064 ;
     RECT  2.801 6.144 4.547 6.312 ;
     RECT  3.949 42.192 4.547 42.216 ;
     RECT  2.704 13.152 4.595 13.176 ;
     RECT  4.547 4.512 4.637 5.064 ;
     RECT  4.741 40.464 4.777 40.488 ;
     RECT  4.789 30.336 4.813 30.36 ;
     RECT  4.777 40.464 4.828 40.728 ;
     RECT  4.549 14.832 4.853 14.856 ;
     RECT  4.012 37.968 4.853 37.992 ;
     RECT  4.789 7.392 4.876 7.416 ;
     RECT  4.813 30.336 4.876 30.744 ;
     RECT  4.876 30.72 4.897 30.744 ;
     RECT  4.885 1.728 4.997 1.752 ;
     RECT  4.828 40.704 5.027 40.728 ;
     RECT  4.637 5.04 5.789 5.064 ;
     RECT  5.653 2.16 5.861 2.184 ;
     RECT  4.813 22.752 5.939 22.776 ;
     RECT  5.852 24.672 5.939 24.696 ;
     RECT  4.837 32.208 5.939 32.232 ;
     RECT  6.181 42.192 6.323 42.216 ;
     RECT  6.389 1.728 6.473 1.752 ;
     RECT  4.789 9.36 6.473 9.384 ;
     RECT  6.469 40.944 6.613 40.968 ;
     RECT  6.541 37.056 6.685 37.32 ;
     RECT  6.853 18.816 6.86 18.84 ;
     RECT  6.037 4.56 6.901 4.584 ;
     RECT  6.613 40.944 7.292 41.016 ;
     RECT  6.685 37.056 7.333 38.04 ;
     RECT  6.901 4.56 7.369 4.728 ;
     RECT  7.292 40.464 7.765 41.016 ;
     RECT  7.237 2.16 7.808 2.184 ;
     RECT  7.369 4.56 7.808 5.16 ;
     RECT  4.547 6.144 7.808 6.168 ;
     RECT  4.549 11.136 7.808 11.16 ;
     RECT  6.469 17.088 7.808 17.112 ;
     RECT  6.86 18.816 7.808 19.128 ;
     RECT  2.704 20.736 7.808 20.76 ;
     RECT  6.901 23.664 7.808 23.688 ;
     RECT  2.704 27.936 7.808 27.96 ;
     RECT  5.893 33.648 7.808 33.672 ;
     RECT  7.333 36.912 7.808 38.04 ;
     RECT  6.721 39.36 7.808 39.384 ;
     RECT  7.765 40.464 7.808 41.208 ;
     RECT  7.808 2.148 7.945 41.208 ;
     RECT  7.945 2.148 8.005 41.64 ;
     RECT  8.005 1.728 8.104 41.64 ;
     RECT  8.104 10.992 8.165 11.16 ;
     RECT  8.104 39.312 8.165 41.64 ;
     RECT  8.104 27.936 8.243 28.248 ;
     RECT  8.104 26.688 8.245 26.712 ;
     RECT  8.165 39.312 8.531 41.16 ;
     RECT  8.531 39.312 8.641 41.016 ;
     RECT  8.104 2.784 9.029 6.168 ;
     RECT  8.641 39.312 9.065 40.488 ;
     RECT  8.104 37.632 9.097 38.04 ;
     RECT  9.029 3.216 9.107 6.168 ;
     RECT  9.065 39.888 9.155 40.488 ;
     RECT  9.097 36.816 9.277 38.136 ;
     RECT  9.107 4.368 9.349 6.168 ;
     RECT  8.165 10.992 9.349 11.016 ;
     RECT  8.773 42.192 9.395 42.216 ;
     RECT  9.107 3.216 9.425 3.24 ;
     RECT  9.349 10.272 9.433 11.016 ;
     RECT  9.433 10.608 9.677 11.016 ;
     RECT  9.155 40.464 10.117 40.488 ;
     RECT  9.277 36.576 10.213 38.136 ;
     RECT  9.097 8.4 10.429 8.424 ;
     RECT  10.429 8.4 10.469 8.52 ;
     RECT  10.213 35.712 10.537 38.136 ;
     RECT  9.349 4.368 10.609 6.648 ;
     RECT  9.677 10.608 10.741 10.632 ;
     RECT  8.243 28.224 10.753 28.248 ;
     RECT  10.469 8.496 10.787 8.52 ;
     RECT  10.537 35.712 10.789 38.808 ;
     RECT  10.753 28.128 10.793 28.248 ;
     RECT  10.741 9.792 10.828 10.632 ;
     RECT  10.117 40.464 10.969 40.584 ;
     RECT  10.789 35.712 11.185 39.288 ;
     RECT  10.969 40.464 11.185 40.68 ;
     RECT  10.537 42.192 11.269 42.216 ;
     RECT  10.609 4.368 11.329 7.368 ;
     RECT  11.257 9.072 11.405 9.096 ;
     RECT  11.185 35.712 11.411 40.68 ;
     RECT  11.329 4.224 11.441 7.368 ;
     RECT  11.441 4.224 11.473 6.888 ;
     RECT  11.269 42.192 11.585 42.312 ;
     RECT  11.509 7.968 11.651 7.992 ;
     RECT  8.104 1.728 11.653 1.752 ;
     RECT  10.825 2.832 11.653 2.856 ;
     RECT  11.473 4.176 11.653 6.888 ;
     RECT  10.828 10.608 11.833 10.632 ;
     RECT  11.411 35.712 11.837 39.336 ;
     RECT  11.585 42.192 11.837 42.216 ;
     RECT  11.833 10.608 11.873 10.728 ;
     RECT  11.411 40.416 12.157 40.68 ;
     RECT  12.301 8.4 12.445 8.424 ;
     RECT  11.653 4.128 12.589 6.888 ;
     RECT  11.653 1.728 12.697 2.856 ;
     RECT  12.589 3.888 12.697 6.888 ;
     RECT  11.837 35.712 12.949 39.24 ;
     RECT  12.157 40.416 12.949 41.016 ;
     RECT  12.697 1.728 13.021 6.888 ;
     RECT  13.021 32.304 13.057 32.328 ;
     RECT  8.104 23.808 13.093 23.832 ;
     RECT  12.949 35.712 13.093 41.016 ;
     RECT  13.021 1.728 13.165 7.368 ;
     RECT  13.165 1.728 13.208 7.416 ;
     RECT  12.445 8.4 13.208 8.52 ;
     RECT  12.913 9.552 13.208 9.576 ;
     RECT  11.873 10.704 13.208 10.728 ;
     RECT  13.093 23.808 13.208 23.928 ;
     RECT  10.793 28.128 13.208 28.2 ;
     RECT  13.057 32.208 13.208 32.328 ;
     RECT  13.093 35.712 13.208 41.208 ;
     RECT  13.208 1.728 13.504 41.208 ;
     RECT  13.504 34.656 13.597 41.208 ;
     RECT  13.597 34.656 13.889 41.64 ;
     RECT  13.504 10.704 13.907 12.072 ;
     RECT  13.907 11.424 13.961 12.072 ;
     RECT  13.504 1.728 14.069 8.808 ;
     RECT  14.069 1.728 14.105 7.464 ;
     RECT  13.504 23.568 14.321 23.928 ;
     RECT  14.069 8.736 14.645 8.808 ;
     RECT  13.504 28.128 14.821 28.2 ;
     RECT  14.569 31.584 14.821 31.608 ;
     RECT  14.645 8.784 14.861 8.808 ;
     RECT  14.821 28.128 14.861 28.248 ;
     RECT  14.821 31.344 15.073 31.608 ;
     RECT  14.857 33.6 15.073 33.624 ;
     RECT  15.073 31.344 15.109 32.184 ;
     RECT  13.961 12.048 15.113 12.072 ;
     RECT  14.105 3.024 15.217 7.416 ;
     RECT  15.109 31.344 15.325 32.616 ;
     RECT  15.073 33.6 15.325 33.672 ;
     RECT  15.217 3.024 15.361 7.464 ;
     RECT  15.145 42.192 15.394 42.216 ;
     RECT  15.394 42.192 15.395 42.264 ;
     RECT  15.325 31.344 15.437 33.672 ;
     RECT  15.437 31.344 15.473 31.608 ;
     RECT  15.437 32.592 15.473 33.672 ;
     RECT  13.889 34.656 15.901 41.016 ;
     RECT  14.105 1.728 15.905 1.752 ;
     RECT  15.395 42.24 15.971 42.264 ;
     RECT  15.901 34.656 16.115 41.064 ;
     RECT  15.473 32.784 16.297 33.672 ;
     RECT  16.115 34.656 16.297 41.016 ;
     RECT  15.361 9.648 16.405 9.672 ;
     RECT  15.473 31.44 16.405 31.608 ;
     RECT  15.361 2.88 16.481 7.464 ;
     RECT  16.481 2.88 16.513 7.368 ;
     RECT  14.861 28.176 16.549 28.248 ;
     RECT  16.261 8.448 16.553 8.472 ;
     RECT  16.405 9.648 16.589 9.768 ;
     RECT  16.405 31.44 16.621 31.704 ;
     RECT  16.589 9.744 16.625 9.768 ;
     RECT  16.621 30.816 16.661 31.704 ;
     RECT  16.513 2.16 16.733 7.368 ;
     RECT  16.549 28.176 16.741 28.776 ;
     RECT  16.741 27.312 16.787 28.776 ;
     RECT  17.084 12.24 17.125 12.264 ;
     RECT  16.297 32.784 17.165 41.016 ;
     RECT  17.125 12.24 17.171 13.128 ;
     RECT  17.165 32.784 17.197 40.728 ;
     RECT  16.661 30.816 17.273 30.888 ;
     RECT  16.733 2.16 17.365 4.488 ;
     RECT  16.787 27.312 17.893 28.248 ;
     RECT  16.733 5.52 17.917 7.368 ;
     RECT  17.809 8.496 17.917 8.52 ;
     RECT  17.917 5.52 17.989 8.52 ;
     RECT  17.365 1.728 18.181 4.488 ;
     RECT  17.989 5.52 18.181 8.568 ;
     RECT  18.188 19.68 18.205 19.704 ;
     RECT  18.205 19.344 18.229 19.704 ;
     RECT  14.321 23.568 18.229 23.832 ;
     RECT  17.273 30.864 18.325 30.888 ;
     RECT  17.197 32.544 18.325 40.728 ;
     RECT  17.449 29.856 18.421 29.88 ;
     RECT  18.325 30.864 18.469 40.728 ;
     RECT  18.181 1.728 18.608 8.568 ;
     RECT  17.737 10.8 18.608 10.824 ;
     RECT  17.171 13.104 18.608 13.128 ;
     RECT  18.229 19.248 18.608 19.704 ;
     RECT  18.325 21.456 18.608 21.576 ;
     RECT  18.229 23.568 18.608 23.928 ;
     RECT  17.893 26.64 18.608 28.248 ;
     RECT  18.421 29.76 18.608 29.88 ;
     RECT  18.469 30.864 18.608 41.208 ;
     RECT  18.608 1.728 18.659 41.208 ;
     RECT  18.659 1.728 18.904 41.16 ;
     RECT  18.904 6.144 19.001 6.36 ;
     RECT  18.904 33.024 19.037 41.16 ;
     RECT  18.904 27.888 19.043 30.696 ;
     RECT  18.904 8.496 19.109 8.616 ;
     RECT  19.109 8.592 19.145 8.616 ;
     RECT  18.904 1.728 19.253 1.752 ;
     RECT  18.904 3.024 19.379 5.112 ;
     RECT  18.904 12.72 19.379 13.128 ;
     RECT  18.904 26.64 19.397 26.76 ;
     RECT  19.043 27.888 19.541 27.912 ;
     RECT  17.989 42.192 19.577 42.216 ;
     RECT  19.037 33.024 19.667 40.92 ;
     RECT  19.379 13.104 19.865 13.128 ;
     RECT  19.667 33.024 19.869 40.536 ;
     RECT  19.669 0.192 19.937 0.216 ;
     RECT  19.043 29.568 19.969 30.696 ;
     RECT  18.904 31.776 19.969 31.8 ;
     RECT  19.379 3.024 20.041 4.584 ;
     RECT  20.041 2.928 20.185 4.584 ;
     RECT  18.904 10.896 20.221 11.016 ;
     RECT  19.969 29.568 20.257 31.8 ;
     RECT  20.221 10.848 20.261 11.016 ;
     RECT  18.904 7.392 20.329 7.416 ;
     RECT  20.185 2.736 20.485 4.584 ;
     RECT  19.869 33.024 20.513 40.488 ;
     RECT  20.437 12.384 20.545 12.408 ;
     RECT  19.397 26.736 20.545 26.76 ;
     RECT  20.261 10.848 20.653 10.872 ;
     RECT  20.653 10.8 20.765 10.872 ;
     RECT  20.545 12.336 20.765 12.408 ;
     RECT  20.485 2.16 20.941 4.584 ;
     RECT  20.257 29.568 21.053 31.896 ;
     RECT  20.513 33.264 21.061 40.488 ;
     RECT  21.053 29.568 21.155 29.592 ;
     RECT  21.053 30.96 21.155 31.896 ;
     RECT  20.941 2.16 21.253 4.968 ;
     RECT  20.765 12.384 21.301 12.408 ;
     RECT  20.329 7.392 21.341 7.464 ;
     RECT  20.545 26.736 21.481 27.192 ;
     RECT  20.765 10.848 21.485 10.872 ;
     RECT  21.253 1.728 21.517 4.968 ;
     RECT  19.001 6.144 21.517 6.264 ;
     RECT  21.301 12.384 21.557 12.936 ;
     RECT  21.557 12.816 21.625 12.936 ;
     RECT  21.481 26.736 21.637 27.336 ;
     RECT  21.637 26.736 21.683 27.96 ;
     RECT  21.683 26.736 21.809 26.76 ;
     RECT  21.517 1.728 21.841 6.264 ;
     RECT  21.155 31.872 21.877 31.896 ;
     RECT  21.061 33.264 21.877 40.584 ;
     RECT  21.841 1.728 21.881 6.648 ;
     RECT  21.625 12.816 21.881 13.032 ;
     RECT  21.877 31.872 21.917 40.584 ;
     RECT  21.881 2.928 21.953 6.648 ;
     RECT  21.683 27.936 22.025 27.96 ;
     RECT  21.953 2.928 22.169 6.168 ;
     RECT  21.881 13.008 22.565 13.032 ;
     RECT  21.917 32.64 22.633 40.584 ;
     RECT  22.633 32.64 22.921 40.632 ;
     RECT  22.381 41.616 22.921 41.64 ;
     RECT  22.921 32.64 23.141 41.64 ;
     RECT  22.813 26.736 23.317 26.76 ;
     RECT  22.169 2.928 23.569 4.488 ;
     RECT  21.881 1.728 24.008 1.752 ;
     RECT  23.569 2.928 24.008 4.728 ;
     RECT  22.169 5.712 24.008 6.168 ;
     RECT  18.904 21.456 24.008 21.48 ;
     RECT  23.317 26.736 24.008 27.192 ;
     RECT  22.417 29.088 24.008 29.112 ;
     RECT  22.993 31.104 24.008 31.128 ;
     RECT  23.141 32.64 24.008 41.208 ;
     RECT  24.008 1.728 24.035 41.208 ;
     RECT  23.749 42.192 24.145 42.216 ;
     RECT  24.035 1.728 24.304 41.16 ;
     RECT  24.304 33.408 24.323 41.16 ;
     RECT  24.323 33.408 24.851 41.016 ;
     RECT  24.145 42.192 24.901 42.264 ;
     RECT  24.901 42.192 25.091 42.36 ;
     RECT  24.851 33.408 25.625 40.632 ;
     RECT  25.405 32.208 25.729 32.232 ;
     RECT  24.304 30.48 25.765 30.504 ;
     RECT  25.625 33.408 25.877 40.488 ;
     RECT  25.877 33.408 25.949 40.296 ;
     RECT  25.765 30.432 26.197 30.504 ;
     RECT  25.729 31.488 26.197 32.232 ;
     RECT  25.949 33.408 26.197 40.152 ;
     RECT  26.197 30.432 26.243 32.232 ;
     RECT  24.304 3.024 26.521 3.048 ;
     RECT  24.304 4.176 26.521 4.728 ;
     RECT  26.521 3.024 26.605 4.728 ;
     RECT  24.304 29.376 26.701 29.4 ;
     RECT  26.243 30.432 26.701 31.32 ;
     RECT  24.304 27.168 26.773 27.192 ;
     RECT  26.701 29.376 26.773 31.32 ;
     RECT  26.773 27.168 26.819 27.96 ;
     RECT  26.197 33.264 26.957 40.152 ;
     RECT  26.773 28.944 27.137 31.32 ;
     RECT  26.957 33.408 27.349 40.152 ;
     RECT  26.605 4.176 27.425 4.728 ;
     RECT  26.819 27.648 27.529 27.96 ;
     RECT  27.137 28.944 27.529 29.736 ;
     RECT  27.137 31.296 27.605 31.32 ;
     RECT  26.605 3.024 27.709 3.048 ;
     RECT  27.425 4.176 27.709 4.2 ;
     RECT  27.349 33.408 27.856 40.488 ;
     RECT  24.304 21.456 27.925 21.48 ;
     RECT  27.529 27.648 27.965 29.736 ;
     RECT  27.965 27.648 28.073 28.296 ;
     RECT  27.241 42.192 28.081 42.216 ;
     RECT  27.856 33.408 28.117 40.536 ;
     RECT  24.304 1.728 28.249 1.752 ;
     RECT  27.709 3.024 28.249 4.2 ;
     RECT  27.965 29.568 28.397 29.736 ;
     RECT  28.249 1.728 28.469 4.2 ;
     RECT  28.469 2.148 28.501 4.2 ;
     RECT  28.073 27.648 29.041 27.72 ;
     RECT  28.501 2.148 29.077 4.488 ;
     RECT  28.117 33.408 29.269 40.632 ;
     RECT  29.077 2.148 29.408 4.776 ;
     RECT  27.925 21.36 29.408 21.48 ;
     RECT  29.041 27.648 29.408 28.488 ;
     RECT  28.397 29.568 29.408 29.64 ;
     RECT  29.269 33.408 29.408 41.208 ;
     RECT  29.408 2.148 29.459 41.208 ;
     RECT  29.459 2.148 29.704 41.16 ;
     RECT  29.704 2.148 29.789 4.776 ;
     RECT  29.704 31.296 29.843 41.16 ;
     RECT  29.789 1.728 29.873 4.776 ;
     RECT  29.704 26.832 30.053 29.592 ;
     RECT  29.843 31.296 30.323 41.016 ;
     RECT  30.323 31.296 30.737 31.32 ;
     RECT  30.323 32.448 30.845 41.016 ;
     RECT  29.873 2.16 30.881 4.776 ;
     RECT  30.053 26.832 30.913 28.968 ;
     RECT  30.913 26.784 30.953 28.968 ;
     RECT  30.841 30.816 30.953 30.936 ;
     RECT  30.845 32.544 30.953 41.016 ;
     RECT  30.953 26.784 31.025 27.192 ;
     RECT  31.025 26.832 31.097 27.192 ;
     RECT  31.097 26.832 31.133 26.952 ;
     RECT  30.881 2.88 31.201 4.776 ;
     RECT  30.953 32.688 31.235 41.016 ;
     RECT  30.953 30.912 31.781 30.936 ;
     RECT  31.235 32.688 31.853 40.728 ;
     RECT  30.953 28.656 31.957 28.968 ;
     RECT  31.201 2.88 31.961 5.064 ;
     RECT  31.381 1.728 32.393 1.752 ;
     RECT  31.957 28.128 32.485 28.968 ;
     RECT  31.853 32.688 32.501 40.584 ;
     RECT  32.501 32.688 32.531 40.536 ;
     RECT  31.133 26.832 32.533 26.856 ;
     RECT  32.485 28.128 32.572 29.448 ;
     RECT  32.572 28.128 32.573 29.016 ;
     RECT  32.137 31.44 32.749 31.464 ;
     RECT  32.531 32.688 32.749 40.488 ;
     RECT  31.961 2.88 32.917 4.2 ;
     RECT  32.533 26.832 32.929 27.144 ;
     RECT  32.929 26.832 32.969 27.336 ;
     RECT  32.917 2.16 33.109 4.2 ;
     RECT  32.245 5.184 33.109 5.208 ;
     RECT  33.109 2.16 33.149 5.208 ;
     RECT  32.749 31.44 33.149 40.488 ;
     RECT  33.149 31.68 33.185 40.488 ;
     RECT  32.969 27.12 33.545 27.336 ;
     RECT  32.573 28.944 33.613 29.016 ;
     RECT  33.613 28.464 33.653 29.016 ;
     RECT  33.545 27.12 33.833 27.144 ;
     RECT  33.185 31.872 34.153 40.488 ;
     RECT  34.153 31.68 34.309 40.488 ;
     RECT  34.309 31.68 34.693 41.016 ;
     RECT  34.693 31.392 34.789 41.016 ;
     RECT  33.685 1.728 34.808 1.752 ;
     RECT  33.149 2.88 34.808 5.208 ;
     RECT  29.704 21.456 34.808 21.48 ;
     RECT  33.653 28.464 34.808 28.968 ;
     RECT  34.789 31.392 34.808 41.208 ;
     RECT  34.808 1.728 35.077 41.208 ;
     RECT  35.077 1.728 35.104 41.304 ;
     RECT  35.104 30.72 35.267 41.304 ;
     RECT  35.104 3.648 35.705 5.208 ;
     RECT  35.267 30.72 35.891 40.632 ;
     RECT  35.891 30.72 35.921 40.536 ;
     RECT  35.921 30.816 36.101 40.488 ;
     RECT  36.101 30.816 36.361 32.472 ;
     RECT  35.104 28.464 36.461 28.968 ;
     RECT  35.705 3.696 36.997 5.208 ;
     RECT  36.361 31.392 37.393 32.472 ;
     RECT  36.101 33.648 37.393 40.488 ;
     RECT  36.461 28.944 37.573 28.968 ;
     RECT  37.393 31.392 37.612 40.488 ;
     RECT  37.612 31.392 37.685 40.536 ;
     RECT  37.685 40.416 37.789 40.536 ;
     RECT  36.997 3.264 37.861 5.208 ;
     RECT  37.789 40.416 37.907 40.632 ;
     RECT  37.861 2.736 37.973 5.208 ;
     RECT  37.573 28.944 38.077 29.88 ;
     RECT  37.685 31.392 38.077 39.384 ;
     RECT  35.104 21.456 38.147 21.48 ;
     RECT  38.077 28.944 38.197 39.384 ;
     RECT  38.197 28.848 38.243 39.384 ;
     RECT  38.243 29.856 38.297 39.384 ;
     RECT  38.101 20.448 38.396 20.472 ;
     RECT  38.396 20.448 38.441 20.76 ;
     RECT  38.441 20.736 38.483 20.76 ;
     RECT  38.243 28.848 38.483 28.872 ;
     RECT  38.257 42.24 38.797 42.264 ;
     RECT  38.797 42.192 38.798 42.264 ;
     RECT  38.297 30.72 38.821 39.384 ;
     RECT  37.907 40.416 38.821 40.488 ;
     RECT  37.973 2.88 39.017 5.208 ;
     RECT  38.821 30.72 39.097 40.488 ;
     RECT  39.097 31.104 39.121 40.488 ;
     RECT  38.798 42.192 39.347 42.216 ;
     RECT  38.725 19.632 40.069 19.656 ;
     RECT  39.121 31.104 40.069 41.016 ;
     RECT  35.104 1.728 40.208 1.752 ;
     RECT  39.017 3.12 40.208 5.208 ;
     RECT  39.877 10.8 40.208 10.824 ;
     RECT  39.877 14.832 40.208 14.856 ;
     RECT  40.069 19.632 40.208 19.8 ;
     RECT  40.069 31.104 40.208 41.208 ;
     RECT  40.208 1.728 40.259 41.208 ;
     RECT  40.259 1.728 40.504 41.16 ;
     RECT  40.504 30.336 40.643 41.16 ;
     RECT  40.643 30.336 41.393 40.584 ;
     RECT  41.393 30.336 42.101 39.144 ;
     RECT  42.101 30.192 42.185 39.144 ;
     RECT  40.504 1.728 42.217 1.752 ;
     RECT  40.504 2.736 42.217 4.68 ;
     RECT  42.185 30.336 42.323 39.144 ;
     RECT  42.323 31.632 42.796 39.144 ;
     RECT  42.323 30.336 43.013 30.6 ;
     RECT  41.393 40.464 43.372 40.584 ;
     RECT  42.217 1.728 43.661 4.68 ;
     RECT  43.661 1.728 43.877 1.752 ;
     RECT  42.796 31.632 43.985 32.568 ;
     RECT  42.796 33.648 44.149 39.144 ;
     RECT  44.149 33.648 44.197 39.24 ;
     RECT  43.985 31.632 44.485 31.896 ;
     RECT  43.661 2.784 44.561 4.68 ;
     RECT  44.561 3.12 44.597 4.68 ;
     RECT  44.197 33.072 44.633 39.24 ;
     RECT  44.521 0.576 44.675 0.6 ;
     RECT  44.633 33.072 45.013 33.384 ;
     RECT  45.169 1.728 45.443 1.752 ;
     RECT  43.372 40.464 45.589 40.536 ;
     RECT  44.597 3.408 45.608 4.68 ;
     RECT  40.504 19.776 45.608 19.8 ;
     RECT  43.013 30.336 45.608 30.36 ;
     RECT  44.485 31.488 45.608 31.896 ;
     RECT  45.013 32.928 45.608 33.384 ;
     RECT  44.633 34.704 45.608 39.24 ;
     RECT  45.589 40.464 45.608 41.208 ;
     RECT  45.608 2.148 45.712 41.208 ;
     RECT  45.712 2.418 45.904 41.208 ;
     RECT  45.904 31.488 46.019 31.512 ;
     RECT  45.904 33.552 46.067 41.208 ;
     RECT  46.067 40.464 46.115 41.208 ;
     RECT  46.133 0.576 46.217 0.6 ;
     RECT  45.904 3.408 46.217 4.2 ;
     RECT  46.067 33.552 46.289 39.24 ;
     RECT  45.904 30.336 46.451 30.36 ;
     RECT  46.115 40.464 46.684 40.536 ;
     RECT  46.289 33.552 46.793 33.672 ;
     RECT  46.289 34.704 47.276 39.24 ;
     RECT  47.276 34.56 47.363 39.24 ;
     RECT  47.363 34.992 47.477 39.24 ;
     RECT  47.477 36.48 47.545 39.24 ;
     RECT  46.684 40.464 47.545 40.488 ;
     RECT  47.545 36.48 47.653 40.488 ;
     RECT  47.653 36.48 47.765 40.584 ;
     RECT  46.217 3.408 47.833 3.624 ;
     RECT  47.765 40.464 47.873 40.584 ;
     RECT  47.852 42.192 47.939 42.216 ;
     RECT  47.477 34.992 47.945 35.016 ;
     RECT  47.833 3.408 48.013 3.816 ;
     RECT  45.904 19.632 48.181 19.8 ;
     RECT  48.181 19.632 48.268 20.136 ;
     RECT  47.317 33.024 48.269 33.048 ;
     RECT  48.188 15.264 48.275 15.288 ;
     RECT  48.268 19.632 48.275 19.944 ;
     RECT  48.275 19.92 48.277 19.944 ;
     RECT  48.013 3.312 48.665 3.816 ;
     RECT  48.665 3.552 48.881 3.816 ;
     RECT  47.765 36.48 48.913 39.24 ;
     RECT  47.873 40.464 48.913 40.488 ;
     RECT  48.913 36.48 49.169 40.488 ;
     RECT  49.381 3.984 49.745 4.008 ;
     RECT  49.169 38.64 49.805 40.488 ;
     RECT  48.229 11.376 49.82 11.4 ;
     RECT  45.904 28.224 49.889 28.248 ;
     RECT  49.82 10.944 49.907 11.4 ;
     RECT  49.805 38.64 49.993 40.536 ;
     RECT  49.993 38.64 49.997 40.632 ;
     RECT  49.169 36.48 50.06 37.656 ;
     RECT  50.605 42.192 50.723 42.216 ;
     RECT  50.06 36.432 50.725 37.656 ;
     RECT  49.997 39.216 50.821 40.632 ;
     RECT  46.933 1.728 51.008 1.752 ;
     RECT  49.861 6.672 51.008 6.696 ;
     RECT  45.904 23.616 51.008 23.64 ;
     RECT  50.725 36.432 51.008 38.184 ;
     RECT  50.821 39.216 51.008 41.304 ;
     RECT  51.008 1.728 51.299 41.304 ;
     RECT  51.299 1.728 51.304 41.016 ;
     RECT  51.304 6.672 51.509 6.696 ;
     RECT  51.304 23.616 51.509 23.64 ;
     RECT  51.304 40.464 51.581 41.016 ;
     RECT  51.304 36.576 51.587 39.24 ;
     RECT  51.304 1.728 51.689 1.752 ;
     RECT  51.587 36.576 52.355 37.512 ;
     RECT  51.587 38.784 52.364 39.24 ;
     RECT  52.364 38.784 52.451 39.288 ;
     RECT  52.369 6.816 52.517 6.84 ;
     RECT  52.451 38.784 52.553 39.24 ;
     RECT  51.581 40.512 52.805 41.016 ;
     RECT  52.94 37.584 53.027 37.608 ;
     RECT  52.953 40.464 53.057 40.488 ;
     RECT  52.355 36.576 53.237 36.6 ;
     RECT  52.553 39.216 53.705 39.24 ;
    LAYER M5 ;
     RECT  4.896 0.144 51.672 0.227 ;
     RECT  20.496 0.227 51.672 0.611 ;
     RECT  4.896 0.227 18.936 1.763 ;
     RECT  20.496 0.611 43.848 1.763 ;
     RECT  45.408 0.611 45.432 1.763 ;
     RECT  46.944 0.611 51.672 1.763 ;
     RECT  2.4 2.137 2.52 2.151 ;
     RECT  45.6 2.137 45.72 2.151 ;
     RECT  5.664 1.763 5.688 2.195 ;
     RECT  7.248 1.763 8.112 2.195 ;
     RECT  16.56 1.763 16.584 2.195 ;
     RECT  20.496 1.763 20.52 2.195 ;
     RECT  29.04 1.763 30.6 2.195 ;
     RECT  32.928 1.763 32.952 2.195 ;
     RECT  40.2 1.763 40.512 2.725 ;
     RECT  7.8 2.195 8.112 2.773 ;
     RECT  7.8 2.773 8.904 3.205 ;
     RECT  37.872 2.725 37.896 3.301 ;
     RECT  37.872 3.301 37.992 3.347 ;
     RECT  34.8 1.763 35.112 3.397 ;
     RECT  13.2 1.763 13.848 3.827 ;
     RECT  18.192 1.763 18.912 3.925 ;
     RECT  7.8 3.205 9.096 4.019 ;
     RECT  18.192 3.925 19.368 4.691 ;
     RECT  34.656 3.397 35.112 4.691 ;
     RECT  40.2 2.725 40.68 4.691 ;
     RECT  26.544 3.925 26.568 4.739 ;
     RECT  29.088 2.195 29.712 4.787 ;
     RECT  11.664 4.117 11.688 5.171 ;
     RECT  37.968 3.347 37.992 5.171 ;
     RECT  40.2 4.691 40.512 5.173 ;
     RECT  4.512 3.733 4.536 6.323 ;
     RECT  18.6 4.691 19.368 6.325 ;
     RECT  11.616 5.221 11.64 8.003 ;
     RECT  9.36 5.077 9.384 10.307 ;
     RECT  10.752 8.485 10.776 10.643 ;
     RECT  13.2 3.827 13.512 10.693 ;
     RECT  40.08 5.173 40.512 10.789 ;
     RECT  4.8 7.381 4.824 11.125 ;
     RECT  4.56 11.125 4.824 11.171 ;
     RECT  49.872 6.661 49.896 11.411 ;
     RECT  13.2 10.693 13.896 11.459 ;
     RECT  17.136 12.229 17.16 13.139 ;
     RECT  18.48 6.325 19.368 13.139 ;
     RECT  4.56 11.171 4.584 14.867 ;
     RECT  39.888 10.789 40.512 14.867 ;
     RECT  7.8 4.019 8.112 17.077 ;
     RECT  6.864 17.077 8.112 18.851 ;
     RECT  18.48 13.139 18.912 19.237 ;
     RECT  40.08 14.867 40.512 19.811 ;
     RECT  48.24 11.365 48.264 19.955 ;
     RECT  38.112 20.437 38.136 20.725 ;
     RECT  27.936 21.349 27.96 21.445 ;
     RECT  27.936 21.445 28.056 21.491 ;
     RECT  45.6 2.151 45.912 23.605 ;
     RECT  48.192 20.101 48.216 23.651 ;
     RECT  6.912 18.851 8.112 23.699 ;
     RECT  13.2 11.459 13.512 23.797 ;
     RECT  18.24 19.237 18.912 23.797 ;
     RECT  13.104 23.797 13.512 23.939 ;
     RECT  7.8 23.699 8.112 26.677 ;
     RECT  24 1.763 24.312 26.725 ;
     RECT  29.4 4.787 29.712 26.821 ;
     RECT  23.328 26.725 24.312 27.203 ;
     RECT  17.904 23.797 18.912 27.395 ;
     RECT  5.904 22.741 5.928 27.971 ;
     RECT  21.648 27.301 21.672 27.971 ;
     RECT  26.784 27.157 26.808 27.971 ;
     RECT  18.336 27.395 18.912 28.213 ;
     RECT  7.8 26.677 8.232 28.259 ;
     RECT  29.4 26.821 30.264 28.643 ;
     RECT  16.752 27.301 16.776 28.787 ;
     RECT  38.112 20.725 38.472 28.883 ;
     RECT  32.496 28.645 32.52 29.459 ;
     RECT  18.336 28.213 19.032 29.557 ;
     RECT  18.336 29.557 19.176 29.989 ;
     RECT  4.8 27.925 4.824 30.371 ;
     RECT  45.6 23.605 46.44 30.371 ;
     RECT  26.784 28.933 26.808 30.563 ;
     RECT  38.112 28.883 38.232 30.709 ;
     RECT  36.288 28.453 36.312 30.851 ;
     RECT  38.112 30.709 39.048 30.851 ;
     RECT  42.144 30.181 42.168 31.189 ;
     RECT  29.4 28.643 29.712 31.285 ;
     RECT  38.208 30.851 39.048 31.285 ;
     RECT  40.2 19.811 40.512 31.285 ;
     RECT  42.144 31.189 42.312 31.331 ;
     RECT  45.6 30.371 46.008 31.523 ;
     RECT  38.208 31.285 40.512 31.667 ;
     RECT  39.024 31.667 40.512 31.765 ;
     RECT  18.336 29.989 19.368 31.811 ;
     RECT  45.6 31.523 45.912 31.861 ;
     RECT  21.12 29.557 21.144 31.907 ;
     RECT  29.4 31.285 30.312 32.051 ;
     RECT  4.848 30.709 4.872 32.243 ;
     RECT  42.288 31.331 42.312 32.485 ;
     RECT  39.024 31.765 40.968 32.531 ;
     RECT  42.288 32.485 42.456 32.963 ;
     RECT  45.024 31.861 45.912 32.963 ;
     RECT  39.024 32.531 40.512 33.011 ;
     RECT  42.336 32.963 42.456 33.349 ;
     RECT  39.168 33.011 40.512 33.539 ;
     RECT  16.896 33.013 16.92 33.541 ;
     RECT  18.6 31.811 19.368 33.541 ;
     RECT  45.6 32.963 45.912 33.589 ;
     RECT  5.904 32.197 5.928 33.683 ;
     RECT  24 27.203 24.312 33.685 ;
     RECT  26.208 31.285 26.232 33.829 ;
     RECT  45.6 33.589 46.008 34.069 ;
     RECT  15.984 33.541 19.368 34.165 ;
     RECT  20.448 34.069 20.472 34.165 ;
     RECT  39.216 33.539 40.512 34.165 ;
     RECT  45.6 34.069 46.056 34.165 ;
     RECT  28.032 21.491 28.056 34.357 ;
     RECT  30.768 33.061 30.792 34.357 ;
     RECT  15.984 34.165 20.472 34.597 ;
     RECT  45.6 34.165 46.104 34.693 ;
     RECT  42.336 33.349 42.744 34.741 ;
     RECT  44.16 33.925 44.184 34.741 ;
     RECT  39.216 34.165 40.824 34.787 ;
     RECT  15.984 34.597 21.384 34.789 ;
     RECT  29.4 32.051 29.712 34.789 ;
     RECT  30.768 34.357 31.368 34.789 ;
     RECT  28.032 34.357 28.392 34.837 ;
     RECT  29.4 34.789 31.368 34.837 ;
     RECT  28.032 34.837 31.368 34.981 ;
     RECT  28.032 34.981 31.512 35.123 ;
     RECT  31.344 35.123 31.512 35.267 ;
     RECT  39.216 34.787 40.512 35.269 ;
     RECT  42.336 34.741 44.184 35.317 ;
     RECT  15.792 34.789 21.384 35.411 ;
     RECT  33.264 35.365 33.288 35.557 ;
     RECT  34.8 4.691 35.112 35.557 ;
     RECT  36.432 34.741 36.456 35.557 ;
     RECT  38.784 35.269 40.512 35.557 ;
     RECT  28.032 35.123 28.392 35.651 ;
     RECT  26.208 33.829 26.76 35.653 ;
     RECT  33.264 35.557 33.72 35.653 ;
     RECT  24 33.685 24.792 35.701 ;
     RECT  26.112 35.653 26.76 35.701 ;
     RECT  15.888 35.411 21.384 35.795 ;
     RECT  31.344 35.267 31.368 35.795 ;
     RECT  33.024 35.653 33.72 35.843 ;
     RECT  24 35.701 26.76 35.845 ;
     RECT  33.072 35.843 33.72 35.845 ;
     RECT  34.8 35.557 36.456 35.845 ;
     RECT  33.072 35.845 36.456 35.939 ;
     RECT  22.8 35.845 26.76 36.085 ;
     RECT  28.032 35.651 28.056 36.085 ;
     RECT  29.4 35.123 29.832 36.133 ;
     RECT  45.6 34.693 46.344 36.133 ;
     RECT  47.328 33.013 47.352 36.133 ;
     RECT  33.072 35.939 35.88 36.227 ;
     RECT  22.8 36.085 28.056 36.373 ;
     RECT  11.376 36.373 11.4 36.421 ;
     RECT  51 1.763 51.312 36.421 ;
     RECT  38.016 35.557 40.512 36.515 ;
     RECT  42.192 35.317 44.184 36.515 ;
     RECT  45.6 36.133 47.352 36.515 ;
     RECT  33.696 36.227 35.88 36.659 ;
     RECT  50.112 36.421 51.312 36.661 ;
     RECT  14.784 35.941 14.808 36.709 ;
     RECT  15.888 35.795 21.096 36.709 ;
     RECT  29.088 36.133 29.832 36.709 ;
     RECT  29.088 36.709 30.12 36.805 ;
     RECT  38.016 36.515 39.096 36.853 ;
     RECT  22.176 36.373 28.056 36.901 ;
     RECT  29.088 36.805 30.312 36.901 ;
     RECT  14.784 36.709 21.096 36.947 ;
     RECT  37.056 36.853 39.096 36.995 ;
     RECT  22.176 36.901 30.312 37.043 ;
     RECT  42.192 36.515 42.792 37.043 ;
     RECT  22.176 37.043 25.224 37.187 ;
     RECT  45.6 36.515 46.824 37.235 ;
     RECT  27.024 37.043 30.312 37.283 ;
     RECT  42.72 37.043 42.792 37.283 ;
     RECT  15.12 36.947 21.096 37.333 ;
     RECT  22.8 37.187 25.224 37.379 ;
     RECT  27.024 37.283 29.712 37.571 ;
     RECT  50.016 36.661 51.312 37.573 ;
     RECT  52.32 37.477 52.344 37.573 ;
     RECT  34.032 36.659 35.88 37.619 ;
     RECT  42.72 37.283 42.744 37.619 ;
     RECT  7.8 28.259 8.112 37.621 ;
     RECT  10.224 35.701 10.248 37.667 ;
     RECT  40.2 36.515 40.512 37.669 ;
     RECT  40.2 37.669 41.4 37.811 ;
     RECT  22.8 37.379 25.128 37.907 ;
     RECT  7.8 37.621 8.376 37.909 ;
     RECT  40.2 37.811 41.064 38.003 ;
     RECT  7.68 37.909 8.376 38.005 ;
     RECT  11.376 36.421 12.216 38.053 ;
     RECT  49.824 37.573 51.312 38.149 ;
     RECT  52.32 37.573 53.016 38.149 ;
     RECT  44.16 36.515 44.184 38.197 ;
     RECT  37.44 36.995 39.096 38.243 ;
     RECT  3.936 36.421 3.96 38.435 ;
     RECT  22.848 37.907 25.128 38.629 ;
     RECT  38.016 38.243 39.096 38.629 ;
     RECT  40.2 38.003 40.512 38.629 ;
     RECT  32.4 38.773 32.424 38.915 ;
     RECT  26.448 38.101 26.472 39.061 ;
     RECT  27.456 37.571 29.712 39.061 ;
     RECT  10.8 38.053 12.216 39.107 ;
     RECT  22.848 38.629 25.368 39.109 ;
     RECT  26.448 39.061 29.712 39.109 ;
     RECT  15.12 37.333 21.768 39.157 ;
     RECT  22.848 39.109 29.712 39.157 ;
     RECT  44.16 38.197 44.616 39.251 ;
     RECT  15.12 39.157 29.712 39.301 ;
     RECT  7.68 38.005 8.52 39.395 ;
     RECT  38.016 38.629 40.512 39.589 ;
     RECT  13.2 23.939 13.512 39.829 ;
     RECT  15.12 39.301 29.832 39.829 ;
     RECT  7.8 39.395 8.52 39.877 ;
     RECT  12.96 39.829 13.512 39.877 ;
     RECT  32.736 39.349 32.76 39.877 ;
     RECT  34.032 37.619 35.544 39.877 ;
     RECT  7.8 39.877 9.144 40.453 ;
     RECT  10.8 39.107 11.976 40.453 ;
     RECT  12.96 39.877 14.04 40.453 ;
     RECT  15.12 39.829 29.976 40.453 ;
     RECT  32.736 39.877 36.12 40.453 ;
     RECT  38.016 39.589 41.016 40.453 ;
     RECT  44.592 39.251 44.616 40.453 ;
     RECT  45.6 37.235 46.104 40.453 ;
     RECT  49.824 38.149 53.016 40.453 ;
     RECT  43.536 40.453 53.016 40.499 ;
     RECT  7.344 40.453 30.456 40.501 ;
     RECT  32.736 40.453 41.784 40.501 ;
     RECT  43.536 40.499 52.44 40.501 ;
     RECT  7.344 40.501 52.44 40.547 ;
     RECT  4.752 40.453 4.776 40.693 ;
     RECT  7.344 40.547 51.768 40.933 ;
     RECT  2.4 2.151 2.712 41.049 ;
     RECT  2.4 41.049 2.52 41.063 ;
     RECT  4.752 40.693 5.016 42.181 ;
     RECT  6.576 40.933 51.768 42.181 ;
     RECT  4.512 42.181 5.016 43.024 ;
     RECT  6.288 42.181 51.768 43.024 ;
     RECT  45.432 0.611 46.944 1.763 ;
     RECT  8.112 1.763 9.096 2.773 ;
     RECT  37.872 1.763 37.896 2.725 ;
     RECT  40.512 1.763 40.68 2.725 ;
     RECT  45.6 1.763 45.912 2.137 ;
     RECT  45.72 2.137 45.912 2.151 ;
     RECT  8.904 2.773 9.096 3.205 ;
     RECT  8.112 4.019 9.096 5.077 ;
     RECT  11.688 4.117 13.2 5.171 ;
     RECT  8.112 5.077 9.36 10.307 ;
     RECT  49.896 6.661 51 11.411 ;
     RECT  9.384 8.485 10.752 10.307 ;
     RECT  17.16 12.229 18.48 13.139 ;
     RECT  27.96 21.349 29.4 21.445 ;
     RECT  28.056 21.445 29.4 34.357 ;
     RECT  5.928 22.741 6.912 23.699 ;
     RECT  26.808 27.157 28.032 27.971 ;
     RECT  16.776 27.301 17.904 27.395 ;
     RECT  4.824 27.925 5.904 27.971 ;
     RECT  26.784 27.971 28.032 28.933 ;
     RECT  35.112 28.453 36.288 30.851 ;
     RECT  26.808 28.933 28.032 30.563 ;
     RECT  39.048 30.709 40.2 31.285 ;
     RECT  42.144 31.331 42.288 31.765 ;
     RECT  45.912 31.523 46.008 33.013 ;
     RECT  40.968 31.765 42.288 32.531 ;
     RECT  29.712 32.051 30.312 33.061 ;
     RECT  4.872 32.197 5.904 32.243 ;
     RECT  42.288 32.963 42.336 34.165 ;
     RECT  45.024 32.963 45.6 33.925 ;
     RECT  45.912 33.013 47.328 33.589 ;
     RECT  29.712 33.061 30.768 34.789 ;
     RECT  46.008 33.589 47.328 34.069 ;
     RECT  24.792 33.685 26.208 35.653 ;
     RECT  26.76 33.829 28.032 36.085 ;
     RECT  42.744 33.925 44.16 34.741 ;
     RECT  44.184 33.925 45.6 38.197 ;
     RECT  19.368 34.069 20.448 34.165 ;
     RECT  46.056 34.069 47.328 34.165 ;
     RECT  40.824 34.165 42.336 34.787 ;
     RECT  46.104 34.165 47.328 34.693 ;
     RECT  28.392 34.357 29.4 34.837 ;
     RECT  46.344 34.693 47.328 36.133 ;
     RECT  35.112 34.741 36.432 35.557 ;
     RECT  42.192 34.787 42.336 35.317 ;
     RECT  28.392 35.123 29.4 35.651 ;
     RECT  29.832 35.123 31.344 35.795 ;
     RECT  33.288 35.365 34.8 35.557 ;
     RECT  15.792 35.411 15.888 35.941 ;
     RECT  33.72 35.557 34.8 35.845 ;
     RECT  28.056 35.651 29.4 36.133 ;
     RECT  24.792 35.653 26.112 35.701 ;
     RECT  21.096 35.795 21.384 35.845 ;
     RECT  29.832 35.795 30.312 36.709 ;
     RECT  21.096 35.845 22.8 36.373 ;
     RECT  35.88 35.939 36.456 36.853 ;
     RECT  13.512 35.941 14.784 36.947 ;
     RECT  14.808 35.941 15.888 36.709 ;
     RECT  28.056 36.133 29.088 36.901 ;
     RECT  10.248 36.373 11.376 37.667 ;
     RECT  21.096 36.373 22.176 37.187 ;
     RECT  2.712 36.421 3.936 38.435 ;
     RECT  12.216 36.421 13.2 39.107 ;
     RECT  39.096 36.515 40.2 38.629 ;
     RECT  42.792 36.515 44.16 37.283 ;
     RECT  30.12 36.709 30.312 36.805 ;
     RECT  35.88 36.853 37.056 36.995 ;
     RECT  25.224 37.043 27.024 37.379 ;
     RECT  21.096 37.187 22.8 37.333 ;
     RECT  42.744 37.283 44.16 37.619 ;
     RECT  21.768 37.333 22.8 37.907 ;
     RECT  25.128 37.379 27.024 37.571 ;
     RECT  51.312 37.477 52.32 38.149 ;
     RECT  25.128 37.571 27.456 38.101 ;
     RECT  10.8 37.667 11.376 38.053 ;
     RECT  21.768 37.907 22.848 39.157 ;
     RECT  25.128 38.101 26.448 38.629 ;
     RECT  26.472 38.101 27.456 39.061 ;
     RECT  44.616 38.197 45.6 40.453 ;
     RECT  25.368 38.629 26.448 39.109 ;
     RECT  11.976 39.107 13.2 39.829 ;
     RECT  44.16 39.251 44.592 40.453 ;
     RECT  32.76 39.349 34.032 39.877 ;
     RECT  7.68 39.395 7.8 40.453 ;
     RECT  11.976 39.829 12.96 40.453 ;
     RECT  14.04 39.877 15.12 40.453 ;
     RECT  5.016 42.181 6.288 42.96 ;
     RECT  5.064 42.96 5.232 43.024 ;
     RECT  5.352 42.96 5.472 43.024 ;
     RECT  5.592 42.96 5.76 43.024 ;
     RECT  5.88 42.96 6 43.024 ;
     RECT  6.12 42.96 6.24 43.024 ;
  END
END dsfd_su_t_rxcc
END LIBRARY
